VERSION 5.8 ;
BUSBITCHARS "[]" ;
DIVIDERCHAR "/" ;

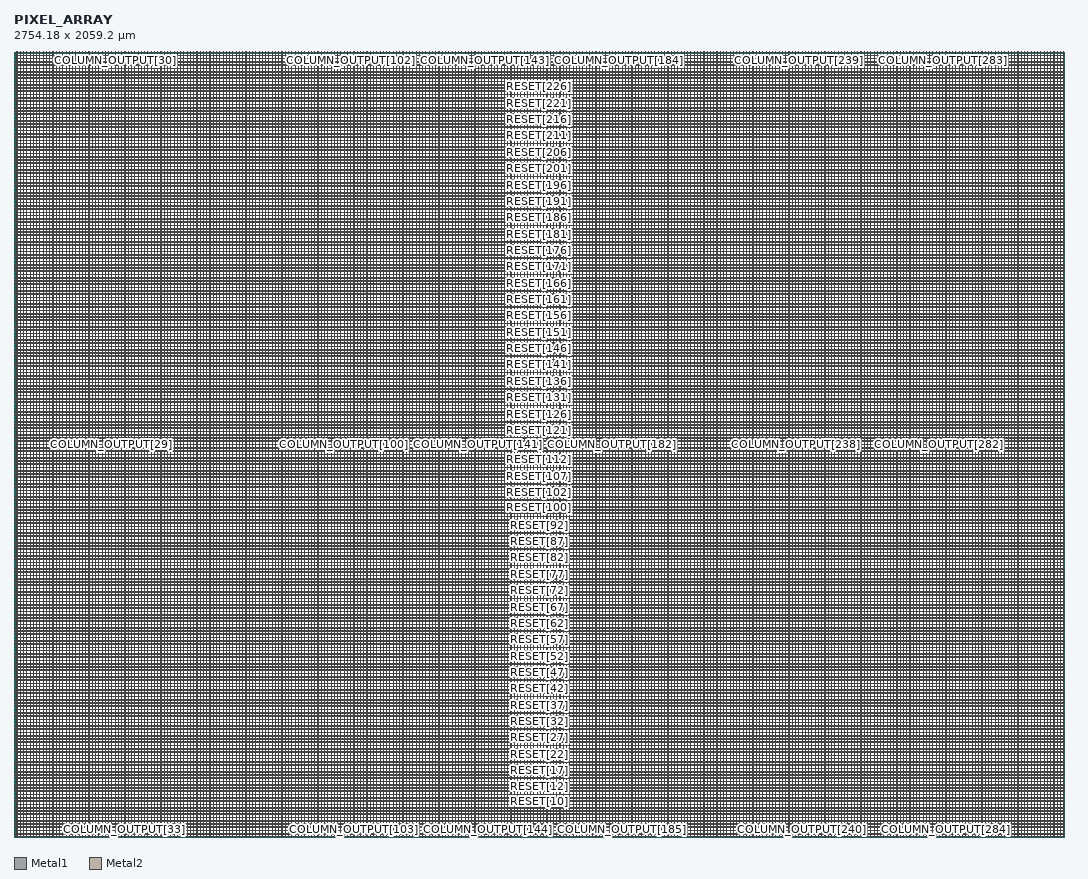
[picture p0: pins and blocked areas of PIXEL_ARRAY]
MACRO PIXEL_ARRAY
  CLASS BLOCK ;
  FOREIGN PIXEL_ARRAY 0 0 ;
  ORIGIN 0 0 ;
  SIZE 2754.18 BY 2059.2 ;

  PIN ROW_SELECT[0]
    DIRECTION INPUT ;
    USE SIGNAL ;
    PORT
      LAYER Metal1 ;
        RECT 0 0.305 2754.180 0.555 ;
    END
  END ROW_SELECT[0]

  PIN ROW_SELECT[1]
    DIRECTION INPUT ;
    USE SIGNAL ;
    PORT
      LAYER Metal1 ;
        RECT 0 8.885 2754.180 9.135 ;
    END
  END ROW_SELECT[1]

  PIN ROW_SELECT[2]
    DIRECTION INPUT ;
    USE SIGNAL ;
    PORT
      LAYER Metal1 ;
        RECT 0 17.465 2754.180 17.715 ;
    END
  END ROW_SELECT[2]

  PIN ROW_SELECT[3]
    DIRECTION INPUT ;
    USE SIGNAL ;
    PORT
      LAYER Metal1 ;
        RECT 0 26.045 2754.180 26.295 ;
    END
  END ROW_SELECT[3]

  PIN ROW_SELECT[4]
    DIRECTION INPUT ;
    USE SIGNAL ;
    PORT
      LAYER Metal1 ;
        RECT 0 34.625 2754.180 34.875 ;
    END
  END ROW_SELECT[4]

  PIN ROW_SELECT[5]
    DIRECTION INPUT ;
    USE SIGNAL ;
    PORT
      LAYER Metal1 ;
        RECT 0 43.205 2754.180 43.455 ;
    END
  END ROW_SELECT[5]

  PIN ROW_SELECT[6]
    DIRECTION INPUT ;
    USE SIGNAL ;
    PORT
      LAYER Metal1 ;
        RECT 0 51.785 2754.180 52.035 ;
    END
  END ROW_SELECT[6]

  PIN ROW_SELECT[7]
    DIRECTION INPUT ;
    USE SIGNAL ;
    PORT
      LAYER Metal1 ;
        RECT 0 60.365 2754.180 60.615 ;
    END
  END ROW_SELECT[7]

  PIN ROW_SELECT[8]
    DIRECTION INPUT ;
    USE SIGNAL ;
    PORT
      LAYER Metal1 ;
        RECT 0 68.945 2754.180 69.195 ;
    END
  END ROW_SELECT[8]

  PIN ROW_SELECT[9]
    DIRECTION INPUT ;
    USE SIGNAL ;
    PORT
      LAYER Metal1 ;
        RECT 0 77.525 2754.180 77.775 ;
    END
  END ROW_SELECT[9]

  PIN ROW_SELECT[10]
    DIRECTION INPUT ;
    USE SIGNAL ;
    PORT
      LAYER Metal1 ;
        RECT 0 86.105 2754.180 86.355 ;
    END
  END ROW_SELECT[10]

  PIN ROW_SELECT[11]
    DIRECTION INPUT ;
    USE SIGNAL ;
    PORT
      LAYER Metal1 ;
        RECT 0 94.685 2754.180 94.935 ;
    END
  END ROW_SELECT[11]

  PIN ROW_SELECT[12]
    DIRECTION INPUT ;
    USE SIGNAL ;
    PORT
      LAYER Metal1 ;
        RECT 0 103.265 2754.180 103.515 ;
    END
  END ROW_SELECT[12]

  PIN ROW_SELECT[13]
    DIRECTION INPUT ;
    USE SIGNAL ;
    PORT
      LAYER Metal1 ;
        RECT 0 111.845 2754.180 112.095 ;
    END
  END ROW_SELECT[13]

  PIN ROW_SELECT[14]
    DIRECTION INPUT ;
    USE SIGNAL ;
    PORT
      LAYER Metal1 ;
        RECT 0 120.425 2754.180 120.675 ;
    END
  END ROW_SELECT[14]

  PIN ROW_SELECT[15]
    DIRECTION INPUT ;
    USE SIGNAL ;
    PORT
      LAYER Metal1 ;
        RECT 0 129.005 2754.180 129.255 ;
    END
  END ROW_SELECT[15]

  PIN ROW_SELECT[16]
    DIRECTION INPUT ;
    USE SIGNAL ;
    PORT
      LAYER Metal1 ;
        RECT 0 137.585 2754.180 137.835 ;
    END
  END ROW_SELECT[16]

  PIN ROW_SELECT[17]
    DIRECTION INPUT ;
    USE SIGNAL ;
    PORT
      LAYER Metal1 ;
        RECT 0 146.165 2754.180 146.415 ;
    END
  END ROW_SELECT[17]

  PIN ROW_SELECT[18]
    DIRECTION INPUT ;
    USE SIGNAL ;
    PORT
      LAYER Metal1 ;
        RECT 0 154.745 2754.180 154.995 ;
    END
  END ROW_SELECT[18]

  PIN ROW_SELECT[19]
    DIRECTION INPUT ;
    USE SIGNAL ;
    PORT
      LAYER Metal1 ;
        RECT 0 163.325 2754.180 163.575 ;
    END
  END ROW_SELECT[19]

  PIN ROW_SELECT[20]
    DIRECTION INPUT ;
    USE SIGNAL ;
    PORT
      LAYER Metal1 ;
        RECT 0 171.905 2754.180 172.155 ;
    END
  END ROW_SELECT[20]

  PIN ROW_SELECT[21]
    DIRECTION INPUT ;
    USE SIGNAL ;
    PORT
      LAYER Metal1 ;
        RECT 0 180.485 2754.180 180.735 ;
    END
  END ROW_SELECT[21]

  PIN ROW_SELECT[22]
    DIRECTION INPUT ;
    USE SIGNAL ;
    PORT
      LAYER Metal1 ;
        RECT 0 189.065 2754.180 189.315 ;
    END
  END ROW_SELECT[22]

  PIN ROW_SELECT[23]
    DIRECTION INPUT ;
    USE SIGNAL ;
    PORT
      LAYER Metal1 ;
        RECT 0 197.645 2754.180 197.895 ;
    END
  END ROW_SELECT[23]

  PIN ROW_SELECT[24]
    DIRECTION INPUT ;
    USE SIGNAL ;
    PORT
      LAYER Metal1 ;
        RECT 0 206.225 2754.180 206.475 ;
    END
  END ROW_SELECT[24]

  PIN ROW_SELECT[25]
    DIRECTION INPUT ;
    USE SIGNAL ;
    PORT
      LAYER Metal1 ;
        RECT 0 214.805 2754.180 215.055 ;
    END
  END ROW_SELECT[25]

  PIN ROW_SELECT[26]
    DIRECTION INPUT ;
    USE SIGNAL ;
    PORT
      LAYER Metal1 ;
        RECT 0 223.385 2754.180 223.635 ;
    END
  END ROW_SELECT[26]

  PIN ROW_SELECT[27]
    DIRECTION INPUT ;
    USE SIGNAL ;
    PORT
      LAYER Metal1 ;
        RECT 0 231.965 2754.180 232.215 ;
    END
  END ROW_SELECT[27]

  PIN ROW_SELECT[28]
    DIRECTION INPUT ;
    USE SIGNAL ;
    PORT
      LAYER Metal1 ;
        RECT 0 240.545 2754.180 240.795 ;
    END
  END ROW_SELECT[28]

  PIN ROW_SELECT[29]
    DIRECTION INPUT ;
    USE SIGNAL ;
    PORT
      LAYER Metal1 ;
        RECT 0 249.125 2754.180 249.375 ;
    END
  END ROW_SELECT[29]

  PIN ROW_SELECT[30]
    DIRECTION INPUT ;
    USE SIGNAL ;
    PORT
      LAYER Metal1 ;
        RECT 0 257.705 2754.180 257.955 ;
    END
  END ROW_SELECT[30]

  PIN ROW_SELECT[31]
    DIRECTION INPUT ;
    USE SIGNAL ;
    PORT
      LAYER Metal1 ;
        RECT 0 266.285 2754.180 266.535 ;
    END
  END ROW_SELECT[31]

  PIN ROW_SELECT[32]
    DIRECTION INPUT ;
    USE SIGNAL ;
    PORT
      LAYER Metal1 ;
        RECT 0 274.865 2754.180 275.115 ;
    END
  END ROW_SELECT[32]

  PIN ROW_SELECT[33]
    DIRECTION INPUT ;
    USE SIGNAL ;
    PORT
      LAYER Metal1 ;
        RECT 0 283.445 2754.180 283.695 ;
    END
  END ROW_SELECT[33]

  PIN ROW_SELECT[34]
    DIRECTION INPUT ;
    USE SIGNAL ;
    PORT
      LAYER Metal1 ;
        RECT 0 292.025 2754.180 292.275 ;
    END
  END ROW_SELECT[34]

  PIN ROW_SELECT[35]
    DIRECTION INPUT ;
    USE SIGNAL ;
    PORT
      LAYER Metal1 ;
        RECT 0 300.605 2754.180 300.855 ;
    END
  END ROW_SELECT[35]

  PIN ROW_SELECT[36]
    DIRECTION INPUT ;
    USE SIGNAL ;
    PORT
      LAYER Metal1 ;
        RECT 0 309.185 2754.180 309.435 ;
    END
  END ROW_SELECT[36]

  PIN ROW_SELECT[37]
    DIRECTION INPUT ;
    USE SIGNAL ;
    PORT
      LAYER Metal1 ;
        RECT 0 317.765 2754.180 318.015 ;
    END
  END ROW_SELECT[37]

  PIN ROW_SELECT[38]
    DIRECTION INPUT ;
    USE SIGNAL ;
    PORT
      LAYER Metal1 ;
        RECT 0 326.345 2754.180 326.595 ;
    END
  END ROW_SELECT[38]

  PIN ROW_SELECT[39]
    DIRECTION INPUT ;
    USE SIGNAL ;
    PORT
      LAYER Metal1 ;
        RECT 0 334.925 2754.180 335.175 ;
    END
  END ROW_SELECT[39]

  PIN ROW_SELECT[40]
    DIRECTION INPUT ;
    USE SIGNAL ;
    PORT
      LAYER Metal1 ;
        RECT 0 343.505 2754.180 343.755 ;
    END
  END ROW_SELECT[40]

  PIN ROW_SELECT[41]
    DIRECTION INPUT ;
    USE SIGNAL ;
    PORT
      LAYER Metal1 ;
        RECT 0 352.085 2754.180 352.335 ;
    END
  END ROW_SELECT[41]

  PIN ROW_SELECT[42]
    DIRECTION INPUT ;
    USE SIGNAL ;
    PORT
      LAYER Metal1 ;
        RECT 0 360.665 2754.180 360.915 ;
    END
  END ROW_SELECT[42]

  PIN ROW_SELECT[43]
    DIRECTION INPUT ;
    USE SIGNAL ;
    PORT
      LAYER Metal1 ;
        RECT 0 369.245 2754.180 369.495 ;
    END
  END ROW_SELECT[43]

  PIN ROW_SELECT[44]
    DIRECTION INPUT ;
    USE SIGNAL ;
    PORT
      LAYER Metal1 ;
        RECT 0 377.825 2754.180 378.075 ;
    END
  END ROW_SELECT[44]

  PIN ROW_SELECT[45]
    DIRECTION INPUT ;
    USE SIGNAL ;
    PORT
      LAYER Metal1 ;
        RECT 0 386.405 2754.180 386.655 ;
    END
  END ROW_SELECT[45]

  PIN ROW_SELECT[46]
    DIRECTION INPUT ;
    USE SIGNAL ;
    PORT
      LAYER Metal1 ;
        RECT 0 394.985 2754.180 395.235 ;
    END
  END ROW_SELECT[46]

  PIN ROW_SELECT[47]
    DIRECTION INPUT ;
    USE SIGNAL ;
    PORT
      LAYER Metal1 ;
        RECT 0 403.565 2754.180 403.815 ;
    END
  END ROW_SELECT[47]

  PIN ROW_SELECT[48]
    DIRECTION INPUT ;
    USE SIGNAL ;
    PORT
      LAYER Metal1 ;
        RECT 0 412.145 2754.180 412.395 ;
    END
  END ROW_SELECT[48]

  PIN ROW_SELECT[49]
    DIRECTION INPUT ;
    USE SIGNAL ;
    PORT
      LAYER Metal1 ;
        RECT 0 420.725 2754.180 420.975 ;
    END
  END ROW_SELECT[49]

  PIN ROW_SELECT[50]
    DIRECTION INPUT ;
    USE SIGNAL ;
    PORT
      LAYER Metal1 ;
        RECT 0 429.305 2754.180 429.555 ;
    END
  END ROW_SELECT[50]

  PIN ROW_SELECT[51]
    DIRECTION INPUT ;
    USE SIGNAL ;
    PORT
      LAYER Metal1 ;
        RECT 0 437.885 2754.180 438.135 ;
    END
  END ROW_SELECT[51]

  PIN ROW_SELECT[52]
    DIRECTION INPUT ;
    USE SIGNAL ;
    PORT
      LAYER Metal1 ;
        RECT 0 446.465 2754.180 446.715 ;
    END
  END ROW_SELECT[52]

  PIN ROW_SELECT[53]
    DIRECTION INPUT ;
    USE SIGNAL ;
    PORT
      LAYER Metal1 ;
        RECT 0 455.045 2754.180 455.295 ;
    END
  END ROW_SELECT[53]

  PIN ROW_SELECT[54]
    DIRECTION INPUT ;
    USE SIGNAL ;
    PORT
      LAYER Metal1 ;
        RECT 0 463.625 2754.180 463.875 ;
    END
  END ROW_SELECT[54]

  PIN ROW_SELECT[55]
    DIRECTION INPUT ;
    USE SIGNAL ;
    PORT
      LAYER Metal1 ;
        RECT 0 472.205 2754.180 472.455 ;
    END
  END ROW_SELECT[55]

  PIN ROW_SELECT[56]
    DIRECTION INPUT ;
    USE SIGNAL ;
    PORT
      LAYER Metal1 ;
        RECT 0 480.785 2754.180 481.035 ;
    END
  END ROW_SELECT[56]

  PIN ROW_SELECT[57]
    DIRECTION INPUT ;
    USE SIGNAL ;
    PORT
      LAYER Metal1 ;
        RECT 0 489.365 2754.180 489.615 ;
    END
  END ROW_SELECT[57]

  PIN ROW_SELECT[58]
    DIRECTION INPUT ;
    USE SIGNAL ;
    PORT
      LAYER Metal1 ;
        RECT 0 497.945 2754.180 498.195 ;
    END
  END ROW_SELECT[58]

  PIN ROW_SELECT[59]
    DIRECTION INPUT ;
    USE SIGNAL ;
    PORT
      LAYER Metal1 ;
        RECT 0 506.525 2754.180 506.775 ;
    END
  END ROW_SELECT[59]

  PIN ROW_SELECT[60]
    DIRECTION INPUT ;
    USE SIGNAL ;
    PORT
      LAYER Metal1 ;
        RECT 0 515.105 2754.180 515.355 ;
    END
  END ROW_SELECT[60]

  PIN ROW_SELECT[61]
    DIRECTION INPUT ;
    USE SIGNAL ;
    PORT
      LAYER Metal1 ;
        RECT 0 523.685 2754.180 523.935 ;
    END
  END ROW_SELECT[61]

  PIN ROW_SELECT[62]
    DIRECTION INPUT ;
    USE SIGNAL ;
    PORT
      LAYER Metal1 ;
        RECT 0 532.265 2754.180 532.515 ;
    END
  END ROW_SELECT[62]

  PIN ROW_SELECT[63]
    DIRECTION INPUT ;
    USE SIGNAL ;
    PORT
      LAYER Metal1 ;
        RECT 0 540.845 2754.180 541.095 ;
    END
  END ROW_SELECT[63]

  PIN ROW_SELECT[64]
    DIRECTION INPUT ;
    USE SIGNAL ;
    PORT
      LAYER Metal1 ;
        RECT 0 549.425 2754.180 549.675 ;
    END
  END ROW_SELECT[64]

  PIN ROW_SELECT[65]
    DIRECTION INPUT ;
    USE SIGNAL ;
    PORT
      LAYER Metal1 ;
        RECT 0 558.005 2754.180 558.255 ;
    END
  END ROW_SELECT[65]

  PIN ROW_SELECT[66]
    DIRECTION INPUT ;
    USE SIGNAL ;
    PORT
      LAYER Metal1 ;
        RECT 0 566.585 2754.180 566.835 ;
    END
  END ROW_SELECT[66]

  PIN ROW_SELECT[67]
    DIRECTION INPUT ;
    USE SIGNAL ;
    PORT
      LAYER Metal1 ;
        RECT 0 575.165 2754.180 575.415 ;
    END
  END ROW_SELECT[67]

  PIN ROW_SELECT[68]
    DIRECTION INPUT ;
    USE SIGNAL ;
    PORT
      LAYER Metal1 ;
        RECT 0 583.745 2754.180 583.995 ;
    END
  END ROW_SELECT[68]

  PIN ROW_SELECT[69]
    DIRECTION INPUT ;
    USE SIGNAL ;
    PORT
      LAYER Metal1 ;
        RECT 0 592.325 2754.180 592.575 ;
    END
  END ROW_SELECT[69]

  PIN ROW_SELECT[70]
    DIRECTION INPUT ;
    USE SIGNAL ;
    PORT
      LAYER Metal1 ;
        RECT 0 600.905 2754.180 601.155 ;
    END
  END ROW_SELECT[70]

  PIN ROW_SELECT[71]
    DIRECTION INPUT ;
    USE SIGNAL ;
    PORT
      LAYER Metal1 ;
        RECT 0 609.485 2754.180 609.735 ;
    END
  END ROW_SELECT[71]

  PIN ROW_SELECT[72]
    DIRECTION INPUT ;
    USE SIGNAL ;
    PORT
      LAYER Metal1 ;
        RECT 0 618.065 2754.180 618.315 ;
    END
  END ROW_SELECT[72]

  PIN ROW_SELECT[73]
    DIRECTION INPUT ;
    USE SIGNAL ;
    PORT
      LAYER Metal1 ;
        RECT 0 626.645 2754.180 626.895 ;
    END
  END ROW_SELECT[73]

  PIN ROW_SELECT[74]
    DIRECTION INPUT ;
    USE SIGNAL ;
    PORT
      LAYER Metal1 ;
        RECT 0 635.225 2754.180 635.475 ;
    END
  END ROW_SELECT[74]

  PIN ROW_SELECT[75]
    DIRECTION INPUT ;
    USE SIGNAL ;
    PORT
      LAYER Metal1 ;
        RECT 0 643.805 2754.180 644.055 ;
    END
  END ROW_SELECT[75]

  PIN ROW_SELECT[76]
    DIRECTION INPUT ;
    USE SIGNAL ;
    PORT
      LAYER Metal1 ;
        RECT 0 652.385 2754.180 652.635 ;
    END
  END ROW_SELECT[76]

  PIN ROW_SELECT[77]
    DIRECTION INPUT ;
    USE SIGNAL ;
    PORT
      LAYER Metal1 ;
        RECT 0 660.965 2754.180 661.215 ;
    END
  END ROW_SELECT[77]

  PIN ROW_SELECT[78]
    DIRECTION INPUT ;
    USE SIGNAL ;
    PORT
      LAYER Metal1 ;
        RECT 0 669.545 2754.180 669.795 ;
    END
  END ROW_SELECT[78]

  PIN ROW_SELECT[79]
    DIRECTION INPUT ;
    USE SIGNAL ;
    PORT
      LAYER Metal1 ;
        RECT 0 678.125 2754.180 678.375 ;
    END
  END ROW_SELECT[79]

  PIN ROW_SELECT[80]
    DIRECTION INPUT ;
    USE SIGNAL ;
    PORT
      LAYER Metal1 ;
        RECT 0 686.705 2754.180 686.955 ;
    END
  END ROW_SELECT[80]

  PIN ROW_SELECT[81]
    DIRECTION INPUT ;
    USE SIGNAL ;
    PORT
      LAYER Metal1 ;
        RECT 0 695.285 2754.180 695.535 ;
    END
  END ROW_SELECT[81]

  PIN ROW_SELECT[82]
    DIRECTION INPUT ;
    USE SIGNAL ;
    PORT
      LAYER Metal1 ;
        RECT 0 703.865 2754.180 704.115 ;
    END
  END ROW_SELECT[82]

  PIN ROW_SELECT[83]
    DIRECTION INPUT ;
    USE SIGNAL ;
    PORT
      LAYER Metal1 ;
        RECT 0 712.445 2754.180 712.695 ;
    END
  END ROW_SELECT[83]

  PIN ROW_SELECT[84]
    DIRECTION INPUT ;
    USE SIGNAL ;
    PORT
      LAYER Metal1 ;
        RECT 0 721.025 2754.180 721.275 ;
    END
  END ROW_SELECT[84]

  PIN ROW_SELECT[85]
    DIRECTION INPUT ;
    USE SIGNAL ;
    PORT
      LAYER Metal1 ;
        RECT 0 729.605 2754.180 729.855 ;
    END
  END ROW_SELECT[85]

  PIN ROW_SELECT[86]
    DIRECTION INPUT ;
    USE SIGNAL ;
    PORT
      LAYER Metal1 ;
        RECT 0 738.185 2754.180 738.435 ;
    END
  END ROW_SELECT[86]

  PIN ROW_SELECT[87]
    DIRECTION INPUT ;
    USE SIGNAL ;
    PORT
      LAYER Metal1 ;
        RECT 0 746.765 2754.180 747.015 ;
    END
  END ROW_SELECT[87]

  PIN ROW_SELECT[88]
    DIRECTION INPUT ;
    USE SIGNAL ;
    PORT
      LAYER Metal1 ;
        RECT 0 755.345 2754.180 755.595 ;
    END
  END ROW_SELECT[88]

  PIN ROW_SELECT[89]
    DIRECTION INPUT ;
    USE SIGNAL ;
    PORT
      LAYER Metal1 ;
        RECT 0 763.925 2754.180 764.175 ;
    END
  END ROW_SELECT[89]

  PIN ROW_SELECT[90]
    DIRECTION INPUT ;
    USE SIGNAL ;
    PORT
      LAYER Metal1 ;
        RECT 0 772.505 2754.180 772.755 ;
    END
  END ROW_SELECT[90]

  PIN ROW_SELECT[91]
    DIRECTION INPUT ;
    USE SIGNAL ;
    PORT
      LAYER Metal1 ;
        RECT 0 781.085 2754.180 781.335 ;
    END
  END ROW_SELECT[91]

  PIN ROW_SELECT[92]
    DIRECTION INPUT ;
    USE SIGNAL ;
    PORT
      LAYER Metal1 ;
        RECT 0 789.665 2754.180 789.915 ;
    END
  END ROW_SELECT[92]

  PIN ROW_SELECT[93]
    DIRECTION INPUT ;
    USE SIGNAL ;
    PORT
      LAYER Metal1 ;
        RECT 0 798.245 2754.180 798.495 ;
    END
  END ROW_SELECT[93]

  PIN ROW_SELECT[94]
    DIRECTION INPUT ;
    USE SIGNAL ;
    PORT
      LAYER Metal1 ;
        RECT 0 806.825 2754.180 807.075 ;
    END
  END ROW_SELECT[94]

  PIN ROW_SELECT[95]
    DIRECTION INPUT ;
    USE SIGNAL ;
    PORT
      LAYER Metal1 ;
        RECT 0 815.405 2754.180 815.655 ;
    END
  END ROW_SELECT[95]

  PIN ROW_SELECT[96]
    DIRECTION INPUT ;
    USE SIGNAL ;
    PORT
      LAYER Metal1 ;
        RECT 0 823.985 2754.180 824.235 ;
    END
  END ROW_SELECT[96]

  PIN ROW_SELECT[97]
    DIRECTION INPUT ;
    USE SIGNAL ;
    PORT
      LAYER Metal1 ;
        RECT 0 832.565 2754.180 832.815 ;
    END
  END ROW_SELECT[97]

  PIN ROW_SELECT[98]
    DIRECTION INPUT ;
    USE SIGNAL ;
    PORT
      LAYER Metal1 ;
        RECT 0 841.145 2754.180 841.395 ;
    END
  END ROW_SELECT[98]

  PIN ROW_SELECT[99]
    DIRECTION INPUT ;
    USE SIGNAL ;
    PORT
      LAYER Metal1 ;
        RECT 0 849.725 2754.180 849.975 ;
    END
  END ROW_SELECT[99]

  PIN ROW_SELECT[100]
    DIRECTION INPUT ;
    USE SIGNAL ;
    PORT
      LAYER Metal1 ;
        RECT 0 858.305 2754.180 858.555 ;
    END
  END ROW_SELECT[100]

  PIN ROW_SELECT[101]
    DIRECTION INPUT ;
    USE SIGNAL ;
    PORT
      LAYER Metal1 ;
        RECT 0 866.885 2754.180 867.135 ;
    END
  END ROW_SELECT[101]

  PIN ROW_SELECT[102]
    DIRECTION INPUT ;
    USE SIGNAL ;
    PORT
      LAYER Metal1 ;
        RECT 0 875.465 2754.180 875.715 ;
    END
  END ROW_SELECT[102]

  PIN ROW_SELECT[103]
    DIRECTION INPUT ;
    USE SIGNAL ;
    PORT
      LAYER Metal1 ;
        RECT 0 884.045 2754.180 884.295 ;
    END
  END ROW_SELECT[103]

  PIN ROW_SELECT[104]
    DIRECTION INPUT ;
    USE SIGNAL ;
    PORT
      LAYER Metal1 ;
        RECT 0 892.625 2754.180 892.875 ;
    END
  END ROW_SELECT[104]

  PIN ROW_SELECT[105]
    DIRECTION INPUT ;
    USE SIGNAL ;
    PORT
      LAYER Metal1 ;
        RECT 0 901.205 2754.180 901.455 ;
    END
  END ROW_SELECT[105]

  PIN ROW_SELECT[106]
    DIRECTION INPUT ;
    USE SIGNAL ;
    PORT
      LAYER Metal1 ;
        RECT 0 909.785 2754.180 910.035 ;
    END
  END ROW_SELECT[106]

  PIN ROW_SELECT[107]
    DIRECTION INPUT ;
    USE SIGNAL ;
    PORT
      LAYER Metal1 ;
        RECT 0 918.365 2754.180 918.615 ;
    END
  END ROW_SELECT[107]

  PIN ROW_SELECT[108]
    DIRECTION INPUT ;
    USE SIGNAL ;
    PORT
      LAYER Metal1 ;
        RECT 0 926.945 2754.180 927.195 ;
    END
  END ROW_SELECT[108]

  PIN ROW_SELECT[109]
    DIRECTION INPUT ;
    USE SIGNAL ;
    PORT
      LAYER Metal1 ;
        RECT 0 935.525 2754.180 935.775 ;
    END
  END ROW_SELECT[109]

  PIN ROW_SELECT[110]
    DIRECTION INPUT ;
    USE SIGNAL ;
    PORT
      LAYER Metal1 ;
        RECT 0 944.105 2754.180 944.355 ;
    END
  END ROW_SELECT[110]

  PIN ROW_SELECT[111]
    DIRECTION INPUT ;
    USE SIGNAL ;
    PORT
      LAYER Metal1 ;
        RECT 0 952.685 2754.180 952.935 ;
    END
  END ROW_SELECT[111]

  PIN ROW_SELECT[112]
    DIRECTION INPUT ;
    USE SIGNAL ;
    PORT
      LAYER Metal1 ;
        RECT 0 961.265 2754.180 961.515 ;
    END
  END ROW_SELECT[112]

  PIN ROW_SELECT[113]
    DIRECTION INPUT ;
    USE SIGNAL ;
    PORT
      LAYER Metal1 ;
        RECT 0 969.845 2754.180 970.095 ;
    END
  END ROW_SELECT[113]

  PIN ROW_SELECT[114]
    DIRECTION INPUT ;
    USE SIGNAL ;
    PORT
      LAYER Metal1 ;
        RECT 0 978.425 2754.180 978.675 ;
    END
  END ROW_SELECT[114]

  PIN ROW_SELECT[115]
    DIRECTION INPUT ;
    USE SIGNAL ;
    PORT
      LAYER Metal1 ;
        RECT 0 987.005 2754.180 987.255 ;
    END
  END ROW_SELECT[115]

  PIN ROW_SELECT[116]
    DIRECTION INPUT ;
    USE SIGNAL ;
    PORT
      LAYER Metal1 ;
        RECT 0 995.585 2754.180 995.835 ;
    END
  END ROW_SELECT[116]

  PIN ROW_SELECT[117]
    DIRECTION INPUT ;
    USE SIGNAL ;
    PORT
      LAYER Metal1 ;
        RECT 0 1004.165 2754.180 1004.415 ;
    END
  END ROW_SELECT[117]

  PIN ROW_SELECT[118]
    DIRECTION INPUT ;
    USE SIGNAL ;
    PORT
      LAYER Metal1 ;
        RECT 0 1012.745 2754.180 1012.995 ;
    END
  END ROW_SELECT[118]

  PIN ROW_SELECT[119]
    DIRECTION INPUT ;
    USE SIGNAL ;
    PORT
      LAYER Metal1 ;
        RECT 0 1021.325 2754.180 1021.575 ;
    END
  END ROW_SELECT[119]

  PIN ROW_SELECT[120]
    DIRECTION INPUT ;
    USE SIGNAL ;
    PORT
      LAYER Metal1 ;
        RECT 0 1029.905 2754.180 1030.155 ;
    END
  END ROW_SELECT[120]

  PIN ROW_SELECT[121]
    DIRECTION INPUT ;
    USE SIGNAL ;
    PORT
      LAYER Metal1 ;
        RECT 0 1038.485 2754.180 1038.735 ;
    END
  END ROW_SELECT[121]

  PIN ROW_SELECT[122]
    DIRECTION INPUT ;
    USE SIGNAL ;
    PORT
      LAYER Metal1 ;
        RECT 0 1047.065 2754.180 1047.315 ;
    END
  END ROW_SELECT[122]

  PIN ROW_SELECT[123]
    DIRECTION INPUT ;
    USE SIGNAL ;
    PORT
      LAYER Metal1 ;
        RECT 0 1055.645 2754.180 1055.895 ;
    END
  END ROW_SELECT[123]

  PIN ROW_SELECT[124]
    DIRECTION INPUT ;
    USE SIGNAL ;
    PORT
      LAYER Metal1 ;
        RECT 0 1064.225 2754.180 1064.475 ;
    END
  END ROW_SELECT[124]

  PIN ROW_SELECT[125]
    DIRECTION INPUT ;
    USE SIGNAL ;
    PORT
      LAYER Metal1 ;
        RECT 0 1072.805 2754.180 1073.055 ;
    END
  END ROW_SELECT[125]

  PIN ROW_SELECT[126]
    DIRECTION INPUT ;
    USE SIGNAL ;
    PORT
      LAYER Metal1 ;
        RECT 0 1081.385 2754.180 1081.635 ;
    END
  END ROW_SELECT[126]

  PIN ROW_SELECT[127]
    DIRECTION INPUT ;
    USE SIGNAL ;
    PORT
      LAYER Metal1 ;
        RECT 0 1089.965 2754.180 1090.215 ;
    END
  END ROW_SELECT[127]

  PIN ROW_SELECT[128]
    DIRECTION INPUT ;
    USE SIGNAL ;
    PORT
      LAYER Metal1 ;
        RECT 0 1098.545 2754.180 1098.795 ;
    END
  END ROW_SELECT[128]

  PIN ROW_SELECT[129]
    DIRECTION INPUT ;
    USE SIGNAL ;
    PORT
      LAYER Metal1 ;
        RECT 0 1107.125 2754.180 1107.375 ;
    END
  END ROW_SELECT[129]

  PIN ROW_SELECT[130]
    DIRECTION INPUT ;
    USE SIGNAL ;
    PORT
      LAYER Metal1 ;
        RECT 0 1115.705 2754.180 1115.955 ;
    END
  END ROW_SELECT[130]

  PIN ROW_SELECT[131]
    DIRECTION INPUT ;
    USE SIGNAL ;
    PORT
      LAYER Metal1 ;
        RECT 0 1124.285 2754.180 1124.535 ;
    END
  END ROW_SELECT[131]

  PIN ROW_SELECT[132]
    DIRECTION INPUT ;
    USE SIGNAL ;
    PORT
      LAYER Metal1 ;
        RECT 0 1132.865 2754.180 1133.115 ;
    END
  END ROW_SELECT[132]

  PIN ROW_SELECT[133]
    DIRECTION INPUT ;
    USE SIGNAL ;
    PORT
      LAYER Metal1 ;
        RECT 0 1141.445 2754.180 1141.695 ;
    END
  END ROW_SELECT[133]

  PIN ROW_SELECT[134]
    DIRECTION INPUT ;
    USE SIGNAL ;
    PORT
      LAYER Metal1 ;
        RECT 0 1150.025 2754.180 1150.275 ;
    END
  END ROW_SELECT[134]

  PIN ROW_SELECT[135]
    DIRECTION INPUT ;
    USE SIGNAL ;
    PORT
      LAYER Metal1 ;
        RECT 0 1158.605 2754.180 1158.855 ;
    END
  END ROW_SELECT[135]

  PIN ROW_SELECT[136]
    DIRECTION INPUT ;
    USE SIGNAL ;
    PORT
      LAYER Metal1 ;
        RECT 0 1167.185 2754.180 1167.435 ;
    END
  END ROW_SELECT[136]

  PIN ROW_SELECT[137]
    DIRECTION INPUT ;
    USE SIGNAL ;
    PORT
      LAYER Metal1 ;
        RECT 0 1175.765 2754.180 1176.015 ;
    END
  END ROW_SELECT[137]

  PIN ROW_SELECT[138]
    DIRECTION INPUT ;
    USE SIGNAL ;
    PORT
      LAYER Metal1 ;
        RECT 0 1184.345 2754.180 1184.595 ;
    END
  END ROW_SELECT[138]

  PIN ROW_SELECT[139]
    DIRECTION INPUT ;
    USE SIGNAL ;
    PORT
      LAYER Metal1 ;
        RECT 0 1192.925 2754.180 1193.175 ;
    END
  END ROW_SELECT[139]

  PIN ROW_SELECT[140]
    DIRECTION INPUT ;
    USE SIGNAL ;
    PORT
      LAYER Metal1 ;
        RECT 0 1201.505 2754.180 1201.755 ;
    END
  END ROW_SELECT[140]

  PIN ROW_SELECT[141]
    DIRECTION INPUT ;
    USE SIGNAL ;
    PORT
      LAYER Metal1 ;
        RECT 0 1210.085 2754.180 1210.335 ;
    END
  END ROW_SELECT[141]

  PIN ROW_SELECT[142]
    DIRECTION INPUT ;
    USE SIGNAL ;
    PORT
      LAYER Metal1 ;
        RECT 0 1218.665 2754.180 1218.915 ;
    END
  END ROW_SELECT[142]

  PIN ROW_SELECT[143]
    DIRECTION INPUT ;
    USE SIGNAL ;
    PORT
      LAYER Metal1 ;
        RECT 0 1227.245 2754.180 1227.495 ;
    END
  END ROW_SELECT[143]

  PIN ROW_SELECT[144]
    DIRECTION INPUT ;
    USE SIGNAL ;
    PORT
      LAYER Metal1 ;
        RECT 0 1235.825 2754.180 1236.075 ;
    END
  END ROW_SELECT[144]

  PIN ROW_SELECT[145]
    DIRECTION INPUT ;
    USE SIGNAL ;
    PORT
      LAYER Metal1 ;
        RECT 0 1244.405 2754.180 1244.655 ;
    END
  END ROW_SELECT[145]

  PIN ROW_SELECT[146]
    DIRECTION INPUT ;
    USE SIGNAL ;
    PORT
      LAYER Metal1 ;
        RECT 0 1252.985 2754.180 1253.235 ;
    END
  END ROW_SELECT[146]

  PIN ROW_SELECT[147]
    DIRECTION INPUT ;
    USE SIGNAL ;
    PORT
      LAYER Metal1 ;
        RECT 0 1261.565 2754.180 1261.815 ;
    END
  END ROW_SELECT[147]

  PIN ROW_SELECT[148]
    DIRECTION INPUT ;
    USE SIGNAL ;
    PORT
      LAYER Metal1 ;
        RECT 0 1270.145 2754.180 1270.395 ;
    END
  END ROW_SELECT[148]

  PIN ROW_SELECT[149]
    DIRECTION INPUT ;
    USE SIGNAL ;
    PORT
      LAYER Metal1 ;
        RECT 0 1278.725 2754.180 1278.975 ;
    END
  END ROW_SELECT[149]

  PIN ROW_SELECT[150]
    DIRECTION INPUT ;
    USE SIGNAL ;
    PORT
      LAYER Metal1 ;
        RECT 0 1287.305 2754.180 1287.555 ;
    END
  END ROW_SELECT[150]

  PIN ROW_SELECT[151]
    DIRECTION INPUT ;
    USE SIGNAL ;
    PORT
      LAYER Metal1 ;
        RECT 0 1295.885 2754.180 1296.135 ;
    END
  END ROW_SELECT[151]

  PIN ROW_SELECT[152]
    DIRECTION INPUT ;
    USE SIGNAL ;
    PORT
      LAYER Metal1 ;
        RECT 0 1304.465 2754.180 1304.715 ;
    END
  END ROW_SELECT[152]

  PIN ROW_SELECT[153]
    DIRECTION INPUT ;
    USE SIGNAL ;
    PORT
      LAYER Metal1 ;
        RECT 0 1313.045 2754.180 1313.295 ;
    END
  END ROW_SELECT[153]

  PIN ROW_SELECT[154]
    DIRECTION INPUT ;
    USE SIGNAL ;
    PORT
      LAYER Metal1 ;
        RECT 0 1321.625 2754.180 1321.875 ;
    END
  END ROW_SELECT[154]

  PIN ROW_SELECT[155]
    DIRECTION INPUT ;
    USE SIGNAL ;
    PORT
      LAYER Metal1 ;
        RECT 0 1330.205 2754.180 1330.455 ;
    END
  END ROW_SELECT[155]

  PIN ROW_SELECT[156]
    DIRECTION INPUT ;
    USE SIGNAL ;
    PORT
      LAYER Metal1 ;
        RECT 0 1338.785 2754.180 1339.035 ;
    END
  END ROW_SELECT[156]

  PIN ROW_SELECT[157]
    DIRECTION INPUT ;
    USE SIGNAL ;
    PORT
      LAYER Metal1 ;
        RECT 0 1347.365 2754.180 1347.615 ;
    END
  END ROW_SELECT[157]

  PIN ROW_SELECT[158]
    DIRECTION INPUT ;
    USE SIGNAL ;
    PORT
      LAYER Metal1 ;
        RECT 0 1355.945 2754.180 1356.195 ;
    END
  END ROW_SELECT[158]

  PIN ROW_SELECT[159]
    DIRECTION INPUT ;
    USE SIGNAL ;
    PORT
      LAYER Metal1 ;
        RECT 0 1364.525 2754.180 1364.775 ;
    END
  END ROW_SELECT[159]

  PIN ROW_SELECT[160]
    DIRECTION INPUT ;
    USE SIGNAL ;
    PORT
      LAYER Metal1 ;
        RECT 0 1373.105 2754.180 1373.355 ;
    END
  END ROW_SELECT[160]

  PIN ROW_SELECT[161]
    DIRECTION INPUT ;
    USE SIGNAL ;
    PORT
      LAYER Metal1 ;
        RECT 0 1381.685 2754.180 1381.935 ;
    END
  END ROW_SELECT[161]

  PIN ROW_SELECT[162]
    DIRECTION INPUT ;
    USE SIGNAL ;
    PORT
      LAYER Metal1 ;
        RECT 0 1390.265 2754.180 1390.515 ;
    END
  END ROW_SELECT[162]

  PIN ROW_SELECT[163]
    DIRECTION INPUT ;
    USE SIGNAL ;
    PORT
      LAYER Metal1 ;
        RECT 0 1398.845 2754.180 1399.095 ;
    END
  END ROW_SELECT[163]

  PIN ROW_SELECT[164]
    DIRECTION INPUT ;
    USE SIGNAL ;
    PORT
      LAYER Metal1 ;
        RECT 0 1407.425 2754.180 1407.675 ;
    END
  END ROW_SELECT[164]

  PIN ROW_SELECT[165]
    DIRECTION INPUT ;
    USE SIGNAL ;
    PORT
      LAYER Metal1 ;
        RECT 0 1416.005 2754.180 1416.255 ;
    END
  END ROW_SELECT[165]

  PIN ROW_SELECT[166]
    DIRECTION INPUT ;
    USE SIGNAL ;
    PORT
      LAYER Metal1 ;
        RECT 0 1424.585 2754.180 1424.835 ;
    END
  END ROW_SELECT[166]

  PIN ROW_SELECT[167]
    DIRECTION INPUT ;
    USE SIGNAL ;
    PORT
      LAYER Metal1 ;
        RECT 0 1433.165 2754.180 1433.415 ;
    END
  END ROW_SELECT[167]

  PIN ROW_SELECT[168]
    DIRECTION INPUT ;
    USE SIGNAL ;
    PORT
      LAYER Metal1 ;
        RECT 0 1441.745 2754.180 1441.995 ;
    END
  END ROW_SELECT[168]

  PIN ROW_SELECT[169]
    DIRECTION INPUT ;
    USE SIGNAL ;
    PORT
      LAYER Metal1 ;
        RECT 0 1450.325 2754.180 1450.575 ;
    END
  END ROW_SELECT[169]

  PIN ROW_SELECT[170]
    DIRECTION INPUT ;
    USE SIGNAL ;
    PORT
      LAYER Metal1 ;
        RECT 0 1458.905 2754.180 1459.155 ;
    END
  END ROW_SELECT[170]

  PIN ROW_SELECT[171]
    DIRECTION INPUT ;
    USE SIGNAL ;
    PORT
      LAYER Metal1 ;
        RECT 0 1467.485 2754.180 1467.735 ;
    END
  END ROW_SELECT[171]

  PIN ROW_SELECT[172]
    DIRECTION INPUT ;
    USE SIGNAL ;
    PORT
      LAYER Metal1 ;
        RECT 0 1476.065 2754.180 1476.315 ;
    END
  END ROW_SELECT[172]

  PIN ROW_SELECT[173]
    DIRECTION INPUT ;
    USE SIGNAL ;
    PORT
      LAYER Metal1 ;
        RECT 0 1484.645 2754.180 1484.895 ;
    END
  END ROW_SELECT[173]

  PIN ROW_SELECT[174]
    DIRECTION INPUT ;
    USE SIGNAL ;
    PORT
      LAYER Metal1 ;
        RECT 0 1493.225 2754.180 1493.475 ;
    END
  END ROW_SELECT[174]

  PIN ROW_SELECT[175]
    DIRECTION INPUT ;
    USE SIGNAL ;
    PORT
      LAYER Metal1 ;
        RECT 0 1501.805 2754.180 1502.055 ;
    END
  END ROW_SELECT[175]

  PIN ROW_SELECT[176]
    DIRECTION INPUT ;
    USE SIGNAL ;
    PORT
      LAYER Metal1 ;
        RECT 0 1510.385 2754.180 1510.635 ;
    END
  END ROW_SELECT[176]

  PIN ROW_SELECT[177]
    DIRECTION INPUT ;
    USE SIGNAL ;
    PORT
      LAYER Metal1 ;
        RECT 0 1518.965 2754.180 1519.215 ;
    END
  END ROW_SELECT[177]

  PIN ROW_SELECT[178]
    DIRECTION INPUT ;
    USE SIGNAL ;
    PORT
      LAYER Metal1 ;
        RECT 0 1527.545 2754.180 1527.795 ;
    END
  END ROW_SELECT[178]

  PIN ROW_SELECT[179]
    DIRECTION INPUT ;
    USE SIGNAL ;
    PORT
      LAYER Metal1 ;
        RECT 0 1536.125 2754.180 1536.375 ;
    END
  END ROW_SELECT[179]

  PIN ROW_SELECT[180]
    DIRECTION INPUT ;
    USE SIGNAL ;
    PORT
      LAYER Metal1 ;
        RECT 0 1544.705 2754.180 1544.955 ;
    END
  END ROW_SELECT[180]

  PIN ROW_SELECT[181]
    DIRECTION INPUT ;
    USE SIGNAL ;
    PORT
      LAYER Metal1 ;
        RECT 0 1553.285 2754.180 1553.535 ;
    END
  END ROW_SELECT[181]

  PIN ROW_SELECT[182]
    DIRECTION INPUT ;
    USE SIGNAL ;
    PORT
      LAYER Metal1 ;
        RECT 0 1561.865 2754.180 1562.115 ;
    END
  END ROW_SELECT[182]

  PIN ROW_SELECT[183]
    DIRECTION INPUT ;
    USE SIGNAL ;
    PORT
      LAYER Metal1 ;
        RECT 0 1570.445 2754.180 1570.695 ;
    END
  END ROW_SELECT[183]

  PIN ROW_SELECT[184]
    DIRECTION INPUT ;
    USE SIGNAL ;
    PORT
      LAYER Metal1 ;
        RECT 0 1579.025 2754.180 1579.275 ;
    END
  END ROW_SELECT[184]

  PIN ROW_SELECT[185]
    DIRECTION INPUT ;
    USE SIGNAL ;
    PORT
      LAYER Metal1 ;
        RECT 0 1587.605 2754.180 1587.855 ;
    END
  END ROW_SELECT[185]

  PIN ROW_SELECT[186]
    DIRECTION INPUT ;
    USE SIGNAL ;
    PORT
      LAYER Metal1 ;
        RECT 0 1596.185 2754.180 1596.435 ;
    END
  END ROW_SELECT[186]

  PIN ROW_SELECT[187]
    DIRECTION INPUT ;
    USE SIGNAL ;
    PORT
      LAYER Metal1 ;
        RECT 0 1604.765 2754.180 1605.015 ;
    END
  END ROW_SELECT[187]

  PIN ROW_SELECT[188]
    DIRECTION INPUT ;
    USE SIGNAL ;
    PORT
      LAYER Metal1 ;
        RECT 0 1613.345 2754.180 1613.595 ;
    END
  END ROW_SELECT[188]

  PIN ROW_SELECT[189]
    DIRECTION INPUT ;
    USE SIGNAL ;
    PORT
      LAYER Metal1 ;
        RECT 0 1621.925 2754.180 1622.175 ;
    END
  END ROW_SELECT[189]

  PIN ROW_SELECT[190]
    DIRECTION INPUT ;
    USE SIGNAL ;
    PORT
      LAYER Metal1 ;
        RECT 0 1630.505 2754.180 1630.755 ;
    END
  END ROW_SELECT[190]

  PIN ROW_SELECT[191]
    DIRECTION INPUT ;
    USE SIGNAL ;
    PORT
      LAYER Metal1 ;
        RECT 0 1639.085 2754.180 1639.335 ;
    END
  END ROW_SELECT[191]

  PIN ROW_SELECT[192]
    DIRECTION INPUT ;
    USE SIGNAL ;
    PORT
      LAYER Metal1 ;
        RECT 0 1647.665 2754.180 1647.915 ;
    END
  END ROW_SELECT[192]

  PIN ROW_SELECT[193]
    DIRECTION INPUT ;
    USE SIGNAL ;
    PORT
      LAYER Metal1 ;
        RECT 0 1656.245 2754.180 1656.495 ;
    END
  END ROW_SELECT[193]

  PIN ROW_SELECT[194]
    DIRECTION INPUT ;
    USE SIGNAL ;
    PORT
      LAYER Metal1 ;
        RECT 0 1664.825 2754.180 1665.075 ;
    END
  END ROW_SELECT[194]

  PIN ROW_SELECT[195]
    DIRECTION INPUT ;
    USE SIGNAL ;
    PORT
      LAYER Metal1 ;
        RECT 0 1673.405 2754.180 1673.655 ;
    END
  END ROW_SELECT[195]

  PIN ROW_SELECT[196]
    DIRECTION INPUT ;
    USE SIGNAL ;
    PORT
      LAYER Metal1 ;
        RECT 0 1681.985 2754.180 1682.235 ;
    END
  END ROW_SELECT[196]

  PIN ROW_SELECT[197]
    DIRECTION INPUT ;
    USE SIGNAL ;
    PORT
      LAYER Metal1 ;
        RECT 0 1690.565 2754.180 1690.815 ;
    END
  END ROW_SELECT[197]

  PIN ROW_SELECT[198]
    DIRECTION INPUT ;
    USE SIGNAL ;
    PORT
      LAYER Metal1 ;
        RECT 0 1699.145 2754.180 1699.395 ;
    END
  END ROW_SELECT[198]

  PIN ROW_SELECT[199]
    DIRECTION INPUT ;
    USE SIGNAL ;
    PORT
      LAYER Metal1 ;
        RECT 0 1707.725 2754.180 1707.975 ;
    END
  END ROW_SELECT[199]

  PIN ROW_SELECT[200]
    DIRECTION INPUT ;
    USE SIGNAL ;
    PORT
      LAYER Metal1 ;
        RECT 0 1716.305 2754.180 1716.555 ;
    END
  END ROW_SELECT[200]

  PIN ROW_SELECT[201]
    DIRECTION INPUT ;
    USE SIGNAL ;
    PORT
      LAYER Metal1 ;
        RECT 0 1724.885 2754.180 1725.135 ;
    END
  END ROW_SELECT[201]

  PIN ROW_SELECT[202]
    DIRECTION INPUT ;
    USE SIGNAL ;
    PORT
      LAYER Metal1 ;
        RECT 0 1733.465 2754.180 1733.715 ;
    END
  END ROW_SELECT[202]

  PIN ROW_SELECT[203]
    DIRECTION INPUT ;
    USE SIGNAL ;
    PORT
      LAYER Metal1 ;
        RECT 0 1742.045 2754.180 1742.295 ;
    END
  END ROW_SELECT[203]

  PIN ROW_SELECT[204]
    DIRECTION INPUT ;
    USE SIGNAL ;
    PORT
      LAYER Metal1 ;
        RECT 0 1750.625 2754.180 1750.875 ;
    END
  END ROW_SELECT[204]

  PIN ROW_SELECT[205]
    DIRECTION INPUT ;
    USE SIGNAL ;
    PORT
      LAYER Metal1 ;
        RECT 0 1759.205 2754.180 1759.455 ;
    END
  END ROW_SELECT[205]

  PIN ROW_SELECT[206]
    DIRECTION INPUT ;
    USE SIGNAL ;
    PORT
      LAYER Metal1 ;
        RECT 0 1767.785 2754.180 1768.035 ;
    END
  END ROW_SELECT[206]

  PIN ROW_SELECT[207]
    DIRECTION INPUT ;
    USE SIGNAL ;
    PORT
      LAYER Metal1 ;
        RECT 0 1776.365 2754.180 1776.615 ;
    END
  END ROW_SELECT[207]

  PIN ROW_SELECT[208]
    DIRECTION INPUT ;
    USE SIGNAL ;
    PORT
      LAYER Metal1 ;
        RECT 0 1784.945 2754.180 1785.195 ;
    END
  END ROW_SELECT[208]

  PIN ROW_SELECT[209]
    DIRECTION INPUT ;
    USE SIGNAL ;
    PORT
      LAYER Metal1 ;
        RECT 0 1793.525 2754.180 1793.775 ;
    END
  END ROW_SELECT[209]

  PIN ROW_SELECT[210]
    DIRECTION INPUT ;
    USE SIGNAL ;
    PORT
      LAYER Metal1 ;
        RECT 0 1802.105 2754.180 1802.355 ;
    END
  END ROW_SELECT[210]

  PIN ROW_SELECT[211]
    DIRECTION INPUT ;
    USE SIGNAL ;
    PORT
      LAYER Metal1 ;
        RECT 0 1810.685 2754.180 1810.935 ;
    END
  END ROW_SELECT[211]

  PIN ROW_SELECT[212]
    DIRECTION INPUT ;
    USE SIGNAL ;
    PORT
      LAYER Metal1 ;
        RECT 0 1819.265 2754.180 1819.515 ;
    END
  END ROW_SELECT[212]

  PIN ROW_SELECT[213]
    DIRECTION INPUT ;
    USE SIGNAL ;
    PORT
      LAYER Metal1 ;
        RECT 0 1827.845 2754.180 1828.095 ;
    END
  END ROW_SELECT[213]

  PIN ROW_SELECT[214]
    DIRECTION INPUT ;
    USE SIGNAL ;
    PORT
      LAYER Metal1 ;
        RECT 0 1836.425 2754.180 1836.675 ;
    END
  END ROW_SELECT[214]

  PIN ROW_SELECT[215]
    DIRECTION INPUT ;
    USE SIGNAL ;
    PORT
      LAYER Metal1 ;
        RECT 0 1845.005 2754.180 1845.255 ;
    END
  END ROW_SELECT[215]

  PIN ROW_SELECT[216]
    DIRECTION INPUT ;
    USE SIGNAL ;
    PORT
      LAYER Metal1 ;
        RECT 0 1853.585 2754.180 1853.835 ;
    END
  END ROW_SELECT[216]

  PIN ROW_SELECT[217]
    DIRECTION INPUT ;
    USE SIGNAL ;
    PORT
      LAYER Metal1 ;
        RECT 0 1862.165 2754.180 1862.415 ;
    END
  END ROW_SELECT[217]

  PIN ROW_SELECT[218]
    DIRECTION INPUT ;
    USE SIGNAL ;
    PORT
      LAYER Metal1 ;
        RECT 0 1870.745 2754.180 1870.995 ;
    END
  END ROW_SELECT[218]

  PIN ROW_SELECT[219]
    DIRECTION INPUT ;
    USE SIGNAL ;
    PORT
      LAYER Metal1 ;
        RECT 0 1879.325 2754.180 1879.575 ;
    END
  END ROW_SELECT[219]

  PIN ROW_SELECT[220]
    DIRECTION INPUT ;
    USE SIGNAL ;
    PORT
      LAYER Metal1 ;
        RECT 0 1887.905 2754.180 1888.155 ;
    END
  END ROW_SELECT[220]

  PIN ROW_SELECT[221]
    DIRECTION INPUT ;
    USE SIGNAL ;
    PORT
      LAYER Metal1 ;
        RECT 0 1896.485 2754.180 1896.735 ;
    END
  END ROW_SELECT[221]

  PIN ROW_SELECT[222]
    DIRECTION INPUT ;
    USE SIGNAL ;
    PORT
      LAYER Metal1 ;
        RECT 0 1905.065 2754.180 1905.315 ;
    END
  END ROW_SELECT[222]

  PIN ROW_SELECT[223]
    DIRECTION INPUT ;
    USE SIGNAL ;
    PORT
      LAYER Metal1 ;
        RECT 0 1913.645 2754.180 1913.895 ;
    END
  END ROW_SELECT[223]

  PIN ROW_SELECT[224]
    DIRECTION INPUT ;
    USE SIGNAL ;
    PORT
      LAYER Metal1 ;
        RECT 0 1922.225 2754.180 1922.475 ;
    END
  END ROW_SELECT[224]

  PIN ROW_SELECT[225]
    DIRECTION INPUT ;
    USE SIGNAL ;
    PORT
      LAYER Metal1 ;
        RECT 0 1930.805 2754.180 1931.055 ;
    END
  END ROW_SELECT[225]

  PIN ROW_SELECT[226]
    DIRECTION INPUT ;
    USE SIGNAL ;
    PORT
      LAYER Metal1 ;
        RECT 0 1939.385 2754.180 1939.635 ;
    END
  END ROW_SELECT[226]

  PIN ROW_SELECT[227]
    DIRECTION INPUT ;
    USE SIGNAL ;
    PORT
      LAYER Metal1 ;
        RECT 0 1947.965 2754.180 1948.215 ;
    END
  END ROW_SELECT[227]

  PIN ROW_SELECT[228]
    DIRECTION INPUT ;
    USE SIGNAL ;
    PORT
      LAYER Metal1 ;
        RECT 0 1956.545 2754.180 1956.795 ;
    END
  END ROW_SELECT[228]

  PIN ROW_SELECT[229]
    DIRECTION INPUT ;
    USE SIGNAL ;
    PORT
      LAYER Metal1 ;
        RECT 0 1965.125 2754.180 1965.375 ;
    END
  END ROW_SELECT[229]

  PIN ROW_SELECT[230]
    DIRECTION INPUT ;
    USE SIGNAL ;
    PORT
      LAYER Metal1 ;
        RECT 0 1973.705 2754.180 1973.955 ;
    END
  END ROW_SELECT[230]

  PIN ROW_SELECT[231]
    DIRECTION INPUT ;
    USE SIGNAL ;
    PORT
      LAYER Metal1 ;
        RECT 0 1982.285 2754.180 1982.535 ;
    END
  END ROW_SELECT[231]

  PIN ROW_SELECT[232]
    DIRECTION INPUT ;
    USE SIGNAL ;
    PORT
      LAYER Metal1 ;
        RECT 0 1990.865 2754.180 1991.115 ;
    END
  END ROW_SELECT[232]

  PIN ROW_SELECT[233]
    DIRECTION INPUT ;
    USE SIGNAL ;
    PORT
      LAYER Metal1 ;
        RECT 0 1999.445 2754.180 1999.695 ;
    END
  END ROW_SELECT[233]

  PIN ROW_SELECT[234]
    DIRECTION INPUT ;
    USE SIGNAL ;
    PORT
      LAYER Metal1 ;
        RECT 0 2008.025 2754.180 2008.275 ;
    END
  END ROW_SELECT[234]

  PIN ROW_SELECT[235]
    DIRECTION INPUT ;
    USE SIGNAL ;
    PORT
      LAYER Metal1 ;
        RECT 0 2016.605 2754.180 2016.855 ;
    END
  END ROW_SELECT[235]

  PIN ROW_SELECT[236]
    DIRECTION INPUT ;
    USE SIGNAL ;
    PORT
      LAYER Metal1 ;
        RECT 0 2025.185 2754.180 2025.435 ;
    END
  END ROW_SELECT[236]

  PIN ROW_SELECT[237]
    DIRECTION INPUT ;
    USE SIGNAL ;
    PORT
      LAYER Metal1 ;
        RECT 0 2033.765 2754.180 2034.015 ;
    END
  END ROW_SELECT[237]

  PIN ROW_SELECT[238]
    DIRECTION INPUT ;
    USE SIGNAL ;
    PORT
      LAYER Metal1 ;
        RECT 0 2042.345 2754.180 2042.595 ;
    END
  END ROW_SELECT[238]

  PIN ROW_SELECT[239]
    DIRECTION INPUT ;
    USE SIGNAL ;
    PORT
      LAYER Metal1 ;
        RECT 0 2050.925 2754.180 2051.175 ;
    END
  END ROW_SELECT[239]

  PIN RESET[0]
    DIRECTION INPUT ;
    USE SIGNAL ;
    PORT
      LAYER Metal1 ;
        RECT 0 7.425 2754.180 7.675 ;
    END
  END RESET[0]

  PIN RESET[1]
    DIRECTION INPUT ;
    USE SIGNAL ;
    PORT
      LAYER Metal1 ;
        RECT 0 16.005 2754.180 16.255 ;
    END
  END RESET[1]

  PIN RESET[2]
    DIRECTION INPUT ;
    USE SIGNAL ;
    PORT
      LAYER Metal1 ;
        RECT 0 24.585 2754.180 24.835 ;
    END
  END RESET[2]

  PIN RESET[3]
    DIRECTION INPUT ;
    USE SIGNAL ;
    PORT
      LAYER Metal1 ;
        RECT 0 33.165 2754.180 33.415 ;
    END
  END RESET[3]

  PIN RESET[4]
    DIRECTION INPUT ;
    USE SIGNAL ;
    PORT
      LAYER Metal1 ;
        RECT 0 41.745 2754.180 41.995 ;
    END
  END RESET[4]

  PIN RESET[5]
    DIRECTION INPUT ;
    USE SIGNAL ;
    PORT
      LAYER Metal1 ;
        RECT 0 50.325 2754.180 50.575 ;
    END
  END RESET[5]

  PIN RESET[6]
    DIRECTION INPUT ;
    USE SIGNAL ;
    PORT
      LAYER Metal1 ;
        RECT 0 58.905 2754.180 59.155 ;
    END
  END RESET[6]

  PIN RESET[7]
    DIRECTION INPUT ;
    USE SIGNAL ;
    PORT
      LAYER Metal1 ;
        RECT 0 67.485 2754.180 67.735 ;
    END
  END RESET[7]

  PIN RESET[8]
    DIRECTION INPUT ;
    USE SIGNAL ;
    PORT
      LAYER Metal1 ;
        RECT 0 76.065 2754.180 76.315 ;
    END
  END RESET[8]

  PIN RESET[9]
    DIRECTION INPUT ;
    USE SIGNAL ;
    PORT
      LAYER Metal1 ;
        RECT 0 84.645 2754.180 84.895 ;
    END
  END RESET[9]

  PIN RESET[10]
    DIRECTION INPUT ;
    USE SIGNAL ;
    PORT
      LAYER Metal1 ;
        RECT 0 93.225 2754.180 93.475 ;
    END
  END RESET[10]

  PIN RESET[11]
    DIRECTION INPUT ;
    USE SIGNAL ;
    PORT
      LAYER Metal1 ;
        RECT 0 101.805 2754.180 102.055 ;
    END
  END RESET[11]

  PIN RESET[12]
    DIRECTION INPUT ;
    USE SIGNAL ;
    PORT
      LAYER Metal1 ;
        RECT 0 110.385 2754.180 110.635 ;
    END
  END RESET[12]

  PIN RESET[13]
    DIRECTION INPUT ;
    USE SIGNAL ;
    PORT
      LAYER Metal1 ;
        RECT 0 118.965 2754.180 119.215 ;
    END
  END RESET[13]

  PIN RESET[14]
    DIRECTION INPUT ;
    USE SIGNAL ;
    PORT
      LAYER Metal1 ;
        RECT 0 127.545 2754.180 127.795 ;
    END
  END RESET[14]

  PIN RESET[15]
    DIRECTION INPUT ;
    USE SIGNAL ;
    PORT
      LAYER Metal1 ;
        RECT 0 136.125 2754.180 136.375 ;
    END
  END RESET[15]

  PIN RESET[16]
    DIRECTION INPUT ;
    USE SIGNAL ;
    PORT
      LAYER Metal1 ;
        RECT 0 144.705 2754.180 144.955 ;
    END
  END RESET[16]

  PIN RESET[17]
    DIRECTION INPUT ;
    USE SIGNAL ;
    PORT
      LAYER Metal1 ;
        RECT 0 153.285 2754.180 153.535 ;
    END
  END RESET[17]

  PIN RESET[18]
    DIRECTION INPUT ;
    USE SIGNAL ;
    PORT
      LAYER Metal1 ;
        RECT 0 161.865 2754.180 162.115 ;
    END
  END RESET[18]

  PIN RESET[19]
    DIRECTION INPUT ;
    USE SIGNAL ;
    PORT
      LAYER Metal1 ;
        RECT 0 170.445 2754.180 170.695 ;
    END
  END RESET[19]

  PIN RESET[20]
    DIRECTION INPUT ;
    USE SIGNAL ;
    PORT
      LAYER Metal1 ;
        RECT 0 179.025 2754.180 179.275 ;
    END
  END RESET[20]

  PIN RESET[21]
    DIRECTION INPUT ;
    USE SIGNAL ;
    PORT
      LAYER Metal1 ;
        RECT 0 187.605 2754.180 187.855 ;
    END
  END RESET[21]

  PIN RESET[22]
    DIRECTION INPUT ;
    USE SIGNAL ;
    PORT
      LAYER Metal1 ;
        RECT 0 196.185 2754.180 196.435 ;
    END
  END RESET[22]

  PIN RESET[23]
    DIRECTION INPUT ;
    USE SIGNAL ;
    PORT
      LAYER Metal1 ;
        RECT 0 204.765 2754.180 205.015 ;
    END
  END RESET[23]

  PIN RESET[24]
    DIRECTION INPUT ;
    USE SIGNAL ;
    PORT
      LAYER Metal1 ;
        RECT 0 213.345 2754.180 213.595 ;
    END
  END RESET[24]

  PIN RESET[25]
    DIRECTION INPUT ;
    USE SIGNAL ;
    PORT
      LAYER Metal1 ;
        RECT 0 221.925 2754.180 222.175 ;
    END
  END RESET[25]

  PIN RESET[26]
    DIRECTION INPUT ;
    USE SIGNAL ;
    PORT
      LAYER Metal1 ;
        RECT 0 230.505 2754.180 230.755 ;
    END
  END RESET[26]

  PIN RESET[27]
    DIRECTION INPUT ;
    USE SIGNAL ;
    PORT
      LAYER Metal1 ;
        RECT 0 239.085 2754.180 239.335 ;
    END
  END RESET[27]

  PIN RESET[28]
    DIRECTION INPUT ;
    USE SIGNAL ;
    PORT
      LAYER Metal1 ;
        RECT 0 247.665 2754.180 247.915 ;
    END
  END RESET[28]

  PIN RESET[29]
    DIRECTION INPUT ;
    USE SIGNAL ;
    PORT
      LAYER Metal1 ;
        RECT 0 256.245 2754.180 256.495 ;
    END
  END RESET[29]

  PIN RESET[30]
    DIRECTION INPUT ;
    USE SIGNAL ;
    PORT
      LAYER Metal1 ;
        RECT 0 264.825 2754.180 265.075 ;
    END
  END RESET[30]

  PIN RESET[31]
    DIRECTION INPUT ;
    USE SIGNAL ;
    PORT
      LAYER Metal1 ;
        RECT 0 273.405 2754.180 273.655 ;
    END
  END RESET[31]

  PIN RESET[32]
    DIRECTION INPUT ;
    USE SIGNAL ;
    PORT
      LAYER Metal1 ;
        RECT 0 281.985 2754.180 282.235 ;
    END
  END RESET[32]

  PIN RESET[33]
    DIRECTION INPUT ;
    USE SIGNAL ;
    PORT
      LAYER Metal1 ;
        RECT 0 290.565 2754.180 290.815 ;
    END
  END RESET[33]

  PIN RESET[34]
    DIRECTION INPUT ;
    USE SIGNAL ;
    PORT
      LAYER Metal1 ;
        RECT 0 299.145 2754.180 299.395 ;
    END
  END RESET[34]

  PIN RESET[35]
    DIRECTION INPUT ;
    USE SIGNAL ;
    PORT
      LAYER Metal1 ;
        RECT 0 307.725 2754.180 307.975 ;
    END
  END RESET[35]

  PIN RESET[36]
    DIRECTION INPUT ;
    USE SIGNAL ;
    PORT
      LAYER Metal1 ;
        RECT 0 316.305 2754.180 316.555 ;
    END
  END RESET[36]

  PIN RESET[37]
    DIRECTION INPUT ;
    USE SIGNAL ;
    PORT
      LAYER Metal1 ;
        RECT 0 324.885 2754.180 325.135 ;
    END
  END RESET[37]

  PIN RESET[38]
    DIRECTION INPUT ;
    USE SIGNAL ;
    PORT
      LAYER Metal1 ;
        RECT 0 333.465 2754.180 333.715 ;
    END
  END RESET[38]

  PIN RESET[39]
    DIRECTION INPUT ;
    USE SIGNAL ;
    PORT
      LAYER Metal1 ;
        RECT 0 342.045 2754.180 342.295 ;
    END
  END RESET[39]

  PIN RESET[40]
    DIRECTION INPUT ;
    USE SIGNAL ;
    PORT
      LAYER Metal1 ;
        RECT 0 350.625 2754.180 350.875 ;
    END
  END RESET[40]

  PIN RESET[41]
    DIRECTION INPUT ;
    USE SIGNAL ;
    PORT
      LAYER Metal1 ;
        RECT 0 359.205 2754.180 359.455 ;
    END
  END RESET[41]

  PIN RESET[42]
    DIRECTION INPUT ;
    USE SIGNAL ;
    PORT
      LAYER Metal1 ;
        RECT 0 367.785 2754.180 368.035 ;
    END
  END RESET[42]

  PIN RESET[43]
    DIRECTION INPUT ;
    USE SIGNAL ;
    PORT
      LAYER Metal1 ;
        RECT 0 376.365 2754.180 376.615 ;
    END
  END RESET[43]

  PIN RESET[44]
    DIRECTION INPUT ;
    USE SIGNAL ;
    PORT
      LAYER Metal1 ;
        RECT 0 384.945 2754.180 385.195 ;
    END
  END RESET[44]

  PIN RESET[45]
    DIRECTION INPUT ;
    USE SIGNAL ;
    PORT
      LAYER Metal1 ;
        RECT 0 393.525 2754.180 393.775 ;
    END
  END RESET[45]

  PIN RESET[46]
    DIRECTION INPUT ;
    USE SIGNAL ;
    PORT
      LAYER Metal1 ;
        RECT 0 402.105 2754.180 402.355 ;
    END
  END RESET[46]

  PIN RESET[47]
    DIRECTION INPUT ;
    USE SIGNAL ;
    PORT
      LAYER Metal1 ;
        RECT 0 410.685 2754.180 410.935 ;
    END
  END RESET[47]

  PIN RESET[48]
    DIRECTION INPUT ;
    USE SIGNAL ;
    PORT
      LAYER Metal1 ;
        RECT 0 419.265 2754.180 419.515 ;
    END
  END RESET[48]

  PIN RESET[49]
    DIRECTION INPUT ;
    USE SIGNAL ;
    PORT
      LAYER Metal1 ;
        RECT 0 427.845 2754.180 428.095 ;
    END
  END RESET[49]

  PIN RESET[50]
    DIRECTION INPUT ;
    USE SIGNAL ;
    PORT
      LAYER Metal1 ;
        RECT 0 436.425 2754.180 436.675 ;
    END
  END RESET[50]

  PIN RESET[51]
    DIRECTION INPUT ;
    USE SIGNAL ;
    PORT
      LAYER Metal1 ;
        RECT 0 445.005 2754.180 445.255 ;
    END
  END RESET[51]

  PIN RESET[52]
    DIRECTION INPUT ;
    USE SIGNAL ;
    PORT
      LAYER Metal1 ;
        RECT 0 453.585 2754.180 453.835 ;
    END
  END RESET[52]

  PIN RESET[53]
    DIRECTION INPUT ;
    USE SIGNAL ;
    PORT
      LAYER Metal1 ;
        RECT 0 462.165 2754.180 462.415 ;
    END
  END RESET[53]

  PIN RESET[54]
    DIRECTION INPUT ;
    USE SIGNAL ;
    PORT
      LAYER Metal1 ;
        RECT 0 470.745 2754.180 470.995 ;
    END
  END RESET[54]

  PIN RESET[55]
    DIRECTION INPUT ;
    USE SIGNAL ;
    PORT
      LAYER Metal1 ;
        RECT 0 479.325 2754.180 479.575 ;
    END
  END RESET[55]

  PIN RESET[56]
    DIRECTION INPUT ;
    USE SIGNAL ;
    PORT
      LAYER Metal1 ;
        RECT 0 487.905 2754.180 488.155 ;
    END
  END RESET[56]

  PIN RESET[57]
    DIRECTION INPUT ;
    USE SIGNAL ;
    PORT
      LAYER Metal1 ;
        RECT 0 496.485 2754.180 496.735 ;
    END
  END RESET[57]

  PIN RESET[58]
    DIRECTION INPUT ;
    USE SIGNAL ;
    PORT
      LAYER Metal1 ;
        RECT 0 505.065 2754.180 505.315 ;
    END
  END RESET[58]

  PIN RESET[59]
    DIRECTION INPUT ;
    USE SIGNAL ;
    PORT
      LAYER Metal1 ;
        RECT 0 513.645 2754.180 513.895 ;
    END
  END RESET[59]

  PIN RESET[60]
    DIRECTION INPUT ;
    USE SIGNAL ;
    PORT
      LAYER Metal1 ;
        RECT 0 522.225 2754.180 522.475 ;
    END
  END RESET[60]

  PIN RESET[61]
    DIRECTION INPUT ;
    USE SIGNAL ;
    PORT
      LAYER Metal1 ;
        RECT 0 530.805 2754.180 531.055 ;
    END
  END RESET[61]

  PIN RESET[62]
    DIRECTION INPUT ;
    USE SIGNAL ;
    PORT
      LAYER Metal1 ;
        RECT 0 539.385 2754.180 539.635 ;
    END
  END RESET[62]

  PIN RESET[63]
    DIRECTION INPUT ;
    USE SIGNAL ;
    PORT
      LAYER Metal1 ;
        RECT 0 547.965 2754.180 548.215 ;
    END
  END RESET[63]

  PIN RESET[64]
    DIRECTION INPUT ;
    USE SIGNAL ;
    PORT
      LAYER Metal1 ;
        RECT 0 556.545 2754.180 556.795 ;
    END
  END RESET[64]

  PIN RESET[65]
    DIRECTION INPUT ;
    USE SIGNAL ;
    PORT
      LAYER Metal1 ;
        RECT 0 565.125 2754.180 565.375 ;
    END
  END RESET[65]

  PIN RESET[66]
    DIRECTION INPUT ;
    USE SIGNAL ;
    PORT
      LAYER Metal1 ;
        RECT 0 573.705 2754.180 573.955 ;
    END
  END RESET[66]

  PIN RESET[67]
    DIRECTION INPUT ;
    USE SIGNAL ;
    PORT
      LAYER Metal1 ;
        RECT 0 582.285 2754.180 582.535 ;
    END
  END RESET[67]

  PIN RESET[68]
    DIRECTION INPUT ;
    USE SIGNAL ;
    PORT
      LAYER Metal1 ;
        RECT 0 590.865 2754.180 591.115 ;
    END
  END RESET[68]

  PIN RESET[69]
    DIRECTION INPUT ;
    USE SIGNAL ;
    PORT
      LAYER Metal1 ;
        RECT 0 599.445 2754.180 599.695 ;
    END
  END RESET[69]

  PIN RESET[70]
    DIRECTION INPUT ;
    USE SIGNAL ;
    PORT
      LAYER Metal1 ;
        RECT 0 608.025 2754.180 608.275 ;
    END
  END RESET[70]

  PIN RESET[71]
    DIRECTION INPUT ;
    USE SIGNAL ;
    PORT
      LAYER Metal1 ;
        RECT 0 616.605 2754.180 616.855 ;
    END
  END RESET[71]

  PIN RESET[72]
    DIRECTION INPUT ;
    USE SIGNAL ;
    PORT
      LAYER Metal1 ;
        RECT 0 625.185 2754.180 625.435 ;
    END
  END RESET[72]

  PIN RESET[73]
    DIRECTION INPUT ;
    USE SIGNAL ;
    PORT
      LAYER Metal1 ;
        RECT 0 633.765 2754.180 634.015 ;
    END
  END RESET[73]

  PIN RESET[74]
    DIRECTION INPUT ;
    USE SIGNAL ;
    PORT
      LAYER Metal1 ;
        RECT 0 642.345 2754.180 642.595 ;
    END
  END RESET[74]

  PIN RESET[75]
    DIRECTION INPUT ;
    USE SIGNAL ;
    PORT
      LAYER Metal1 ;
        RECT 0 650.925 2754.180 651.175 ;
    END
  END RESET[75]

  PIN RESET[76]
    DIRECTION INPUT ;
    USE SIGNAL ;
    PORT
      LAYER Metal1 ;
        RECT 0 659.505 2754.180 659.755 ;
    END
  END RESET[76]

  PIN RESET[77]
    DIRECTION INPUT ;
    USE SIGNAL ;
    PORT
      LAYER Metal1 ;
        RECT 0 668.085 2754.180 668.335 ;
    END
  END RESET[77]

  PIN RESET[78]
    DIRECTION INPUT ;
    USE SIGNAL ;
    PORT
      LAYER Metal1 ;
        RECT 0 676.665 2754.180 676.915 ;
    END
  END RESET[78]

  PIN RESET[79]
    DIRECTION INPUT ;
    USE SIGNAL ;
    PORT
      LAYER Metal1 ;
        RECT 0 685.245 2754.180 685.495 ;
    END
  END RESET[79]

  PIN RESET[80]
    DIRECTION INPUT ;
    USE SIGNAL ;
    PORT
      LAYER Metal1 ;
        RECT 0 693.825 2754.180 694.075 ;
    END
  END RESET[80]

  PIN RESET[81]
    DIRECTION INPUT ;
    USE SIGNAL ;
    PORT
      LAYER Metal1 ;
        RECT 0 702.405 2754.180 702.655 ;
    END
  END RESET[81]

  PIN RESET[82]
    DIRECTION INPUT ;
    USE SIGNAL ;
    PORT
      LAYER Metal1 ;
        RECT 0 710.985 2754.180 711.235 ;
    END
  END RESET[82]

  PIN RESET[83]
    DIRECTION INPUT ;
    USE SIGNAL ;
    PORT
      LAYER Metal1 ;
        RECT 0 719.565 2754.180 719.815 ;
    END
  END RESET[83]

  PIN RESET[84]
    DIRECTION INPUT ;
    USE SIGNAL ;
    PORT
      LAYER Metal1 ;
        RECT 0 728.145 2754.180 728.395 ;
    END
  END RESET[84]

  PIN RESET[85]
    DIRECTION INPUT ;
    USE SIGNAL ;
    PORT
      LAYER Metal1 ;
        RECT 0 736.725 2754.180 736.975 ;
    END
  END RESET[85]

  PIN RESET[86]
    DIRECTION INPUT ;
    USE SIGNAL ;
    PORT
      LAYER Metal1 ;
        RECT 0 745.305 2754.180 745.555 ;
    END
  END RESET[86]

  PIN RESET[87]
    DIRECTION INPUT ;
    USE SIGNAL ;
    PORT
      LAYER Metal1 ;
        RECT 0 753.885 2754.180 754.135 ;
    END
  END RESET[87]

  PIN RESET[88]
    DIRECTION INPUT ;
    USE SIGNAL ;
    PORT
      LAYER Metal1 ;
        RECT 0 762.465 2754.180 762.715 ;
    END
  END RESET[88]

  PIN RESET[89]
    DIRECTION INPUT ;
    USE SIGNAL ;
    PORT
      LAYER Metal1 ;
        RECT 0 771.045 2754.180 771.295 ;
    END
  END RESET[89]

  PIN RESET[90]
    DIRECTION INPUT ;
    USE SIGNAL ;
    PORT
      LAYER Metal1 ;
        RECT 0 779.625 2754.180 779.875 ;
    END
  END RESET[90]

  PIN RESET[91]
    DIRECTION INPUT ;
    USE SIGNAL ;
    PORT
      LAYER Metal1 ;
        RECT 0 788.205 2754.180 788.455 ;
    END
  END RESET[91]

  PIN RESET[92]
    DIRECTION INPUT ;
    USE SIGNAL ;
    PORT
      LAYER Metal1 ;
        RECT 0 796.785 2754.180 797.035 ;
    END
  END RESET[92]

  PIN RESET[93]
    DIRECTION INPUT ;
    USE SIGNAL ;
    PORT
      LAYER Metal1 ;
        RECT 0 805.365 2754.180 805.615 ;
    END
  END RESET[93]

  PIN RESET[94]
    DIRECTION INPUT ;
    USE SIGNAL ;
    PORT
      LAYER Metal1 ;
        RECT 0 813.945 2754.180 814.195 ;
    END
  END RESET[94]

  PIN RESET[95]
    DIRECTION INPUT ;
    USE SIGNAL ;
    PORT
      LAYER Metal1 ;
        RECT 0 822.525 2754.180 822.775 ;
    END
  END RESET[95]

  PIN RESET[96]
    DIRECTION INPUT ;
    USE SIGNAL ;
    PORT
      LAYER Metal1 ;
        RECT 0 831.105 2754.180 831.355 ;
    END
  END RESET[96]

  PIN RESET[97]
    DIRECTION INPUT ;
    USE SIGNAL ;
    PORT
      LAYER Metal1 ;
        RECT 0 839.685 2754.180 839.935 ;
    END
  END RESET[97]

  PIN RESET[98]
    DIRECTION INPUT ;
    USE SIGNAL ;
    PORT
      LAYER Metal1 ;
        RECT 0 848.265 2754.180 848.515 ;
    END
  END RESET[98]

  PIN RESET[99]
    DIRECTION INPUT ;
    USE SIGNAL ;
    PORT
      LAYER Metal1 ;
        RECT 0 856.845 2754.180 857.095 ;
    END
  END RESET[99]

  PIN RESET[100]
    DIRECTION INPUT ;
    USE SIGNAL ;
    PORT
      LAYER Metal1 ;
        RECT 0 865.425 2754.180 865.675 ;
    END
  END RESET[100]

  PIN RESET[101]
    DIRECTION INPUT ;
    USE SIGNAL ;
    PORT
      LAYER Metal1 ;
        RECT 0 874.005 2754.180 874.255 ;
    END
  END RESET[101]

  PIN RESET[102]
    DIRECTION INPUT ;
    USE SIGNAL ;
    PORT
      LAYER Metal1 ;
        RECT 0 882.585 2754.180 882.835 ;
    END
  END RESET[102]

  PIN RESET[103]
    DIRECTION INPUT ;
    USE SIGNAL ;
    PORT
      LAYER Metal1 ;
        RECT 0 891.165 2754.180 891.415 ;
    END
  END RESET[103]

  PIN RESET[104]
    DIRECTION INPUT ;
    USE SIGNAL ;
    PORT
      LAYER Metal1 ;
        RECT 0 899.745 2754.180 899.995 ;
    END
  END RESET[104]

  PIN RESET[105]
    DIRECTION INPUT ;
    USE SIGNAL ;
    PORT
      LAYER Metal1 ;
        RECT 0 908.325 2754.180 908.575 ;
    END
  END RESET[105]

  PIN RESET[106]
    DIRECTION INPUT ;
    USE SIGNAL ;
    PORT
      LAYER Metal1 ;
        RECT 0 916.905 2754.180 917.155 ;
    END
  END RESET[106]

  PIN RESET[107]
    DIRECTION INPUT ;
    USE SIGNAL ;
    PORT
      LAYER Metal1 ;
        RECT 0 925.485 2754.180 925.735 ;
    END
  END RESET[107]

  PIN RESET[108]
    DIRECTION INPUT ;
    USE SIGNAL ;
    PORT
      LAYER Metal1 ;
        RECT 0 934.065 2754.180 934.315 ;
    END
  END RESET[108]

  PIN RESET[109]
    DIRECTION INPUT ;
    USE SIGNAL ;
    PORT
      LAYER Metal1 ;
        RECT 0 942.645 2754.180 942.895 ;
    END
  END RESET[109]

  PIN RESET[110]
    DIRECTION INPUT ;
    USE SIGNAL ;
    PORT
      LAYER Metal1 ;
        RECT 0 951.225 2754.180 951.475 ;
    END
  END RESET[110]

  PIN RESET[111]
    DIRECTION INPUT ;
    USE SIGNAL ;
    PORT
      LAYER Metal1 ;
        RECT 0 959.805 2754.180 960.055 ;
    END
  END RESET[111]

  PIN RESET[112]
    DIRECTION INPUT ;
    USE SIGNAL ;
    PORT
      LAYER Metal1 ;
        RECT 0 968.385 2754.180 968.635 ;
    END
  END RESET[112]

  PIN RESET[113]
    DIRECTION INPUT ;
    USE SIGNAL ;
    PORT
      LAYER Metal1 ;
        RECT 0 976.965 2754.180 977.215 ;
    END
  END RESET[113]

  PIN RESET[114]
    DIRECTION INPUT ;
    USE SIGNAL ;
    PORT
      LAYER Metal1 ;
        RECT 0 985.545 2754.180 985.795 ;
    END
  END RESET[114]

  PIN RESET[115]
    DIRECTION INPUT ;
    USE SIGNAL ;
    PORT
      LAYER Metal1 ;
        RECT 0 994.125 2754.180 994.375 ;
    END
  END RESET[115]

  PIN RESET[116]
    DIRECTION INPUT ;
    USE SIGNAL ;
    PORT
      LAYER Metal1 ;
        RECT 0 1002.705 2754.180 1002.955 ;
    END
  END RESET[116]

  PIN RESET[117]
    DIRECTION INPUT ;
    USE SIGNAL ;
    PORT
      LAYER Metal1 ;
        RECT 0 1011.285 2754.180 1011.535 ;
    END
  END RESET[117]

  PIN RESET[118]
    DIRECTION INPUT ;
    USE SIGNAL ;
    PORT
      LAYER Metal1 ;
        RECT 0 1019.865 2754.180 1020.115 ;
    END
  END RESET[118]

  PIN RESET[119]
    DIRECTION INPUT ;
    USE SIGNAL ;
    PORT
      LAYER Metal1 ;
        RECT 0 1028.445 2754.180 1028.695 ;
    END
  END RESET[119]

  PIN RESET[120]
    DIRECTION INPUT ;
    USE SIGNAL ;
    PORT
      LAYER Metal1 ;
        RECT 0 1037.025 2754.180 1037.275 ;
    END
  END RESET[120]

  PIN RESET[121]
    DIRECTION INPUT ;
    USE SIGNAL ;
    PORT
      LAYER Metal1 ;
        RECT 0 1045.605 2754.180 1045.855 ;
    END
  END RESET[121]

  PIN RESET[122]
    DIRECTION INPUT ;
    USE SIGNAL ;
    PORT
      LAYER Metal1 ;
        RECT 0 1054.185 2754.180 1054.435 ;
    END
  END RESET[122]

  PIN RESET[123]
    DIRECTION INPUT ;
    USE SIGNAL ;
    PORT
      LAYER Metal1 ;
        RECT 0 1062.765 2754.180 1063.015 ;
    END
  END RESET[123]

  PIN RESET[124]
    DIRECTION INPUT ;
    USE SIGNAL ;
    PORT
      LAYER Metal1 ;
        RECT 0 1071.345 2754.180 1071.595 ;
    END
  END RESET[124]

  PIN RESET[125]
    DIRECTION INPUT ;
    USE SIGNAL ;
    PORT
      LAYER Metal1 ;
        RECT 0 1079.925 2754.180 1080.175 ;
    END
  END RESET[125]

  PIN RESET[126]
    DIRECTION INPUT ;
    USE SIGNAL ;
    PORT
      LAYER Metal1 ;
        RECT 0 1088.505 2754.180 1088.755 ;
    END
  END RESET[126]

  PIN RESET[127]
    DIRECTION INPUT ;
    USE SIGNAL ;
    PORT
      LAYER Metal1 ;
        RECT 0 1097.085 2754.180 1097.335 ;
    END
  END RESET[127]

  PIN RESET[128]
    DIRECTION INPUT ;
    USE SIGNAL ;
    PORT
      LAYER Metal1 ;
        RECT 0 1105.665 2754.180 1105.915 ;
    END
  END RESET[128]

  PIN RESET[129]
    DIRECTION INPUT ;
    USE SIGNAL ;
    PORT
      LAYER Metal1 ;
        RECT 0 1114.245 2754.180 1114.495 ;
    END
  END RESET[129]

  PIN RESET[130]
    DIRECTION INPUT ;
    USE SIGNAL ;
    PORT
      LAYER Metal1 ;
        RECT 0 1122.825 2754.180 1123.075 ;
    END
  END RESET[130]

  PIN RESET[131]
    DIRECTION INPUT ;
    USE SIGNAL ;
    PORT
      LAYER Metal1 ;
        RECT 0 1131.405 2754.180 1131.655 ;
    END
  END RESET[131]

  PIN RESET[132]
    DIRECTION INPUT ;
    USE SIGNAL ;
    PORT
      LAYER Metal1 ;
        RECT 0 1139.985 2754.180 1140.235 ;
    END
  END RESET[132]

  PIN RESET[133]
    DIRECTION INPUT ;
    USE SIGNAL ;
    PORT
      LAYER Metal1 ;
        RECT 0 1148.565 2754.180 1148.815 ;
    END
  END RESET[133]

  PIN RESET[134]
    DIRECTION INPUT ;
    USE SIGNAL ;
    PORT
      LAYER Metal1 ;
        RECT 0 1157.145 2754.180 1157.395 ;
    END
  END RESET[134]

  PIN RESET[135]
    DIRECTION INPUT ;
    USE SIGNAL ;
    PORT
      LAYER Metal1 ;
        RECT 0 1165.725 2754.180 1165.975 ;
    END
  END RESET[135]

  PIN RESET[136]
    DIRECTION INPUT ;
    USE SIGNAL ;
    PORT
      LAYER Metal1 ;
        RECT 0 1174.305 2754.180 1174.555 ;
    END
  END RESET[136]

  PIN RESET[137]
    DIRECTION INPUT ;
    USE SIGNAL ;
    PORT
      LAYER Metal1 ;
        RECT 0 1182.885 2754.180 1183.135 ;
    END
  END RESET[137]

  PIN RESET[138]
    DIRECTION INPUT ;
    USE SIGNAL ;
    PORT
      LAYER Metal1 ;
        RECT 0 1191.465 2754.180 1191.715 ;
    END
  END RESET[138]

  PIN RESET[139]
    DIRECTION INPUT ;
    USE SIGNAL ;
    PORT
      LAYER Metal1 ;
        RECT 0 1200.045 2754.180 1200.295 ;
    END
  END RESET[139]

  PIN RESET[140]
    DIRECTION INPUT ;
    USE SIGNAL ;
    PORT
      LAYER Metal1 ;
        RECT 0 1208.625 2754.180 1208.875 ;
    END
  END RESET[140]

  PIN RESET[141]
    DIRECTION INPUT ;
    USE SIGNAL ;
    PORT
      LAYER Metal1 ;
        RECT 0 1217.205 2754.180 1217.455 ;
    END
  END RESET[141]

  PIN RESET[142]
    DIRECTION INPUT ;
    USE SIGNAL ;
    PORT
      LAYER Metal1 ;
        RECT 0 1225.785 2754.180 1226.035 ;
    END
  END RESET[142]

  PIN RESET[143]
    DIRECTION INPUT ;
    USE SIGNAL ;
    PORT
      LAYER Metal1 ;
        RECT 0 1234.365 2754.180 1234.615 ;
    END
  END RESET[143]

  PIN RESET[144]
    DIRECTION INPUT ;
    USE SIGNAL ;
    PORT
      LAYER Metal1 ;
        RECT 0 1242.945 2754.180 1243.195 ;
    END
  END RESET[144]

  PIN RESET[145]
    DIRECTION INPUT ;
    USE SIGNAL ;
    PORT
      LAYER Metal1 ;
        RECT 0 1251.525 2754.180 1251.775 ;
    END
  END RESET[145]

  PIN RESET[146]
    DIRECTION INPUT ;
    USE SIGNAL ;
    PORT
      LAYER Metal1 ;
        RECT 0 1260.105 2754.180 1260.355 ;
    END
  END RESET[146]

  PIN RESET[147]
    DIRECTION INPUT ;
    USE SIGNAL ;
    PORT
      LAYER Metal1 ;
        RECT 0 1268.685 2754.180 1268.935 ;
    END
  END RESET[147]

  PIN RESET[148]
    DIRECTION INPUT ;
    USE SIGNAL ;
    PORT
      LAYER Metal1 ;
        RECT 0 1277.265 2754.180 1277.515 ;
    END
  END RESET[148]

  PIN RESET[149]
    DIRECTION INPUT ;
    USE SIGNAL ;
    PORT
      LAYER Metal1 ;
        RECT 0 1285.845 2754.180 1286.095 ;
    END
  END RESET[149]

  PIN RESET[150]
    DIRECTION INPUT ;
    USE SIGNAL ;
    PORT
      LAYER Metal1 ;
        RECT 0 1294.425 2754.180 1294.675 ;
    END
  END RESET[150]

  PIN RESET[151]
    DIRECTION INPUT ;
    USE SIGNAL ;
    PORT
      LAYER Metal1 ;
        RECT 0 1303.005 2754.180 1303.255 ;
    END
  END RESET[151]

  PIN RESET[152]
    DIRECTION INPUT ;
    USE SIGNAL ;
    PORT
      LAYER Metal1 ;
        RECT 0 1311.585 2754.180 1311.835 ;
    END
  END RESET[152]

  PIN RESET[153]
    DIRECTION INPUT ;
    USE SIGNAL ;
    PORT
      LAYER Metal1 ;
        RECT 0 1320.165 2754.180 1320.415 ;
    END
  END RESET[153]

  PIN RESET[154]
    DIRECTION INPUT ;
    USE SIGNAL ;
    PORT
      LAYER Metal1 ;
        RECT 0 1328.745 2754.180 1328.995 ;
    END
  END RESET[154]

  PIN RESET[155]
    DIRECTION INPUT ;
    USE SIGNAL ;
    PORT
      LAYER Metal1 ;
        RECT 0 1337.325 2754.180 1337.575 ;
    END
  END RESET[155]

  PIN RESET[156]
    DIRECTION INPUT ;
    USE SIGNAL ;
    PORT
      LAYER Metal1 ;
        RECT 0 1345.905 2754.180 1346.155 ;
    END
  END RESET[156]

  PIN RESET[157]
    DIRECTION INPUT ;
    USE SIGNAL ;
    PORT
      LAYER Metal1 ;
        RECT 0 1354.485 2754.180 1354.735 ;
    END
  END RESET[157]

  PIN RESET[158]
    DIRECTION INPUT ;
    USE SIGNAL ;
    PORT
      LAYER Metal1 ;
        RECT 0 1363.065 2754.180 1363.315 ;
    END
  END RESET[158]

  PIN RESET[159]
    DIRECTION INPUT ;
    USE SIGNAL ;
    PORT
      LAYER Metal1 ;
        RECT 0 1371.645 2754.180 1371.895 ;
    END
  END RESET[159]

  PIN RESET[160]
    DIRECTION INPUT ;
    USE SIGNAL ;
    PORT
      LAYER Metal1 ;
        RECT 0 1380.225 2754.180 1380.475 ;
    END
  END RESET[160]

  PIN RESET[161]
    DIRECTION INPUT ;
    USE SIGNAL ;
    PORT
      LAYER Metal1 ;
        RECT 0 1388.805 2754.180 1389.055 ;
    END
  END RESET[161]

  PIN RESET[162]
    DIRECTION INPUT ;
    USE SIGNAL ;
    PORT
      LAYER Metal1 ;
        RECT 0 1397.385 2754.180 1397.635 ;
    END
  END RESET[162]

  PIN RESET[163]
    DIRECTION INPUT ;
    USE SIGNAL ;
    PORT
      LAYER Metal1 ;
        RECT 0 1405.965 2754.180 1406.215 ;
    END
  END RESET[163]

  PIN RESET[164]
    DIRECTION INPUT ;
    USE SIGNAL ;
    PORT
      LAYER Metal1 ;
        RECT 0 1414.545 2754.180 1414.795 ;
    END
  END RESET[164]

  PIN RESET[165]
    DIRECTION INPUT ;
    USE SIGNAL ;
    PORT
      LAYER Metal1 ;
        RECT 0 1423.125 2754.180 1423.375 ;
    END
  END RESET[165]

  PIN RESET[166]
    DIRECTION INPUT ;
    USE SIGNAL ;
    PORT
      LAYER Metal1 ;
        RECT 0 1431.705 2754.180 1431.955 ;
    END
  END RESET[166]

  PIN RESET[167]
    DIRECTION INPUT ;
    USE SIGNAL ;
    PORT
      LAYER Metal1 ;
        RECT 0 1440.285 2754.180 1440.535 ;
    END
  END RESET[167]

  PIN RESET[168]
    DIRECTION INPUT ;
    USE SIGNAL ;
    PORT
      LAYER Metal1 ;
        RECT 0 1448.865 2754.180 1449.115 ;
    END
  END RESET[168]

  PIN RESET[169]
    DIRECTION INPUT ;
    USE SIGNAL ;
    PORT
      LAYER Metal1 ;
        RECT 0 1457.445 2754.180 1457.695 ;
    END
  END RESET[169]

  PIN RESET[170]
    DIRECTION INPUT ;
    USE SIGNAL ;
    PORT
      LAYER Metal1 ;
        RECT 0 1466.025 2754.180 1466.275 ;
    END
  END RESET[170]

  PIN RESET[171]
    DIRECTION INPUT ;
    USE SIGNAL ;
    PORT
      LAYER Metal1 ;
        RECT 0 1474.605 2754.180 1474.855 ;
    END
  END RESET[171]

  PIN RESET[172]
    DIRECTION INPUT ;
    USE SIGNAL ;
    PORT
      LAYER Metal1 ;
        RECT 0 1483.185 2754.180 1483.435 ;
    END
  END RESET[172]

  PIN RESET[173]
    DIRECTION INPUT ;
    USE SIGNAL ;
    PORT
      LAYER Metal1 ;
        RECT 0 1491.765 2754.180 1492.015 ;
    END
  END RESET[173]

  PIN RESET[174]
    DIRECTION INPUT ;
    USE SIGNAL ;
    PORT
      LAYER Metal1 ;
        RECT 0 1500.345 2754.180 1500.595 ;
    END
  END RESET[174]

  PIN RESET[175]
    DIRECTION INPUT ;
    USE SIGNAL ;
    PORT
      LAYER Metal1 ;
        RECT 0 1508.925 2754.180 1509.175 ;
    END
  END RESET[175]

  PIN RESET[176]
    DIRECTION INPUT ;
    USE SIGNAL ;
    PORT
      LAYER Metal1 ;
        RECT 0 1517.505 2754.180 1517.755 ;
    END
  END RESET[176]

  PIN RESET[177]
    DIRECTION INPUT ;
    USE SIGNAL ;
    PORT
      LAYER Metal1 ;
        RECT 0 1526.085 2754.180 1526.335 ;
    END
  END RESET[177]

  PIN RESET[178]
    DIRECTION INPUT ;
    USE SIGNAL ;
    PORT
      LAYER Metal1 ;
        RECT 0 1534.665 2754.180 1534.915 ;
    END
  END RESET[178]

  PIN RESET[179]
    DIRECTION INPUT ;
    USE SIGNAL ;
    PORT
      LAYER Metal1 ;
        RECT 0 1543.245 2754.180 1543.495 ;
    END
  END RESET[179]

  PIN RESET[180]
    DIRECTION INPUT ;
    USE SIGNAL ;
    PORT
      LAYER Metal1 ;
        RECT 0 1551.825 2754.180 1552.075 ;
    END
  END RESET[180]

  PIN RESET[181]
    DIRECTION INPUT ;
    USE SIGNAL ;
    PORT
      LAYER Metal1 ;
        RECT 0 1560.405 2754.180 1560.655 ;
    END
  END RESET[181]

  PIN RESET[182]
    DIRECTION INPUT ;
    USE SIGNAL ;
    PORT
      LAYER Metal1 ;
        RECT 0 1568.985 2754.180 1569.235 ;
    END
  END RESET[182]

  PIN RESET[183]
    DIRECTION INPUT ;
    USE SIGNAL ;
    PORT
      LAYER Metal1 ;
        RECT 0 1577.565 2754.180 1577.815 ;
    END
  END RESET[183]

  PIN RESET[184]
    DIRECTION INPUT ;
    USE SIGNAL ;
    PORT
      LAYER Metal1 ;
        RECT 0 1586.145 2754.180 1586.395 ;
    END
  END RESET[184]

  PIN RESET[185]
    DIRECTION INPUT ;
    USE SIGNAL ;
    PORT
      LAYER Metal1 ;
        RECT 0 1594.725 2754.180 1594.975 ;
    END
  END RESET[185]

  PIN RESET[186]
    DIRECTION INPUT ;
    USE SIGNAL ;
    PORT
      LAYER Metal1 ;
        RECT 0 1603.305 2754.180 1603.555 ;
    END
  END RESET[186]

  PIN RESET[187]
    DIRECTION INPUT ;
    USE SIGNAL ;
    PORT
      LAYER Metal1 ;
        RECT 0 1611.885 2754.180 1612.135 ;
    END
  END RESET[187]

  PIN RESET[188]
    DIRECTION INPUT ;
    USE SIGNAL ;
    PORT
      LAYER Metal1 ;
        RECT 0 1620.465 2754.180 1620.715 ;
    END
  END RESET[188]

  PIN RESET[189]
    DIRECTION INPUT ;
    USE SIGNAL ;
    PORT
      LAYER Metal1 ;
        RECT 0 1629.045 2754.180 1629.295 ;
    END
  END RESET[189]

  PIN RESET[190]
    DIRECTION INPUT ;
    USE SIGNAL ;
    PORT
      LAYER Metal1 ;
        RECT 0 1637.625 2754.180 1637.875 ;
    END
  END RESET[190]

  PIN RESET[191]
    DIRECTION INPUT ;
    USE SIGNAL ;
    PORT
      LAYER Metal1 ;
        RECT 0 1646.205 2754.180 1646.455 ;
    END
  END RESET[191]

  PIN RESET[192]
    DIRECTION INPUT ;
    USE SIGNAL ;
    PORT
      LAYER Metal1 ;
        RECT 0 1654.785 2754.180 1655.035 ;
    END
  END RESET[192]

  PIN RESET[193]
    DIRECTION INPUT ;
    USE SIGNAL ;
    PORT
      LAYER Metal1 ;
        RECT 0 1663.365 2754.180 1663.615 ;
    END
  END RESET[193]

  PIN RESET[194]
    DIRECTION INPUT ;
    USE SIGNAL ;
    PORT
      LAYER Metal1 ;
        RECT 0 1671.945 2754.180 1672.195 ;
    END
  END RESET[194]

  PIN RESET[195]
    DIRECTION INPUT ;
    USE SIGNAL ;
    PORT
      LAYER Metal1 ;
        RECT 0 1680.525 2754.180 1680.775 ;
    END
  END RESET[195]

  PIN RESET[196]
    DIRECTION INPUT ;
    USE SIGNAL ;
    PORT
      LAYER Metal1 ;
        RECT 0 1689.105 2754.180 1689.355 ;
    END
  END RESET[196]

  PIN RESET[197]
    DIRECTION INPUT ;
    USE SIGNAL ;
    PORT
      LAYER Metal1 ;
        RECT 0 1697.685 2754.180 1697.935 ;
    END
  END RESET[197]

  PIN RESET[198]
    DIRECTION INPUT ;
    USE SIGNAL ;
    PORT
      LAYER Metal1 ;
        RECT 0 1706.265 2754.180 1706.515 ;
    END
  END RESET[198]

  PIN RESET[199]
    DIRECTION INPUT ;
    USE SIGNAL ;
    PORT
      LAYER Metal1 ;
        RECT 0 1714.845 2754.180 1715.095 ;
    END
  END RESET[199]

  PIN RESET[200]
    DIRECTION INPUT ;
    USE SIGNAL ;
    PORT
      LAYER Metal1 ;
        RECT 0 1723.425 2754.180 1723.675 ;
    END
  END RESET[200]

  PIN RESET[201]
    DIRECTION INPUT ;
    USE SIGNAL ;
    PORT
      LAYER Metal1 ;
        RECT 0 1732.005 2754.180 1732.255 ;
    END
  END RESET[201]

  PIN RESET[202]
    DIRECTION INPUT ;
    USE SIGNAL ;
    PORT
      LAYER Metal1 ;
        RECT 0 1740.585 2754.180 1740.835 ;
    END
  END RESET[202]

  PIN RESET[203]
    DIRECTION INPUT ;
    USE SIGNAL ;
    PORT
      LAYER Metal1 ;
        RECT 0 1749.165 2754.180 1749.415 ;
    END
  END RESET[203]

  PIN RESET[204]
    DIRECTION INPUT ;
    USE SIGNAL ;
    PORT
      LAYER Metal1 ;
        RECT 0 1757.745 2754.180 1757.995 ;
    END
  END RESET[204]

  PIN RESET[205]
    DIRECTION INPUT ;
    USE SIGNAL ;
    PORT
      LAYER Metal1 ;
        RECT 0 1766.325 2754.180 1766.575 ;
    END
  END RESET[205]

  PIN RESET[206]
    DIRECTION INPUT ;
    USE SIGNAL ;
    PORT
      LAYER Metal1 ;
        RECT 0 1774.905 2754.180 1775.155 ;
    END
  END RESET[206]

  PIN RESET[207]
    DIRECTION INPUT ;
    USE SIGNAL ;
    PORT
      LAYER Metal1 ;
        RECT 0 1783.485 2754.180 1783.735 ;
    END
  END RESET[207]

  PIN RESET[208]
    DIRECTION INPUT ;
    USE SIGNAL ;
    PORT
      LAYER Metal1 ;
        RECT 0 1792.065 2754.180 1792.315 ;
    END
  END RESET[208]

  PIN RESET[209]
    DIRECTION INPUT ;
    USE SIGNAL ;
    PORT
      LAYER Metal1 ;
        RECT 0 1800.645 2754.180 1800.895 ;
    END
  END RESET[209]

  PIN RESET[210]
    DIRECTION INPUT ;
    USE SIGNAL ;
    PORT
      LAYER Metal1 ;
        RECT 0 1809.225 2754.180 1809.475 ;
    END
  END RESET[210]

  PIN RESET[211]
    DIRECTION INPUT ;
    USE SIGNAL ;
    PORT
      LAYER Metal1 ;
        RECT 0 1817.805 2754.180 1818.055 ;
    END
  END RESET[211]

  PIN RESET[212]
    DIRECTION INPUT ;
    USE SIGNAL ;
    PORT
      LAYER Metal1 ;
        RECT 0 1826.385 2754.180 1826.635 ;
    END
  END RESET[212]

  PIN RESET[213]
    DIRECTION INPUT ;
    USE SIGNAL ;
    PORT
      LAYER Metal1 ;
        RECT 0 1834.965 2754.180 1835.215 ;
    END
  END RESET[213]

  PIN RESET[214]
    DIRECTION INPUT ;
    USE SIGNAL ;
    PORT
      LAYER Metal1 ;
        RECT 0 1843.545 2754.180 1843.795 ;
    END
  END RESET[214]

  PIN RESET[215]
    DIRECTION INPUT ;
    USE SIGNAL ;
    PORT
      LAYER Metal1 ;
        RECT 0 1852.125 2754.180 1852.375 ;
    END
  END RESET[215]

  PIN RESET[216]
    DIRECTION INPUT ;
    USE SIGNAL ;
    PORT
      LAYER Metal1 ;
        RECT 0 1860.705 2754.180 1860.955 ;
    END
  END RESET[216]

  PIN RESET[217]
    DIRECTION INPUT ;
    USE SIGNAL ;
    PORT
      LAYER Metal1 ;
        RECT 0 1869.285 2754.180 1869.535 ;
    END
  END RESET[217]

  PIN RESET[218]
    DIRECTION INPUT ;
    USE SIGNAL ;
    PORT
      LAYER Metal1 ;
        RECT 0 1877.865 2754.180 1878.115 ;
    END
  END RESET[218]

  PIN RESET[219]
    DIRECTION INPUT ;
    USE SIGNAL ;
    PORT
      LAYER Metal1 ;
        RECT 0 1886.445 2754.180 1886.695 ;
    END
  END RESET[219]

  PIN RESET[220]
    DIRECTION INPUT ;
    USE SIGNAL ;
    PORT
      LAYER Metal1 ;
        RECT 0 1895.025 2754.180 1895.275 ;
    END
  END RESET[220]

  PIN RESET[221]
    DIRECTION INPUT ;
    USE SIGNAL ;
    PORT
      LAYER Metal1 ;
        RECT 0 1903.605 2754.180 1903.855 ;
    END
  END RESET[221]

  PIN RESET[222]
    DIRECTION INPUT ;
    USE SIGNAL ;
    PORT
      LAYER Metal1 ;
        RECT 0 1912.185 2754.180 1912.435 ;
    END
  END RESET[222]

  PIN RESET[223]
    DIRECTION INPUT ;
    USE SIGNAL ;
    PORT
      LAYER Metal1 ;
        RECT 0 1920.765 2754.180 1921.015 ;
    END
  END RESET[223]

  PIN RESET[224]
    DIRECTION INPUT ;
    USE SIGNAL ;
    PORT
      LAYER Metal1 ;
        RECT 0 1929.345 2754.180 1929.595 ;
    END
  END RESET[224]

  PIN RESET[225]
    DIRECTION INPUT ;
    USE SIGNAL ;
    PORT
      LAYER Metal1 ;
        RECT 0 1937.925 2754.180 1938.175 ;
    END
  END RESET[225]

  PIN RESET[226]
    DIRECTION INPUT ;
    USE SIGNAL ;
    PORT
      LAYER Metal1 ;
        RECT 0 1946.505 2754.180 1946.755 ;
    END
  END RESET[226]

  PIN RESET[227]
    DIRECTION INPUT ;
    USE SIGNAL ;
    PORT
      LAYER Metal1 ;
        RECT 0 1955.085 2754.180 1955.335 ;
    END
  END RESET[227]

  PIN RESET[228]
    DIRECTION INPUT ;
    USE SIGNAL ;
    PORT
      LAYER Metal1 ;
        RECT 0 1963.665 2754.180 1963.915 ;
    END
  END RESET[228]

  PIN RESET[229]
    DIRECTION INPUT ;
    USE SIGNAL ;
    PORT
      LAYER Metal1 ;
        RECT 0 1972.245 2754.180 1972.495 ;
    END
  END RESET[229]

  PIN RESET[230]
    DIRECTION INPUT ;
    USE SIGNAL ;
    PORT
      LAYER Metal1 ;
        RECT 0 1980.825 2754.180 1981.075 ;
    END
  END RESET[230]

  PIN RESET[231]
    DIRECTION INPUT ;
    USE SIGNAL ;
    PORT
      LAYER Metal1 ;
        RECT 0 1989.405 2754.180 1989.655 ;
    END
  END RESET[231]

  PIN RESET[232]
    DIRECTION INPUT ;
    USE SIGNAL ;
    PORT
      LAYER Metal1 ;
        RECT 0 1997.985 2754.180 1998.235 ;
    END
  END RESET[232]

  PIN RESET[233]
    DIRECTION INPUT ;
    USE SIGNAL ;
    PORT
      LAYER Metal1 ;
        RECT 0 2006.565 2754.180 2006.815 ;
    END
  END RESET[233]

  PIN RESET[234]
    DIRECTION INPUT ;
    USE SIGNAL ;
    PORT
      LAYER Metal1 ;
        RECT 0 2015.145 2754.180 2015.395 ;
    END
  END RESET[234]

  PIN RESET[235]
    DIRECTION INPUT ;
    USE SIGNAL ;
    PORT
      LAYER Metal1 ;
        RECT 0 2023.725 2754.180 2023.975 ;
    END
  END RESET[235]

  PIN RESET[236]
    DIRECTION INPUT ;
    USE SIGNAL ;
    PORT
      LAYER Metal1 ;
        RECT 0 2032.305 2754.180 2032.555 ;
    END
  END RESET[236]

  PIN RESET[237]
    DIRECTION INPUT ;
    USE SIGNAL ;
    PORT
      LAYER Metal1 ;
        RECT 0 2040.885 2754.180 2041.135 ;
    END
  END RESET[237]

  PIN RESET[238]
    DIRECTION INPUT ;
    USE SIGNAL ;
    PORT
      LAYER Metal1 ;
        RECT 0 2049.465 2754.180 2049.715 ;
    END
  END RESET[238]

  PIN RESET[239]
    DIRECTION INPUT ;
    USE SIGNAL ;
    PORT
      LAYER Metal1 ;
        RECT 0 2058.045 2754.180 2058.295 ;
    END
  END RESET[239]

  PIN VDD[0]
    DIRECTION INOUT ;
    USE POWER ;
    PORT
      LAYER Metal1 ;
        RECT 0 8.025 2754.180 8.275 ;
    END
  END VDD[0]

  PIN VDD[1]
    DIRECTION INOUT ;
    USE POWER ;
    PORT
      LAYER Metal1 ;
        RECT 0 16.605 2754.180 16.855 ;
    END
  END VDD[1]

  PIN VDD[2]
    DIRECTION INOUT ;
    USE POWER ;
    PORT
      LAYER Metal1 ;
        RECT 0 25.185 2754.180 25.435 ;
    END
  END VDD[2]

  PIN VDD[3]
    DIRECTION INOUT ;
    USE POWER ;
    PORT
      LAYER Metal1 ;
        RECT 0 33.765 2754.180 34.015 ;
    END
  END VDD[3]

  PIN VDD[4]
    DIRECTION INOUT ;
    USE POWER ;
    PORT
      LAYER Metal1 ;
        RECT 0 42.345 2754.180 42.595 ;
    END
  END VDD[4]

  PIN VDD[5]
    DIRECTION INOUT ;
    USE POWER ;
    PORT
      LAYER Metal1 ;
        RECT 0 50.925 2754.180 51.175 ;
    END
  END VDD[5]

  PIN VDD[6]
    DIRECTION INOUT ;
    USE POWER ;
    PORT
      LAYER Metal1 ;
        RECT 0 59.505 2754.180 59.755 ;
    END
  END VDD[6]

  PIN VDD[7]
    DIRECTION INOUT ;
    USE POWER ;
    PORT
      LAYER Metal1 ;
        RECT 0 68.085 2754.180 68.335 ;
    END
  END VDD[7]

  PIN VDD[8]
    DIRECTION INOUT ;
    USE POWER ;
    PORT
      LAYER Metal1 ;
        RECT 0 76.665 2754.180 76.915 ;
    END
  END VDD[8]

  PIN VDD[9]
    DIRECTION INOUT ;
    USE POWER ;
    PORT
      LAYER Metal1 ;
        RECT 0 85.245 2754.180 85.495 ;
    END
  END VDD[9]

  PIN VDD[10]
    DIRECTION INOUT ;
    USE POWER ;
    PORT
      LAYER Metal1 ;
        RECT 0 93.825 2754.180 94.075 ;
    END
  END VDD[10]

  PIN VDD[11]
    DIRECTION INOUT ;
    USE POWER ;
    PORT
      LAYER Metal1 ;
        RECT 0 102.405 2754.180 102.655 ;
    END
  END VDD[11]

  PIN VDD[12]
    DIRECTION INOUT ;
    USE POWER ;
    PORT
      LAYER Metal1 ;
        RECT 0 110.985 2754.180 111.235 ;
    END
  END VDD[12]

  PIN VDD[13]
    DIRECTION INOUT ;
    USE POWER ;
    PORT
      LAYER Metal1 ;
        RECT 0 119.565 2754.180 119.815 ;
    END
  END VDD[13]

  PIN VDD[14]
    DIRECTION INOUT ;
    USE POWER ;
    PORT
      LAYER Metal1 ;
        RECT 0 128.145 2754.180 128.395 ;
    END
  END VDD[14]

  PIN VDD[15]
    DIRECTION INOUT ;
    USE POWER ;
    PORT
      LAYER Metal1 ;
        RECT 0 136.725 2754.180 136.975 ;
    END
  END VDD[15]

  PIN VDD[16]
    DIRECTION INOUT ;
    USE POWER ;
    PORT
      LAYER Metal1 ;
        RECT 0 145.305 2754.180 145.555 ;
    END
  END VDD[16]

  PIN VDD[17]
    DIRECTION INOUT ;
    USE POWER ;
    PORT
      LAYER Metal1 ;
        RECT 0 153.885 2754.180 154.135 ;
    END
  END VDD[17]

  PIN VDD[18]
    DIRECTION INOUT ;
    USE POWER ;
    PORT
      LAYER Metal1 ;
        RECT 0 162.465 2754.180 162.715 ;
    END
  END VDD[18]

  PIN VDD[19]
    DIRECTION INOUT ;
    USE POWER ;
    PORT
      LAYER Metal1 ;
        RECT 0 171.045 2754.180 171.295 ;
    END
  END VDD[19]

  PIN VDD[20]
    DIRECTION INOUT ;
    USE POWER ;
    PORT
      LAYER Metal1 ;
        RECT 0 179.625 2754.180 179.875 ;
    END
  END VDD[20]

  PIN VDD[21]
    DIRECTION INOUT ;
    USE POWER ;
    PORT
      LAYER Metal1 ;
        RECT 0 188.205 2754.180 188.455 ;
    END
  END VDD[21]

  PIN VDD[22]
    DIRECTION INOUT ;
    USE POWER ;
    PORT
      LAYER Metal1 ;
        RECT 0 196.785 2754.180 197.035 ;
    END
  END VDD[22]

  PIN VDD[23]
    DIRECTION INOUT ;
    USE POWER ;
    PORT
      LAYER Metal1 ;
        RECT 0 205.365 2754.180 205.615 ;
    END
  END VDD[23]

  PIN VDD[24]
    DIRECTION INOUT ;
    USE POWER ;
    PORT
      LAYER Metal1 ;
        RECT 0 213.945 2754.180 214.195 ;
    END
  END VDD[24]

  PIN VDD[25]
    DIRECTION INOUT ;
    USE POWER ;
    PORT
      LAYER Metal1 ;
        RECT 0 222.525 2754.180 222.775 ;
    END
  END VDD[25]

  PIN VDD[26]
    DIRECTION INOUT ;
    USE POWER ;
    PORT
      LAYER Metal1 ;
        RECT 0 231.105 2754.180 231.355 ;
    END
  END VDD[26]

  PIN VDD[27]
    DIRECTION INOUT ;
    USE POWER ;
    PORT
      LAYER Metal1 ;
        RECT 0 239.685 2754.180 239.935 ;
    END
  END VDD[27]

  PIN VDD[28]
    DIRECTION INOUT ;
    USE POWER ;
    PORT
      LAYER Metal1 ;
        RECT 0 248.265 2754.180 248.515 ;
    END
  END VDD[28]

  PIN VDD[29]
    DIRECTION INOUT ;
    USE POWER ;
    PORT
      LAYER Metal1 ;
        RECT 0 256.845 2754.180 257.095 ;
    END
  END VDD[29]

  PIN VDD[30]
    DIRECTION INOUT ;
    USE POWER ;
    PORT
      LAYER Metal1 ;
        RECT 0 265.425 2754.180 265.675 ;
    END
  END VDD[30]

  PIN VDD[31]
    DIRECTION INOUT ;
    USE POWER ;
    PORT
      LAYER Metal1 ;
        RECT 0 274.005 2754.180 274.255 ;
    END
  END VDD[31]

  PIN VDD[32]
    DIRECTION INOUT ;
    USE POWER ;
    PORT
      LAYER Metal1 ;
        RECT 0 282.585 2754.180 282.835 ;
    END
  END VDD[32]

  PIN VDD[33]
    DIRECTION INOUT ;
    USE POWER ;
    PORT
      LAYER Metal1 ;
        RECT 0 291.165 2754.180 291.415 ;
    END
  END VDD[33]

  PIN VDD[34]
    DIRECTION INOUT ;
    USE POWER ;
    PORT
      LAYER Metal1 ;
        RECT 0 299.745 2754.180 299.995 ;
    END
  END VDD[34]

  PIN VDD[35]
    DIRECTION INOUT ;
    USE POWER ;
    PORT
      LAYER Metal1 ;
        RECT 0 308.325 2754.180 308.575 ;
    END
  END VDD[35]

  PIN VDD[36]
    DIRECTION INOUT ;
    USE POWER ;
    PORT
      LAYER Metal1 ;
        RECT 0 316.905 2754.180 317.155 ;
    END
  END VDD[36]

  PIN VDD[37]
    DIRECTION INOUT ;
    USE POWER ;
    PORT
      LAYER Metal1 ;
        RECT 0 325.485 2754.180 325.735 ;
    END
  END VDD[37]

  PIN VDD[38]
    DIRECTION INOUT ;
    USE POWER ;
    PORT
      LAYER Metal1 ;
        RECT 0 334.065 2754.180 334.315 ;
    END
  END VDD[38]

  PIN VDD[39]
    DIRECTION INOUT ;
    USE POWER ;
    PORT
      LAYER Metal1 ;
        RECT 0 342.645 2754.180 342.895 ;
    END
  END VDD[39]

  PIN VDD[40]
    DIRECTION INOUT ;
    USE POWER ;
    PORT
      LAYER Metal1 ;
        RECT 0 351.225 2754.180 351.475 ;
    END
  END VDD[40]

  PIN VDD[41]
    DIRECTION INOUT ;
    USE POWER ;
    PORT
      LAYER Metal1 ;
        RECT 0 359.805 2754.180 360.055 ;
    END
  END VDD[41]

  PIN VDD[42]
    DIRECTION INOUT ;
    USE POWER ;
    PORT
      LAYER Metal1 ;
        RECT 0 368.385 2754.180 368.635 ;
    END
  END VDD[42]

  PIN VDD[43]
    DIRECTION INOUT ;
    USE POWER ;
    PORT
      LAYER Metal1 ;
        RECT 0 376.965 2754.180 377.215 ;
    END
  END VDD[43]

  PIN VDD[44]
    DIRECTION INOUT ;
    USE POWER ;
    PORT
      LAYER Metal1 ;
        RECT 0 385.545 2754.180 385.795 ;
    END
  END VDD[44]

  PIN VDD[45]
    DIRECTION INOUT ;
    USE POWER ;
    PORT
      LAYER Metal1 ;
        RECT 0 394.125 2754.180 394.375 ;
    END
  END VDD[45]

  PIN VDD[46]
    DIRECTION INOUT ;
    USE POWER ;
    PORT
      LAYER Metal1 ;
        RECT 0 402.705 2754.180 402.955 ;
    END
  END VDD[46]

  PIN VDD[47]
    DIRECTION INOUT ;
    USE POWER ;
    PORT
      LAYER Metal1 ;
        RECT 0 411.285 2754.180 411.535 ;
    END
  END VDD[47]

  PIN VDD[48]
    DIRECTION INOUT ;
    USE POWER ;
    PORT
      LAYER Metal1 ;
        RECT 0 419.865 2754.180 420.115 ;
    END
  END VDD[48]

  PIN VDD[49]
    DIRECTION INOUT ;
    USE POWER ;
    PORT
      LAYER Metal1 ;
        RECT 0 428.445 2754.180 428.695 ;
    END
  END VDD[49]

  PIN VDD[50]
    DIRECTION INOUT ;
    USE POWER ;
    PORT
      LAYER Metal1 ;
        RECT 0 437.025 2754.180 437.275 ;
    END
  END VDD[50]

  PIN VDD[51]
    DIRECTION INOUT ;
    USE POWER ;
    PORT
      LAYER Metal1 ;
        RECT 0 445.605 2754.180 445.855 ;
    END
  END VDD[51]

  PIN VDD[52]
    DIRECTION INOUT ;
    USE POWER ;
    PORT
      LAYER Metal1 ;
        RECT 0 454.185 2754.180 454.435 ;
    END
  END VDD[52]

  PIN VDD[53]
    DIRECTION INOUT ;
    USE POWER ;
    PORT
      LAYER Metal1 ;
        RECT 0 462.765 2754.180 463.015 ;
    END
  END VDD[53]

  PIN VDD[54]
    DIRECTION INOUT ;
    USE POWER ;
    PORT
      LAYER Metal1 ;
        RECT 0 471.345 2754.180 471.595 ;
    END
  END VDD[54]

  PIN VDD[55]
    DIRECTION INOUT ;
    USE POWER ;
    PORT
      LAYER Metal1 ;
        RECT 0 479.925 2754.180 480.175 ;
    END
  END VDD[55]

  PIN VDD[56]
    DIRECTION INOUT ;
    USE POWER ;
    PORT
      LAYER Metal1 ;
        RECT 0 488.505 2754.180 488.755 ;
    END
  END VDD[56]

  PIN VDD[57]
    DIRECTION INOUT ;
    USE POWER ;
    PORT
      LAYER Metal1 ;
        RECT 0 497.085 2754.180 497.335 ;
    END
  END VDD[57]

  PIN VDD[58]
    DIRECTION INOUT ;
    USE POWER ;
    PORT
      LAYER Metal1 ;
        RECT 0 505.665 2754.180 505.915 ;
    END
  END VDD[58]

  PIN VDD[59]
    DIRECTION INOUT ;
    USE POWER ;
    PORT
      LAYER Metal1 ;
        RECT 0 514.245 2754.180 514.495 ;
    END
  END VDD[59]

  PIN VDD[60]
    DIRECTION INOUT ;
    USE POWER ;
    PORT
      LAYER Metal1 ;
        RECT 0 522.825 2754.180 523.075 ;
    END
  END VDD[60]

  PIN VDD[61]
    DIRECTION INOUT ;
    USE POWER ;
    PORT
      LAYER Metal1 ;
        RECT 0 531.405 2754.180 531.655 ;
    END
  END VDD[61]

  PIN VDD[62]
    DIRECTION INOUT ;
    USE POWER ;
    PORT
      LAYER Metal1 ;
        RECT 0 539.985 2754.180 540.235 ;
    END
  END VDD[62]

  PIN VDD[63]
    DIRECTION INOUT ;
    USE POWER ;
    PORT
      LAYER Metal1 ;
        RECT 0 548.565 2754.180 548.815 ;
    END
  END VDD[63]

  PIN VDD[64]
    DIRECTION INOUT ;
    USE POWER ;
    PORT
      LAYER Metal1 ;
        RECT 0 557.145 2754.180 557.395 ;
    END
  END VDD[64]

  PIN VDD[65]
    DIRECTION INOUT ;
    USE POWER ;
    PORT
      LAYER Metal1 ;
        RECT 0 565.725 2754.180 565.975 ;
    END
  END VDD[65]

  PIN VDD[66]
    DIRECTION INOUT ;
    USE POWER ;
    PORT
      LAYER Metal1 ;
        RECT 0 574.305 2754.180 574.555 ;
    END
  END VDD[66]

  PIN VDD[67]
    DIRECTION INOUT ;
    USE POWER ;
    PORT
      LAYER Metal1 ;
        RECT 0 582.885 2754.180 583.135 ;
    END
  END VDD[67]

  PIN VDD[68]
    DIRECTION INOUT ;
    USE POWER ;
    PORT
      LAYER Metal1 ;
        RECT 0 591.465 2754.180 591.715 ;
    END
  END VDD[68]

  PIN VDD[69]
    DIRECTION INOUT ;
    USE POWER ;
    PORT
      LAYER Metal1 ;
        RECT 0 600.045 2754.180 600.295 ;
    END
  END VDD[69]

  PIN VDD[70]
    DIRECTION INOUT ;
    USE POWER ;
    PORT
      LAYER Metal1 ;
        RECT 0 608.625 2754.180 608.875 ;
    END
  END VDD[70]

  PIN VDD[71]
    DIRECTION INOUT ;
    USE POWER ;
    PORT
      LAYER Metal1 ;
        RECT 0 617.205 2754.180 617.455 ;
    END
  END VDD[71]

  PIN VDD[72]
    DIRECTION INOUT ;
    USE POWER ;
    PORT
      LAYER Metal1 ;
        RECT 0 625.785 2754.180 626.035 ;
    END
  END VDD[72]

  PIN VDD[73]
    DIRECTION INOUT ;
    USE POWER ;
    PORT
      LAYER Metal1 ;
        RECT 0 634.365 2754.180 634.615 ;
    END
  END VDD[73]

  PIN VDD[74]
    DIRECTION INOUT ;
    USE POWER ;
    PORT
      LAYER Metal1 ;
        RECT 0 642.945 2754.180 643.195 ;
    END
  END VDD[74]

  PIN VDD[75]
    DIRECTION INOUT ;
    USE POWER ;
    PORT
      LAYER Metal1 ;
        RECT 0 651.525 2754.180 651.775 ;
    END
  END VDD[75]

  PIN VDD[76]
    DIRECTION INOUT ;
    USE POWER ;
    PORT
      LAYER Metal1 ;
        RECT 0 660.105 2754.180 660.355 ;
    END
  END VDD[76]

  PIN VDD[77]
    DIRECTION INOUT ;
    USE POWER ;
    PORT
      LAYER Metal1 ;
        RECT 0 668.685 2754.180 668.935 ;
    END
  END VDD[77]

  PIN VDD[78]
    DIRECTION INOUT ;
    USE POWER ;
    PORT
      LAYER Metal1 ;
        RECT 0 677.265 2754.180 677.515 ;
    END
  END VDD[78]

  PIN VDD[79]
    DIRECTION INOUT ;
    USE POWER ;
    PORT
      LAYER Metal1 ;
        RECT 0 685.845 2754.180 686.095 ;
    END
  END VDD[79]

  PIN VDD[80]
    DIRECTION INOUT ;
    USE POWER ;
    PORT
      LAYER Metal1 ;
        RECT 0 694.425 2754.180 694.675 ;
    END
  END VDD[80]

  PIN VDD[81]
    DIRECTION INOUT ;
    USE POWER ;
    PORT
      LAYER Metal1 ;
        RECT 0 703.005 2754.180 703.255 ;
    END
  END VDD[81]

  PIN VDD[82]
    DIRECTION INOUT ;
    USE POWER ;
    PORT
      LAYER Metal1 ;
        RECT 0 711.585 2754.180 711.835 ;
    END
  END VDD[82]

  PIN VDD[83]
    DIRECTION INOUT ;
    USE POWER ;
    PORT
      LAYER Metal1 ;
        RECT 0 720.165 2754.180 720.415 ;
    END
  END VDD[83]

  PIN VDD[84]
    DIRECTION INOUT ;
    USE POWER ;
    PORT
      LAYER Metal1 ;
        RECT 0 728.745 2754.180 728.995 ;
    END
  END VDD[84]

  PIN VDD[85]
    DIRECTION INOUT ;
    USE POWER ;
    PORT
      LAYER Metal1 ;
        RECT 0 737.325 2754.180 737.575 ;
    END
  END VDD[85]

  PIN VDD[86]
    DIRECTION INOUT ;
    USE POWER ;
    PORT
      LAYER Metal1 ;
        RECT 0 745.905 2754.180 746.155 ;
    END
  END VDD[86]

  PIN VDD[87]
    DIRECTION INOUT ;
    USE POWER ;
    PORT
      LAYER Metal1 ;
        RECT 0 754.485 2754.180 754.735 ;
    END
  END VDD[87]

  PIN VDD[88]
    DIRECTION INOUT ;
    USE POWER ;
    PORT
      LAYER Metal1 ;
        RECT 0 763.065 2754.180 763.315 ;
    END
  END VDD[88]

  PIN VDD[89]
    DIRECTION INOUT ;
    USE POWER ;
    PORT
      LAYER Metal1 ;
        RECT 0 771.645 2754.180 771.895 ;
    END
  END VDD[89]

  PIN VDD[90]
    DIRECTION INOUT ;
    USE POWER ;
    PORT
      LAYER Metal1 ;
        RECT 0 780.225 2754.180 780.475 ;
    END
  END VDD[90]

  PIN VDD[91]
    DIRECTION INOUT ;
    USE POWER ;
    PORT
      LAYER Metal1 ;
        RECT 0 788.805 2754.180 789.055 ;
    END
  END VDD[91]

  PIN VDD[92]
    DIRECTION INOUT ;
    USE POWER ;
    PORT
      LAYER Metal1 ;
        RECT 0 797.385 2754.180 797.635 ;
    END
  END VDD[92]

  PIN VDD[93]
    DIRECTION INOUT ;
    USE POWER ;
    PORT
      LAYER Metal1 ;
        RECT 0 805.965 2754.180 806.215 ;
    END
  END VDD[93]

  PIN VDD[94]
    DIRECTION INOUT ;
    USE POWER ;
    PORT
      LAYER Metal1 ;
        RECT 0 814.545 2754.180 814.795 ;
    END
  END VDD[94]

  PIN VDD[95]
    DIRECTION INOUT ;
    USE POWER ;
    PORT
      LAYER Metal1 ;
        RECT 0 823.125 2754.180 823.375 ;
    END
  END VDD[95]

  PIN VDD[96]
    DIRECTION INOUT ;
    USE POWER ;
    PORT
      LAYER Metal1 ;
        RECT 0 831.705 2754.180 831.955 ;
    END
  END VDD[96]

  PIN VDD[97]
    DIRECTION INOUT ;
    USE POWER ;
    PORT
      LAYER Metal1 ;
        RECT 0 840.285 2754.180 840.535 ;
    END
  END VDD[97]

  PIN VDD[98]
    DIRECTION INOUT ;
    USE POWER ;
    PORT
      LAYER Metal1 ;
        RECT 0 848.865 2754.180 849.115 ;
    END
  END VDD[98]

  PIN VDD[99]
    DIRECTION INOUT ;
    USE POWER ;
    PORT
      LAYER Metal1 ;
        RECT 0 857.445 2754.180 857.695 ;
    END
  END VDD[99]

  PIN VDD[100]
    DIRECTION INOUT ;
    USE POWER ;
    PORT
      LAYER Metal1 ;
        RECT 0 866.025 2754.180 866.275 ;
    END
  END VDD[100]

  PIN VDD[101]
    DIRECTION INOUT ;
    USE POWER ;
    PORT
      LAYER Metal1 ;
        RECT 0 874.605 2754.180 874.855 ;
    END
  END VDD[101]

  PIN VDD[102]
    DIRECTION INOUT ;
    USE POWER ;
    PORT
      LAYER Metal1 ;
        RECT 0 883.185 2754.180 883.435 ;
    END
  END VDD[102]

  PIN VDD[103]
    DIRECTION INOUT ;
    USE POWER ;
    PORT
      LAYER Metal1 ;
        RECT 0 891.765 2754.180 892.015 ;
    END
  END VDD[103]

  PIN VDD[104]
    DIRECTION INOUT ;
    USE POWER ;
    PORT
      LAYER Metal1 ;
        RECT 0 900.345 2754.180 900.595 ;
    END
  END VDD[104]

  PIN VDD[105]
    DIRECTION INOUT ;
    USE POWER ;
    PORT
      LAYER Metal1 ;
        RECT 0 908.925 2754.180 909.175 ;
    END
  END VDD[105]

  PIN VDD[106]
    DIRECTION INOUT ;
    USE POWER ;
    PORT
      LAYER Metal1 ;
        RECT 0 917.505 2754.180 917.755 ;
    END
  END VDD[106]

  PIN VDD[107]
    DIRECTION INOUT ;
    USE POWER ;
    PORT
      LAYER Metal1 ;
        RECT 0 926.085 2754.180 926.335 ;
    END
  END VDD[107]

  PIN VDD[108]
    DIRECTION INOUT ;
    USE POWER ;
    PORT
      LAYER Metal1 ;
        RECT 0 934.665 2754.180 934.915 ;
    END
  END VDD[108]

  PIN VDD[109]
    DIRECTION INOUT ;
    USE POWER ;
    PORT
      LAYER Metal1 ;
        RECT 0 943.245 2754.180 943.495 ;
    END
  END VDD[109]

  PIN VDD[110]
    DIRECTION INOUT ;
    USE POWER ;
    PORT
      LAYER Metal1 ;
        RECT 0 951.825 2754.180 952.075 ;
    END
  END VDD[110]

  PIN VDD[111]
    DIRECTION INOUT ;
    USE POWER ;
    PORT
      LAYER Metal1 ;
        RECT 0 960.405 2754.180 960.655 ;
    END
  END VDD[111]

  PIN VDD[112]
    DIRECTION INOUT ;
    USE POWER ;
    PORT
      LAYER Metal1 ;
        RECT 0 968.985 2754.180 969.235 ;
    END
  END VDD[112]

  PIN VDD[113]
    DIRECTION INOUT ;
    USE POWER ;
    PORT
      LAYER Metal1 ;
        RECT 0 977.565 2754.180 977.815 ;
    END
  END VDD[113]

  PIN VDD[114]
    DIRECTION INOUT ;
    USE POWER ;
    PORT
      LAYER Metal1 ;
        RECT 0 986.145 2754.180 986.395 ;
    END
  END VDD[114]

  PIN VDD[115]
    DIRECTION INOUT ;
    USE POWER ;
    PORT
      LAYER Metal1 ;
        RECT 0 994.725 2754.180 994.975 ;
    END
  END VDD[115]

  PIN VDD[116]
    DIRECTION INOUT ;
    USE POWER ;
    PORT
      LAYER Metal1 ;
        RECT 0 1003.305 2754.180 1003.555 ;
    END
  END VDD[116]

  PIN VDD[117]
    DIRECTION INOUT ;
    USE POWER ;
    PORT
      LAYER Metal1 ;
        RECT 0 1011.885 2754.180 1012.135 ;
    END
  END VDD[117]

  PIN VDD[118]
    DIRECTION INOUT ;
    USE POWER ;
    PORT
      LAYER Metal1 ;
        RECT 0 1020.465 2754.180 1020.715 ;
    END
  END VDD[118]

  PIN VDD[119]
    DIRECTION INOUT ;
    USE POWER ;
    PORT
      LAYER Metal1 ;
        RECT 0 1029.045 2754.180 1029.295 ;
    END
  END VDD[119]

  PIN VDD[120]
    DIRECTION INOUT ;
    USE POWER ;
    PORT
      LAYER Metal1 ;
        RECT 0 1037.625 2754.180 1037.875 ;
    END
  END VDD[120]

  PIN VDD[121]
    DIRECTION INOUT ;
    USE POWER ;
    PORT
      LAYER Metal1 ;
        RECT 0 1046.205 2754.180 1046.455 ;
    END
  END VDD[121]

  PIN VDD[122]
    DIRECTION INOUT ;
    USE POWER ;
    PORT
      LAYER Metal1 ;
        RECT 0 1054.785 2754.180 1055.035 ;
    END
  END VDD[122]

  PIN VDD[123]
    DIRECTION INOUT ;
    USE POWER ;
    PORT
      LAYER Metal1 ;
        RECT 0 1063.365 2754.180 1063.615 ;
    END
  END VDD[123]

  PIN VDD[124]
    DIRECTION INOUT ;
    USE POWER ;
    PORT
      LAYER Metal1 ;
        RECT 0 1071.945 2754.180 1072.195 ;
    END
  END VDD[124]

  PIN VDD[125]
    DIRECTION INOUT ;
    USE POWER ;
    PORT
      LAYER Metal1 ;
        RECT 0 1080.525 2754.180 1080.775 ;
    END
  END VDD[125]

  PIN VDD[126]
    DIRECTION INOUT ;
    USE POWER ;
    PORT
      LAYER Metal1 ;
        RECT 0 1089.105 2754.180 1089.355 ;
    END
  END VDD[126]

  PIN VDD[127]
    DIRECTION INOUT ;
    USE POWER ;
    PORT
      LAYER Metal1 ;
        RECT 0 1097.685 2754.180 1097.935 ;
    END
  END VDD[127]

  PIN VDD[128]
    DIRECTION INOUT ;
    USE POWER ;
    PORT
      LAYER Metal1 ;
        RECT 0 1106.265 2754.180 1106.515 ;
    END
  END VDD[128]

  PIN VDD[129]
    DIRECTION INOUT ;
    USE POWER ;
    PORT
      LAYER Metal1 ;
        RECT 0 1114.845 2754.180 1115.095 ;
    END
  END VDD[129]

  PIN VDD[130]
    DIRECTION INOUT ;
    USE POWER ;
    PORT
      LAYER Metal1 ;
        RECT 0 1123.425 2754.180 1123.675 ;
    END
  END VDD[130]

  PIN VDD[131]
    DIRECTION INOUT ;
    USE POWER ;
    PORT
      LAYER Metal1 ;
        RECT 0 1132.005 2754.180 1132.255 ;
    END
  END VDD[131]

  PIN VDD[132]
    DIRECTION INOUT ;
    USE POWER ;
    PORT
      LAYER Metal1 ;
        RECT 0 1140.585 2754.180 1140.835 ;
    END
  END VDD[132]

  PIN VDD[133]
    DIRECTION INOUT ;
    USE POWER ;
    PORT
      LAYER Metal1 ;
        RECT 0 1149.165 2754.180 1149.415 ;
    END
  END VDD[133]

  PIN VDD[134]
    DIRECTION INOUT ;
    USE POWER ;
    PORT
      LAYER Metal1 ;
        RECT 0 1157.745 2754.180 1157.995 ;
    END
  END VDD[134]

  PIN VDD[135]
    DIRECTION INOUT ;
    USE POWER ;
    PORT
      LAYER Metal1 ;
        RECT 0 1166.325 2754.180 1166.575 ;
    END
  END VDD[135]

  PIN VDD[136]
    DIRECTION INOUT ;
    USE POWER ;
    PORT
      LAYER Metal1 ;
        RECT 0 1174.905 2754.180 1175.155 ;
    END
  END VDD[136]

  PIN VDD[137]
    DIRECTION INOUT ;
    USE POWER ;
    PORT
      LAYER Metal1 ;
        RECT 0 1183.485 2754.180 1183.735 ;
    END
  END VDD[137]

  PIN VDD[138]
    DIRECTION INOUT ;
    USE POWER ;
    PORT
      LAYER Metal1 ;
        RECT 0 1192.065 2754.180 1192.315 ;
    END
  END VDD[138]

  PIN VDD[139]
    DIRECTION INOUT ;
    USE POWER ;
    PORT
      LAYER Metal1 ;
        RECT 0 1200.645 2754.180 1200.895 ;
    END
  END VDD[139]

  PIN VDD[140]
    DIRECTION INOUT ;
    USE POWER ;
    PORT
      LAYER Metal1 ;
        RECT 0 1209.225 2754.180 1209.475 ;
    END
  END VDD[140]

  PIN VDD[141]
    DIRECTION INOUT ;
    USE POWER ;
    PORT
      LAYER Metal1 ;
        RECT 0 1217.805 2754.180 1218.055 ;
    END
  END VDD[141]

  PIN VDD[142]
    DIRECTION INOUT ;
    USE POWER ;
    PORT
      LAYER Metal1 ;
        RECT 0 1226.385 2754.180 1226.635 ;
    END
  END VDD[142]

  PIN VDD[143]
    DIRECTION INOUT ;
    USE POWER ;
    PORT
      LAYER Metal1 ;
        RECT 0 1234.965 2754.180 1235.215 ;
    END
  END VDD[143]

  PIN VDD[144]
    DIRECTION INOUT ;
    USE POWER ;
    PORT
      LAYER Metal1 ;
        RECT 0 1243.545 2754.180 1243.795 ;
    END
  END VDD[144]

  PIN VDD[145]
    DIRECTION INOUT ;
    USE POWER ;
    PORT
      LAYER Metal1 ;
        RECT 0 1252.125 2754.180 1252.375 ;
    END
  END VDD[145]

  PIN VDD[146]
    DIRECTION INOUT ;
    USE POWER ;
    PORT
      LAYER Metal1 ;
        RECT 0 1260.705 2754.180 1260.955 ;
    END
  END VDD[146]

  PIN VDD[147]
    DIRECTION INOUT ;
    USE POWER ;
    PORT
      LAYER Metal1 ;
        RECT 0 1269.285 2754.180 1269.535 ;
    END
  END VDD[147]

  PIN VDD[148]
    DIRECTION INOUT ;
    USE POWER ;
    PORT
      LAYER Metal1 ;
        RECT 0 1277.865 2754.180 1278.115 ;
    END
  END VDD[148]

  PIN VDD[149]
    DIRECTION INOUT ;
    USE POWER ;
    PORT
      LAYER Metal1 ;
        RECT 0 1286.445 2754.180 1286.695 ;
    END
  END VDD[149]

  PIN VDD[150]
    DIRECTION INOUT ;
    USE POWER ;
    PORT
      LAYER Metal1 ;
        RECT 0 1295.025 2754.180 1295.275 ;
    END
  END VDD[150]

  PIN VDD[151]
    DIRECTION INOUT ;
    USE POWER ;
    PORT
      LAYER Metal1 ;
        RECT 0 1303.605 2754.180 1303.855 ;
    END
  END VDD[151]

  PIN VDD[152]
    DIRECTION INOUT ;
    USE POWER ;
    PORT
      LAYER Metal1 ;
        RECT 0 1312.185 2754.180 1312.435 ;
    END
  END VDD[152]

  PIN VDD[153]
    DIRECTION INOUT ;
    USE POWER ;
    PORT
      LAYER Metal1 ;
        RECT 0 1320.765 2754.180 1321.015 ;
    END
  END VDD[153]

  PIN VDD[154]
    DIRECTION INOUT ;
    USE POWER ;
    PORT
      LAYER Metal1 ;
        RECT 0 1329.345 2754.180 1329.595 ;
    END
  END VDD[154]

  PIN VDD[155]
    DIRECTION INOUT ;
    USE POWER ;
    PORT
      LAYER Metal1 ;
        RECT 0 1337.925 2754.180 1338.175 ;
    END
  END VDD[155]

  PIN VDD[156]
    DIRECTION INOUT ;
    USE POWER ;
    PORT
      LAYER Metal1 ;
        RECT 0 1346.505 2754.180 1346.755 ;
    END
  END VDD[156]

  PIN VDD[157]
    DIRECTION INOUT ;
    USE POWER ;
    PORT
      LAYER Metal1 ;
        RECT 0 1355.085 2754.180 1355.335 ;
    END
  END VDD[157]

  PIN VDD[158]
    DIRECTION INOUT ;
    USE POWER ;
    PORT
      LAYER Metal1 ;
        RECT 0 1363.665 2754.180 1363.915 ;
    END
  END VDD[158]

  PIN VDD[159]
    DIRECTION INOUT ;
    USE POWER ;
    PORT
      LAYER Metal1 ;
        RECT 0 1372.245 2754.180 1372.495 ;
    END
  END VDD[159]

  PIN VDD[160]
    DIRECTION INOUT ;
    USE POWER ;
    PORT
      LAYER Metal1 ;
        RECT 0 1380.825 2754.180 1381.075 ;
    END
  END VDD[160]

  PIN VDD[161]
    DIRECTION INOUT ;
    USE POWER ;
    PORT
      LAYER Metal1 ;
        RECT 0 1389.405 2754.180 1389.655 ;
    END
  END VDD[161]

  PIN VDD[162]
    DIRECTION INOUT ;
    USE POWER ;
    PORT
      LAYER Metal1 ;
        RECT 0 1397.985 2754.180 1398.235 ;
    END
  END VDD[162]

  PIN VDD[163]
    DIRECTION INOUT ;
    USE POWER ;
    PORT
      LAYER Metal1 ;
        RECT 0 1406.565 2754.180 1406.815 ;
    END
  END VDD[163]

  PIN VDD[164]
    DIRECTION INOUT ;
    USE POWER ;
    PORT
      LAYER Metal1 ;
        RECT 0 1415.145 2754.180 1415.395 ;
    END
  END VDD[164]

  PIN VDD[165]
    DIRECTION INOUT ;
    USE POWER ;
    PORT
      LAYER Metal1 ;
        RECT 0 1423.725 2754.180 1423.975 ;
    END
  END VDD[165]

  PIN VDD[166]
    DIRECTION INOUT ;
    USE POWER ;
    PORT
      LAYER Metal1 ;
        RECT 0 1432.305 2754.180 1432.555 ;
    END
  END VDD[166]

  PIN VDD[167]
    DIRECTION INOUT ;
    USE POWER ;
    PORT
      LAYER Metal1 ;
        RECT 0 1440.885 2754.180 1441.135 ;
    END
  END VDD[167]

  PIN VDD[168]
    DIRECTION INOUT ;
    USE POWER ;
    PORT
      LAYER Metal1 ;
        RECT 0 1449.465 2754.180 1449.715 ;
    END
  END VDD[168]

  PIN VDD[169]
    DIRECTION INOUT ;
    USE POWER ;
    PORT
      LAYER Metal1 ;
        RECT 0 1458.045 2754.180 1458.295 ;
    END
  END VDD[169]

  PIN VDD[170]
    DIRECTION INOUT ;
    USE POWER ;
    PORT
      LAYER Metal1 ;
        RECT 0 1466.625 2754.180 1466.875 ;
    END
  END VDD[170]

  PIN VDD[171]
    DIRECTION INOUT ;
    USE POWER ;
    PORT
      LAYER Metal1 ;
        RECT 0 1475.205 2754.180 1475.455 ;
    END
  END VDD[171]

  PIN VDD[172]
    DIRECTION INOUT ;
    USE POWER ;
    PORT
      LAYER Metal1 ;
        RECT 0 1483.785 2754.180 1484.035 ;
    END
  END VDD[172]

  PIN VDD[173]
    DIRECTION INOUT ;
    USE POWER ;
    PORT
      LAYER Metal1 ;
        RECT 0 1492.365 2754.180 1492.615 ;
    END
  END VDD[173]

  PIN VDD[174]
    DIRECTION INOUT ;
    USE POWER ;
    PORT
      LAYER Metal1 ;
        RECT 0 1500.945 2754.180 1501.195 ;
    END
  END VDD[174]

  PIN VDD[175]
    DIRECTION INOUT ;
    USE POWER ;
    PORT
      LAYER Metal1 ;
        RECT 0 1509.525 2754.180 1509.775 ;
    END
  END VDD[175]

  PIN VDD[176]
    DIRECTION INOUT ;
    USE POWER ;
    PORT
      LAYER Metal1 ;
        RECT 0 1518.105 2754.180 1518.355 ;
    END
  END VDD[176]

  PIN VDD[177]
    DIRECTION INOUT ;
    USE POWER ;
    PORT
      LAYER Metal1 ;
        RECT 0 1526.685 2754.180 1526.935 ;
    END
  END VDD[177]

  PIN VDD[178]
    DIRECTION INOUT ;
    USE POWER ;
    PORT
      LAYER Metal1 ;
        RECT 0 1535.265 2754.180 1535.515 ;
    END
  END VDD[178]

  PIN VDD[179]
    DIRECTION INOUT ;
    USE POWER ;
    PORT
      LAYER Metal1 ;
        RECT 0 1543.845 2754.180 1544.095 ;
    END
  END VDD[179]

  PIN VDD[180]
    DIRECTION INOUT ;
    USE POWER ;
    PORT
      LAYER Metal1 ;
        RECT 0 1552.425 2754.180 1552.675 ;
    END
  END VDD[180]

  PIN VDD[181]
    DIRECTION INOUT ;
    USE POWER ;
    PORT
      LAYER Metal1 ;
        RECT 0 1561.005 2754.180 1561.255 ;
    END
  END VDD[181]

  PIN VDD[182]
    DIRECTION INOUT ;
    USE POWER ;
    PORT
      LAYER Metal1 ;
        RECT 0 1569.585 2754.180 1569.835 ;
    END
  END VDD[182]

  PIN VDD[183]
    DIRECTION INOUT ;
    USE POWER ;
    PORT
      LAYER Metal1 ;
        RECT 0 1578.165 2754.180 1578.415 ;
    END
  END VDD[183]

  PIN VDD[184]
    DIRECTION INOUT ;
    USE POWER ;
    PORT
      LAYER Metal1 ;
        RECT 0 1586.745 2754.180 1586.995 ;
    END
  END VDD[184]

  PIN VDD[185]
    DIRECTION INOUT ;
    USE POWER ;
    PORT
      LAYER Metal1 ;
        RECT 0 1595.325 2754.180 1595.575 ;
    END
  END VDD[185]

  PIN VDD[186]
    DIRECTION INOUT ;
    USE POWER ;
    PORT
      LAYER Metal1 ;
        RECT 0 1603.905 2754.180 1604.155 ;
    END
  END VDD[186]

  PIN VDD[187]
    DIRECTION INOUT ;
    USE POWER ;
    PORT
      LAYER Metal1 ;
        RECT 0 1612.485 2754.180 1612.735 ;
    END
  END VDD[187]

  PIN VDD[188]
    DIRECTION INOUT ;
    USE POWER ;
    PORT
      LAYER Metal1 ;
        RECT 0 1621.065 2754.180 1621.315 ;
    END
  END VDD[188]

  PIN VDD[189]
    DIRECTION INOUT ;
    USE POWER ;
    PORT
      LAYER Metal1 ;
        RECT 0 1629.645 2754.180 1629.895 ;
    END
  END VDD[189]

  PIN VDD[190]
    DIRECTION INOUT ;
    USE POWER ;
    PORT
      LAYER Metal1 ;
        RECT 0 1638.225 2754.180 1638.475 ;
    END
  END VDD[190]

  PIN VDD[191]
    DIRECTION INOUT ;
    USE POWER ;
    PORT
      LAYER Metal1 ;
        RECT 0 1646.805 2754.180 1647.055 ;
    END
  END VDD[191]

  PIN VDD[192]
    DIRECTION INOUT ;
    USE POWER ;
    PORT
      LAYER Metal1 ;
        RECT 0 1655.385 2754.180 1655.635 ;
    END
  END VDD[192]

  PIN VDD[193]
    DIRECTION INOUT ;
    USE POWER ;
    PORT
      LAYER Metal1 ;
        RECT 0 1663.965 2754.180 1664.215 ;
    END
  END VDD[193]

  PIN VDD[194]
    DIRECTION INOUT ;
    USE POWER ;
    PORT
      LAYER Metal1 ;
        RECT 0 1672.545 2754.180 1672.795 ;
    END
  END VDD[194]

  PIN VDD[195]
    DIRECTION INOUT ;
    USE POWER ;
    PORT
      LAYER Metal1 ;
        RECT 0 1681.125 2754.180 1681.375 ;
    END
  END VDD[195]

  PIN VDD[196]
    DIRECTION INOUT ;
    USE POWER ;
    PORT
      LAYER Metal1 ;
        RECT 0 1689.705 2754.180 1689.955 ;
    END
  END VDD[196]

  PIN VDD[197]
    DIRECTION INOUT ;
    USE POWER ;
    PORT
      LAYER Metal1 ;
        RECT 0 1698.285 2754.180 1698.535 ;
    END
  END VDD[197]

  PIN VDD[198]
    DIRECTION INOUT ;
    USE POWER ;
    PORT
      LAYER Metal1 ;
        RECT 0 1706.865 2754.180 1707.115 ;
    END
  END VDD[198]

  PIN VDD[199]
    DIRECTION INOUT ;
    USE POWER ;
    PORT
      LAYER Metal1 ;
        RECT 0 1715.445 2754.180 1715.695 ;
    END
  END VDD[199]

  PIN VDD[200]
    DIRECTION INOUT ;
    USE POWER ;
    PORT
      LAYER Metal1 ;
        RECT 0 1724.025 2754.180 1724.275 ;
    END
  END VDD[200]

  PIN VDD[201]
    DIRECTION INOUT ;
    USE POWER ;
    PORT
      LAYER Metal1 ;
        RECT 0 1732.605 2754.180 1732.855 ;
    END
  END VDD[201]

  PIN VDD[202]
    DIRECTION INOUT ;
    USE POWER ;
    PORT
      LAYER Metal1 ;
        RECT 0 1741.185 2754.180 1741.435 ;
    END
  END VDD[202]

  PIN VDD[203]
    DIRECTION INOUT ;
    USE POWER ;
    PORT
      LAYER Metal1 ;
        RECT 0 1749.765 2754.180 1750.015 ;
    END
  END VDD[203]

  PIN VDD[204]
    DIRECTION INOUT ;
    USE POWER ;
    PORT
      LAYER Metal1 ;
        RECT 0 1758.345 2754.180 1758.595 ;
    END
  END VDD[204]

  PIN VDD[205]
    DIRECTION INOUT ;
    USE POWER ;
    PORT
      LAYER Metal1 ;
        RECT 0 1766.925 2754.180 1767.175 ;
    END
  END VDD[205]

  PIN VDD[206]
    DIRECTION INOUT ;
    USE POWER ;
    PORT
      LAYER Metal1 ;
        RECT 0 1775.505 2754.180 1775.755 ;
    END
  END VDD[206]

  PIN VDD[207]
    DIRECTION INOUT ;
    USE POWER ;
    PORT
      LAYER Metal1 ;
        RECT 0 1784.085 2754.180 1784.335 ;
    END
  END VDD[207]

  PIN VDD[208]
    DIRECTION INOUT ;
    USE POWER ;
    PORT
      LAYER Metal1 ;
        RECT 0 1792.665 2754.180 1792.915 ;
    END
  END VDD[208]

  PIN VDD[209]
    DIRECTION INOUT ;
    USE POWER ;
    PORT
      LAYER Metal1 ;
        RECT 0 1801.245 2754.180 1801.495 ;
    END
  END VDD[209]

  PIN VDD[210]
    DIRECTION INOUT ;
    USE POWER ;
    PORT
      LAYER Metal1 ;
        RECT 0 1809.825 2754.180 1810.075 ;
    END
  END VDD[210]

  PIN VDD[211]
    DIRECTION INOUT ;
    USE POWER ;
    PORT
      LAYER Metal1 ;
        RECT 0 1818.405 2754.180 1818.655 ;
    END
  END VDD[211]

  PIN VDD[212]
    DIRECTION INOUT ;
    USE POWER ;
    PORT
      LAYER Metal1 ;
        RECT 0 1826.985 2754.180 1827.235 ;
    END
  END VDD[212]

  PIN VDD[213]
    DIRECTION INOUT ;
    USE POWER ;
    PORT
      LAYER Metal1 ;
        RECT 0 1835.565 2754.180 1835.815 ;
    END
  END VDD[213]

  PIN VDD[214]
    DIRECTION INOUT ;
    USE POWER ;
    PORT
      LAYER Metal1 ;
        RECT 0 1844.145 2754.180 1844.395 ;
    END
  END VDD[214]

  PIN VDD[215]
    DIRECTION INOUT ;
    USE POWER ;
    PORT
      LAYER Metal1 ;
        RECT 0 1852.725 2754.180 1852.975 ;
    END
  END VDD[215]

  PIN VDD[216]
    DIRECTION INOUT ;
    USE POWER ;
    PORT
      LAYER Metal1 ;
        RECT 0 1861.305 2754.180 1861.555 ;
    END
  END VDD[216]

  PIN VDD[217]
    DIRECTION INOUT ;
    USE POWER ;
    PORT
      LAYER Metal1 ;
        RECT 0 1869.885 2754.180 1870.135 ;
    END
  END VDD[217]

  PIN VDD[218]
    DIRECTION INOUT ;
    USE POWER ;
    PORT
      LAYER Metal1 ;
        RECT 0 1878.465 2754.180 1878.715 ;
    END
  END VDD[218]

  PIN VDD[219]
    DIRECTION INOUT ;
    USE POWER ;
    PORT
      LAYER Metal1 ;
        RECT 0 1887.045 2754.180 1887.295 ;
    END
  END VDD[219]

  PIN VDD[220]
    DIRECTION INOUT ;
    USE POWER ;
    PORT
      LAYER Metal1 ;
        RECT 0 1895.625 2754.180 1895.875 ;
    END
  END VDD[220]

  PIN VDD[221]
    DIRECTION INOUT ;
    USE POWER ;
    PORT
      LAYER Metal1 ;
        RECT 0 1904.205 2754.180 1904.455 ;
    END
  END VDD[221]

  PIN VDD[222]
    DIRECTION INOUT ;
    USE POWER ;
    PORT
      LAYER Metal1 ;
        RECT 0 1912.785 2754.180 1913.035 ;
    END
  END VDD[222]

  PIN VDD[223]
    DIRECTION INOUT ;
    USE POWER ;
    PORT
      LAYER Metal1 ;
        RECT 0 1921.365 2754.180 1921.615 ;
    END
  END VDD[223]

  PIN VDD[224]
    DIRECTION INOUT ;
    USE POWER ;
    PORT
      LAYER Metal1 ;
        RECT 0 1929.945 2754.180 1930.195 ;
    END
  END VDD[224]

  PIN VDD[225]
    DIRECTION INOUT ;
    USE POWER ;
    PORT
      LAYER Metal1 ;
        RECT 0 1938.525 2754.180 1938.775 ;
    END
  END VDD[225]

  PIN VDD[226]
    DIRECTION INOUT ;
    USE POWER ;
    PORT
      LAYER Metal1 ;
        RECT 0 1947.105 2754.180 1947.355 ;
    END
  END VDD[226]

  PIN VDD[227]
    DIRECTION INOUT ;
    USE POWER ;
    PORT
      LAYER Metal1 ;
        RECT 0 1955.685 2754.180 1955.935 ;
    END
  END VDD[227]

  PIN VDD[228]
    DIRECTION INOUT ;
    USE POWER ;
    PORT
      LAYER Metal1 ;
        RECT 0 1964.265 2754.180 1964.515 ;
    END
  END VDD[228]

  PIN VDD[229]
    DIRECTION INOUT ;
    USE POWER ;
    PORT
      LAYER Metal1 ;
        RECT 0 1972.845 2754.180 1973.095 ;
    END
  END VDD[229]

  PIN VDD[230]
    DIRECTION INOUT ;
    USE POWER ;
    PORT
      LAYER Metal1 ;
        RECT 0 1981.425 2754.180 1981.675 ;
    END
  END VDD[230]

  PIN VDD[231]
    DIRECTION INOUT ;
    USE POWER ;
    PORT
      LAYER Metal1 ;
        RECT 0 1990.005 2754.180 1990.255 ;
    END
  END VDD[231]

  PIN VDD[232]
    DIRECTION INOUT ;
    USE POWER ;
    PORT
      LAYER Metal1 ;
        RECT 0 1998.585 2754.180 1998.835 ;
    END
  END VDD[232]

  PIN VDD[233]
    DIRECTION INOUT ;
    USE POWER ;
    PORT
      LAYER Metal1 ;
        RECT 0 2007.165 2754.180 2007.415 ;
    END
  END VDD[233]

  PIN VDD[234]
    DIRECTION INOUT ;
    USE POWER ;
    PORT
      LAYER Metal1 ;
        RECT 0 2015.745 2754.180 2015.995 ;
    END
  END VDD[234]

  PIN VDD[235]
    DIRECTION INOUT ;
    USE POWER ;
    PORT
      LAYER Metal1 ;
        RECT 0 2024.325 2754.180 2024.575 ;
    END
  END VDD[235]

  PIN VDD[236]
    DIRECTION INOUT ;
    USE POWER ;
    PORT
      LAYER Metal1 ;
        RECT 0 2032.905 2754.180 2033.155 ;
    END
  END VDD[236]

  PIN VDD[237]
    DIRECTION INOUT ;
    USE POWER ;
    PORT
      LAYER Metal1 ;
        RECT 0 2041.485 2754.180 2041.735 ;
    END
  END VDD[237]

  PIN VDD[238]
    DIRECTION INOUT ;
    USE POWER ;
    PORT
      LAYER Metal1 ;
        RECT 0 2050.065 2754.180 2050.315 ;
    END
  END VDD[238]

  PIN VDD[239]
    DIRECTION INOUT ;
    USE POWER ;
    PORT
      LAYER Metal1 ;
        RECT 0 2058.645 2754.180 2058.895 ;
    END
  END VDD[239]

  PIN COLUMN_OUTPUT[0]
    DIRECTION OUTPUT ;
    USE SIGNAL ;
    PORT
      LAYER Metal2 ;
        RECT 7.845 0 8.125 2059.200 ;
    END
  END COLUMN_OUTPUT[0]

  PIN COLUMN_OUTPUT[1]
    DIRECTION OUTPUT ;
    USE SIGNAL ;
    PORT
      LAYER Metal2 ;
        RECT 16.425 0 16.705 2059.200 ;
    END
  END COLUMN_OUTPUT[1]

  PIN COLUMN_OUTPUT[2]
    DIRECTION OUTPUT ;
    USE SIGNAL ;
    PORT
      LAYER Metal2 ;
        RECT 25.005 0 25.285 2059.200 ;
    END
  END COLUMN_OUTPUT[2]

  PIN COLUMN_OUTPUT[3]
    DIRECTION OUTPUT ;
    USE SIGNAL ;
    PORT
      LAYER Metal2 ;
        RECT 33.585 0 33.865 2059.200 ;
    END
  END COLUMN_OUTPUT[3]

  PIN COLUMN_OUTPUT[4]
    DIRECTION OUTPUT ;
    USE SIGNAL ;
    PORT
      LAYER Metal2 ;
        RECT 42.165 0 42.445 2059.200 ;
    END
  END COLUMN_OUTPUT[4]

  PIN COLUMN_OUTPUT[5]
    DIRECTION OUTPUT ;
    USE SIGNAL ;
    PORT
      LAYER Metal2 ;
        RECT 50.745 0 51.025 2059.200 ;
    END
  END COLUMN_OUTPUT[5]

  PIN COLUMN_OUTPUT[6]
    DIRECTION OUTPUT ;
    USE SIGNAL ;
    PORT
      LAYER Metal2 ;
        RECT 59.325 0 59.605 2059.200 ;
    END
  END COLUMN_OUTPUT[6]

  PIN COLUMN_OUTPUT[7]
    DIRECTION OUTPUT ;
    USE SIGNAL ;
    PORT
      LAYER Metal2 ;
        RECT 67.905 0 68.185 2059.200 ;
    END
  END COLUMN_OUTPUT[7]

  PIN COLUMN_OUTPUT[8]
    DIRECTION OUTPUT ;
    USE SIGNAL ;
    PORT
      LAYER Metal2 ;
        RECT 76.485 0 76.765 2059.200 ;
    END
  END COLUMN_OUTPUT[8]

  PIN COLUMN_OUTPUT[9]
    DIRECTION OUTPUT ;
    USE SIGNAL ;
    PORT
      LAYER Metal2 ;
        RECT 85.065 0 85.345 2059.200 ;
    END
  END COLUMN_OUTPUT[9]

  PIN COLUMN_OUTPUT[10]
    DIRECTION OUTPUT ;
    USE SIGNAL ;
    PORT
      LAYER Metal2 ;
        RECT 93.645 0 93.925 2059.200 ;
    END
  END COLUMN_OUTPUT[10]

  PIN COLUMN_OUTPUT[11]
    DIRECTION OUTPUT ;
    USE SIGNAL ;
    PORT
      LAYER Metal2 ;
        RECT 102.225 0 102.505 2059.200 ;
    END
  END COLUMN_OUTPUT[11]

  PIN COLUMN_OUTPUT[12]
    DIRECTION OUTPUT ;
    USE SIGNAL ;
    PORT
      LAYER Metal2 ;
        RECT 110.805 0 111.085 2059.200 ;
    END
  END COLUMN_OUTPUT[12]

  PIN COLUMN_OUTPUT[13]
    DIRECTION OUTPUT ;
    USE SIGNAL ;
    PORT
      LAYER Metal2 ;
        RECT 119.385 0 119.665 2059.200 ;
    END
  END COLUMN_OUTPUT[13]

  PIN COLUMN_OUTPUT[14]
    DIRECTION OUTPUT ;
    USE SIGNAL ;
    PORT
      LAYER Metal2 ;
        RECT 127.965 0 128.245 2059.200 ;
    END
  END COLUMN_OUTPUT[14]

  PIN COLUMN_OUTPUT[15]
    DIRECTION OUTPUT ;
    USE SIGNAL ;
    PORT
      LAYER Metal2 ;
        RECT 136.545 0 136.825 2059.200 ;
    END
  END COLUMN_OUTPUT[15]

  PIN COLUMN_OUTPUT[16]
    DIRECTION OUTPUT ;
    USE SIGNAL ;
    PORT
      LAYER Metal2 ;
        RECT 145.125 0 145.405 2059.200 ;
    END
  END COLUMN_OUTPUT[16]

  PIN COLUMN_OUTPUT[17]
    DIRECTION OUTPUT ;
    USE SIGNAL ;
    PORT
      LAYER Metal2 ;
        RECT 153.705 0 153.985 2059.200 ;
    END
  END COLUMN_OUTPUT[17]

  PIN COLUMN_OUTPUT[18]
    DIRECTION OUTPUT ;
    USE SIGNAL ;
    PORT
      LAYER Metal2 ;
        RECT 162.285 0 162.565 2059.200 ;
    END
  END COLUMN_OUTPUT[18]

  PIN COLUMN_OUTPUT[19]
    DIRECTION OUTPUT ;
    USE SIGNAL ;
    PORT
      LAYER Metal2 ;
        RECT 170.865 0 171.145 2059.200 ;
    END
  END COLUMN_OUTPUT[19]

  PIN COLUMN_OUTPUT[20]
    DIRECTION OUTPUT ;
    USE SIGNAL ;
    PORT
      LAYER Metal2 ;
        RECT 179.445 0 179.725 2059.200 ;
    END
  END COLUMN_OUTPUT[20]

  PIN COLUMN_OUTPUT[21]
    DIRECTION OUTPUT ;
    USE SIGNAL ;
    PORT
      LAYER Metal2 ;
        RECT 188.025 0 188.305 2059.200 ;
    END
  END COLUMN_OUTPUT[21]

  PIN COLUMN_OUTPUT[22]
    DIRECTION OUTPUT ;
    USE SIGNAL ;
    PORT
      LAYER Metal2 ;
        RECT 196.605 0 196.885 2059.200 ;
    END
  END COLUMN_OUTPUT[22]

  PIN COLUMN_OUTPUT[23]
    DIRECTION OUTPUT ;
    USE SIGNAL ;
    PORT
      LAYER Metal2 ;
        RECT 205.185 0 205.465 2059.200 ;
    END
  END COLUMN_OUTPUT[23]

  PIN COLUMN_OUTPUT[24]
    DIRECTION OUTPUT ;
    USE SIGNAL ;
    PORT
      LAYER Metal2 ;
        RECT 213.765 0 214.045 2059.200 ;
    END
  END COLUMN_OUTPUT[24]

  PIN COLUMN_OUTPUT[25]
    DIRECTION OUTPUT ;
    USE SIGNAL ;
    PORT
      LAYER Metal2 ;
        RECT 222.345 0 222.625 2059.200 ;
    END
  END COLUMN_OUTPUT[25]

  PIN COLUMN_OUTPUT[26]
    DIRECTION OUTPUT ;
    USE SIGNAL ;
    PORT
      LAYER Metal2 ;
        RECT 230.925 0 231.205 2059.200 ;
    END
  END COLUMN_OUTPUT[26]

  PIN COLUMN_OUTPUT[27]
    DIRECTION OUTPUT ;
    USE SIGNAL ;
    PORT
      LAYER Metal2 ;
        RECT 239.505 0 239.785 2059.200 ;
    END
  END COLUMN_OUTPUT[27]

  PIN COLUMN_OUTPUT[28]
    DIRECTION OUTPUT ;
    USE SIGNAL ;
    PORT
      LAYER Metal2 ;
        RECT 248.085 0 248.365 2059.200 ;
    END
  END COLUMN_OUTPUT[28]

  PIN COLUMN_OUTPUT[29]
    DIRECTION OUTPUT ;
    USE SIGNAL ;
    PORT
      LAYER Metal2 ;
        RECT 256.665 0 256.945 2059.200 ;
    END
  END COLUMN_OUTPUT[29]

  PIN COLUMN_OUTPUT[30]
    DIRECTION OUTPUT ;
    USE SIGNAL ;
    PORT
      LAYER Metal2 ;
        RECT 265.245 0 265.525 2059.200 ;
    END
  END COLUMN_OUTPUT[30]

  PIN COLUMN_OUTPUT[31]
    DIRECTION OUTPUT ;
    USE SIGNAL ;
    PORT
      LAYER Metal2 ;
        RECT 273.825 0 274.105 2059.200 ;
    END
  END COLUMN_OUTPUT[31]

  PIN COLUMN_OUTPUT[32]
    DIRECTION OUTPUT ;
    USE SIGNAL ;
    PORT
      LAYER Metal2 ;
        RECT 282.405 0 282.685 2059.200 ;
    END
  END COLUMN_OUTPUT[32]

  PIN COLUMN_OUTPUT[33]
    DIRECTION OUTPUT ;
    USE SIGNAL ;
    PORT
      LAYER Metal2 ;
        RECT 290.985 0 291.265 2059.200 ;
    END
  END COLUMN_OUTPUT[33]

  PIN COLUMN_OUTPUT[34]
    DIRECTION OUTPUT ;
    USE SIGNAL ;
    PORT
      LAYER Metal2 ;
        RECT 299.565 0 299.845 2059.200 ;
    END
  END COLUMN_OUTPUT[34]

  PIN COLUMN_OUTPUT[35]
    DIRECTION OUTPUT ;
    USE SIGNAL ;
    PORT
      LAYER Metal2 ;
        RECT 308.145 0 308.425 2059.200 ;
    END
  END COLUMN_OUTPUT[35]

  PIN COLUMN_OUTPUT[36]
    DIRECTION OUTPUT ;
    USE SIGNAL ;
    PORT
      LAYER Metal2 ;
        RECT 316.725 0 317.005 2059.200 ;
    END
  END COLUMN_OUTPUT[36]

  PIN COLUMN_OUTPUT[37]
    DIRECTION OUTPUT ;
    USE SIGNAL ;
    PORT
      LAYER Metal2 ;
        RECT 325.305 0 325.585 2059.200 ;
    END
  END COLUMN_OUTPUT[37]

  PIN COLUMN_OUTPUT[38]
    DIRECTION OUTPUT ;
    USE SIGNAL ;
    PORT
      LAYER Metal2 ;
        RECT 333.885 0 334.165 2059.200 ;
    END
  END COLUMN_OUTPUT[38]

  PIN COLUMN_OUTPUT[39]
    DIRECTION OUTPUT ;
    USE SIGNAL ;
    PORT
      LAYER Metal2 ;
        RECT 342.465 0 342.745 2059.200 ;
    END
  END COLUMN_OUTPUT[39]

  PIN COLUMN_OUTPUT[40]
    DIRECTION OUTPUT ;
    USE SIGNAL ;
    PORT
      LAYER Metal2 ;
        RECT 351.045 0 351.325 2059.200 ;
    END
  END COLUMN_OUTPUT[40]

  PIN COLUMN_OUTPUT[41]
    DIRECTION OUTPUT ;
    USE SIGNAL ;
    PORT
      LAYER Metal2 ;
        RECT 359.625 0 359.905 2059.200 ;
    END
  END COLUMN_OUTPUT[41]

  PIN COLUMN_OUTPUT[42]
    DIRECTION OUTPUT ;
    USE SIGNAL ;
    PORT
      LAYER Metal2 ;
        RECT 368.205 0 368.485 2059.200 ;
    END
  END COLUMN_OUTPUT[42]

  PIN COLUMN_OUTPUT[43]
    DIRECTION OUTPUT ;
    USE SIGNAL ;
    PORT
      LAYER Metal2 ;
        RECT 376.785 0 377.065 2059.200 ;
    END
  END COLUMN_OUTPUT[43]

  PIN COLUMN_OUTPUT[44]
    DIRECTION OUTPUT ;
    USE SIGNAL ;
    PORT
      LAYER Metal2 ;
        RECT 385.365 0 385.645 2059.200 ;
    END
  END COLUMN_OUTPUT[44]

  PIN COLUMN_OUTPUT[45]
    DIRECTION OUTPUT ;
    USE SIGNAL ;
    PORT
      LAYER Metal2 ;
        RECT 393.945 0 394.225 2059.200 ;
    END
  END COLUMN_OUTPUT[45]

  PIN COLUMN_OUTPUT[46]
    DIRECTION OUTPUT ;
    USE SIGNAL ;
    PORT
      LAYER Metal2 ;
        RECT 402.525 0 402.805 2059.200 ;
    END
  END COLUMN_OUTPUT[46]

  PIN COLUMN_OUTPUT[47]
    DIRECTION OUTPUT ;
    USE SIGNAL ;
    PORT
      LAYER Metal2 ;
        RECT 411.105 0 411.385 2059.200 ;
    END
  END COLUMN_OUTPUT[47]

  PIN COLUMN_OUTPUT[48]
    DIRECTION OUTPUT ;
    USE SIGNAL ;
    PORT
      LAYER Metal2 ;
        RECT 419.685 0 419.965 2059.200 ;
    END
  END COLUMN_OUTPUT[48]

  PIN COLUMN_OUTPUT[49]
    DIRECTION OUTPUT ;
    USE SIGNAL ;
    PORT
      LAYER Metal2 ;
        RECT 428.265 0 428.545 2059.200 ;
    END
  END COLUMN_OUTPUT[49]

  PIN COLUMN_OUTPUT[50]
    DIRECTION OUTPUT ;
    USE SIGNAL ;
    PORT
      LAYER Metal2 ;
        RECT 436.845 0 437.125 2059.200 ;
    END
  END COLUMN_OUTPUT[50]

  PIN COLUMN_OUTPUT[51]
    DIRECTION OUTPUT ;
    USE SIGNAL ;
    PORT
      LAYER Metal2 ;
        RECT 445.425 0 445.705 2059.200 ;
    END
  END COLUMN_OUTPUT[51]

  PIN COLUMN_OUTPUT[52]
    DIRECTION OUTPUT ;
    USE SIGNAL ;
    PORT
      LAYER Metal2 ;
        RECT 454.005 0 454.285 2059.200 ;
    END
  END COLUMN_OUTPUT[52]

  PIN COLUMN_OUTPUT[53]
    DIRECTION OUTPUT ;
    USE SIGNAL ;
    PORT
      LAYER Metal2 ;
        RECT 462.585 0 462.865 2059.200 ;
    END
  END COLUMN_OUTPUT[53]

  PIN COLUMN_OUTPUT[54]
    DIRECTION OUTPUT ;
    USE SIGNAL ;
    PORT
      LAYER Metal2 ;
        RECT 471.165 0 471.445 2059.200 ;
    END
  END COLUMN_OUTPUT[54]

  PIN COLUMN_OUTPUT[55]
    DIRECTION OUTPUT ;
    USE SIGNAL ;
    PORT
      LAYER Metal2 ;
        RECT 479.745 0 480.025 2059.200 ;
    END
  END COLUMN_OUTPUT[55]

  PIN COLUMN_OUTPUT[56]
    DIRECTION OUTPUT ;
    USE SIGNAL ;
    PORT
      LAYER Metal2 ;
        RECT 488.325 0 488.605 2059.200 ;
    END
  END COLUMN_OUTPUT[56]

  PIN COLUMN_OUTPUT[57]
    DIRECTION OUTPUT ;
    USE SIGNAL ;
    PORT
      LAYER Metal2 ;
        RECT 496.905 0 497.185 2059.200 ;
    END
  END COLUMN_OUTPUT[57]

  PIN COLUMN_OUTPUT[58]
    DIRECTION OUTPUT ;
    USE SIGNAL ;
    PORT
      LAYER Metal2 ;
        RECT 505.485 0 505.765 2059.200 ;
    END
  END COLUMN_OUTPUT[58]

  PIN COLUMN_OUTPUT[59]
    DIRECTION OUTPUT ;
    USE SIGNAL ;
    PORT
      LAYER Metal2 ;
        RECT 514.065 0 514.345 2059.200 ;
    END
  END COLUMN_OUTPUT[59]

  PIN COLUMN_OUTPUT[60]
    DIRECTION OUTPUT ;
    USE SIGNAL ;
    PORT
      LAYER Metal2 ;
        RECT 522.645 0 522.925 2059.200 ;
    END
  END COLUMN_OUTPUT[60]

  PIN COLUMN_OUTPUT[61]
    DIRECTION OUTPUT ;
    USE SIGNAL ;
    PORT
      LAYER Metal2 ;
        RECT 531.225 0 531.505 2059.200 ;
    END
  END COLUMN_OUTPUT[61]

  PIN COLUMN_OUTPUT[62]
    DIRECTION OUTPUT ;
    USE SIGNAL ;
    PORT
      LAYER Metal2 ;
        RECT 539.805 0 540.085 2059.200 ;
    END
  END COLUMN_OUTPUT[62]

  PIN COLUMN_OUTPUT[63]
    DIRECTION OUTPUT ;
    USE SIGNAL ;
    PORT
      LAYER Metal2 ;
        RECT 548.385 0 548.665 2059.200 ;
    END
  END COLUMN_OUTPUT[63]

  PIN COLUMN_OUTPUT[64]
    DIRECTION OUTPUT ;
    USE SIGNAL ;
    PORT
      LAYER Metal2 ;
        RECT 556.965 0 557.245 2059.200 ;
    END
  END COLUMN_OUTPUT[64]

  PIN COLUMN_OUTPUT[65]
    DIRECTION OUTPUT ;
    USE SIGNAL ;
    PORT
      LAYER Metal2 ;
        RECT 565.545 0 565.825 2059.200 ;
    END
  END COLUMN_OUTPUT[65]

  PIN COLUMN_OUTPUT[66]
    DIRECTION OUTPUT ;
    USE SIGNAL ;
    PORT
      LAYER Metal2 ;
        RECT 574.125 0 574.405 2059.200 ;
    END
  END COLUMN_OUTPUT[66]

  PIN COLUMN_OUTPUT[67]
    DIRECTION OUTPUT ;
    USE SIGNAL ;
    PORT
      LAYER Metal2 ;
        RECT 582.705 0 582.985 2059.200 ;
    END
  END COLUMN_OUTPUT[67]

  PIN COLUMN_OUTPUT[68]
    DIRECTION OUTPUT ;
    USE SIGNAL ;
    PORT
      LAYER Metal2 ;
        RECT 591.285 0 591.565 2059.200 ;
    END
  END COLUMN_OUTPUT[68]

  PIN COLUMN_OUTPUT[69]
    DIRECTION OUTPUT ;
    USE SIGNAL ;
    PORT
      LAYER Metal2 ;
        RECT 599.865 0 600.145 2059.200 ;
    END
  END COLUMN_OUTPUT[69]

  PIN COLUMN_OUTPUT[70]
    DIRECTION OUTPUT ;
    USE SIGNAL ;
    PORT
      LAYER Metal2 ;
        RECT 608.445 0 608.725 2059.200 ;
    END
  END COLUMN_OUTPUT[70]

  PIN COLUMN_OUTPUT[71]
    DIRECTION OUTPUT ;
    USE SIGNAL ;
    PORT
      LAYER Metal2 ;
        RECT 617.025 0 617.305 2059.200 ;
    END
  END COLUMN_OUTPUT[71]

  PIN COLUMN_OUTPUT[72]
    DIRECTION OUTPUT ;
    USE SIGNAL ;
    PORT
      LAYER Metal2 ;
        RECT 625.605 0 625.885 2059.200 ;
    END
  END COLUMN_OUTPUT[72]

  PIN COLUMN_OUTPUT[73]
    DIRECTION OUTPUT ;
    USE SIGNAL ;
    PORT
      LAYER Metal2 ;
        RECT 634.185 0 634.465 2059.200 ;
    END
  END COLUMN_OUTPUT[73]

  PIN COLUMN_OUTPUT[74]
    DIRECTION OUTPUT ;
    USE SIGNAL ;
    PORT
      LAYER Metal2 ;
        RECT 642.765 0 643.045 2059.200 ;
    END
  END COLUMN_OUTPUT[74]

  PIN COLUMN_OUTPUT[75]
    DIRECTION OUTPUT ;
    USE SIGNAL ;
    PORT
      LAYER Metal2 ;
        RECT 651.345 0 651.625 2059.200 ;
    END
  END COLUMN_OUTPUT[75]

  PIN COLUMN_OUTPUT[76]
    DIRECTION OUTPUT ;
    USE SIGNAL ;
    PORT
      LAYER Metal2 ;
        RECT 659.925 0 660.205 2059.200 ;
    END
  END COLUMN_OUTPUT[76]

  PIN COLUMN_OUTPUT[77]
    DIRECTION OUTPUT ;
    USE SIGNAL ;
    PORT
      LAYER Metal2 ;
        RECT 668.505 0 668.785 2059.200 ;
    END
  END COLUMN_OUTPUT[77]

  PIN COLUMN_OUTPUT[78]
    DIRECTION OUTPUT ;
    USE SIGNAL ;
    PORT
      LAYER Metal2 ;
        RECT 677.085 0 677.365 2059.200 ;
    END
  END COLUMN_OUTPUT[78]

  PIN COLUMN_OUTPUT[79]
    DIRECTION OUTPUT ;
    USE SIGNAL ;
    PORT
      LAYER Metal2 ;
        RECT 685.665 0 685.945 2059.200 ;
    END
  END COLUMN_OUTPUT[79]

  PIN COLUMN_OUTPUT[80]
    DIRECTION OUTPUT ;
    USE SIGNAL ;
    PORT
      LAYER Metal2 ;
        RECT 694.245 0 694.525 2059.200 ;
    END
  END COLUMN_OUTPUT[80]

  PIN COLUMN_OUTPUT[81]
    DIRECTION OUTPUT ;
    USE SIGNAL ;
    PORT
      LAYER Metal2 ;
        RECT 702.825 0 703.105 2059.200 ;
    END
  END COLUMN_OUTPUT[81]

  PIN COLUMN_OUTPUT[82]
    DIRECTION OUTPUT ;
    USE SIGNAL ;
    PORT
      LAYER Metal2 ;
        RECT 711.405 0 711.685 2059.200 ;
    END
  END COLUMN_OUTPUT[82]

  PIN COLUMN_OUTPUT[83]
    DIRECTION OUTPUT ;
    USE SIGNAL ;
    PORT
      LAYER Metal2 ;
        RECT 719.985 0 720.265 2059.200 ;
    END
  END COLUMN_OUTPUT[83]

  PIN COLUMN_OUTPUT[84]
    DIRECTION OUTPUT ;
    USE SIGNAL ;
    PORT
      LAYER Metal2 ;
        RECT 728.565 0 728.845 2059.200 ;
    END
  END COLUMN_OUTPUT[84]

  PIN COLUMN_OUTPUT[85]
    DIRECTION OUTPUT ;
    USE SIGNAL ;
    PORT
      LAYER Metal2 ;
        RECT 737.145 0 737.425 2059.200 ;
    END
  END COLUMN_OUTPUT[85]

  PIN COLUMN_OUTPUT[86]
    DIRECTION OUTPUT ;
    USE SIGNAL ;
    PORT
      LAYER Metal2 ;
        RECT 745.725 0 746.005 2059.200 ;
    END
  END COLUMN_OUTPUT[86]

  PIN COLUMN_OUTPUT[87]
    DIRECTION OUTPUT ;
    USE SIGNAL ;
    PORT
      LAYER Metal2 ;
        RECT 754.305 0 754.585 2059.200 ;
    END
  END COLUMN_OUTPUT[87]

  PIN COLUMN_OUTPUT[88]
    DIRECTION OUTPUT ;
    USE SIGNAL ;
    PORT
      LAYER Metal2 ;
        RECT 762.885 0 763.165 2059.200 ;
    END
  END COLUMN_OUTPUT[88]

  PIN COLUMN_OUTPUT[89]
    DIRECTION OUTPUT ;
    USE SIGNAL ;
    PORT
      LAYER Metal2 ;
        RECT 771.465 0 771.745 2059.200 ;
    END
  END COLUMN_OUTPUT[89]

  PIN COLUMN_OUTPUT[90]
    DIRECTION OUTPUT ;
    USE SIGNAL ;
    PORT
      LAYER Metal2 ;
        RECT 780.045 0 780.325 2059.200 ;
    END
  END COLUMN_OUTPUT[90]

  PIN COLUMN_OUTPUT[91]
    DIRECTION OUTPUT ;
    USE SIGNAL ;
    PORT
      LAYER Metal2 ;
        RECT 788.625 0 788.905 2059.200 ;
    END
  END COLUMN_OUTPUT[91]

  PIN COLUMN_OUTPUT[92]
    DIRECTION OUTPUT ;
    USE SIGNAL ;
    PORT
      LAYER Metal2 ;
        RECT 797.205 0 797.485 2059.200 ;
    END
  END COLUMN_OUTPUT[92]

  PIN COLUMN_OUTPUT[93]
    DIRECTION OUTPUT ;
    USE SIGNAL ;
    PORT
      LAYER Metal2 ;
        RECT 805.785 0 806.065 2059.200 ;
    END
  END COLUMN_OUTPUT[93]

  PIN COLUMN_OUTPUT[94]
    DIRECTION OUTPUT ;
    USE SIGNAL ;
    PORT
      LAYER Metal2 ;
        RECT 814.365 0 814.645 2059.200 ;
    END
  END COLUMN_OUTPUT[94]

  PIN COLUMN_OUTPUT[95]
    DIRECTION OUTPUT ;
    USE SIGNAL ;
    PORT
      LAYER Metal2 ;
        RECT 822.945 0 823.225 2059.200 ;
    END
  END COLUMN_OUTPUT[95]

  PIN COLUMN_OUTPUT[96]
    DIRECTION OUTPUT ;
    USE SIGNAL ;
    PORT
      LAYER Metal2 ;
        RECT 831.525 0 831.805 2059.200 ;
    END
  END COLUMN_OUTPUT[96]

  PIN COLUMN_OUTPUT[97]
    DIRECTION OUTPUT ;
    USE SIGNAL ;
    PORT
      LAYER Metal2 ;
        RECT 840.105 0 840.385 2059.200 ;
    END
  END COLUMN_OUTPUT[97]

  PIN COLUMN_OUTPUT[98]
    DIRECTION OUTPUT ;
    USE SIGNAL ;
    PORT
      LAYER Metal2 ;
        RECT 848.685 0 848.965 2059.200 ;
    END
  END COLUMN_OUTPUT[98]

  PIN COLUMN_OUTPUT[99]
    DIRECTION OUTPUT ;
    USE SIGNAL ;
    PORT
      LAYER Metal2 ;
        RECT 857.265 0 857.545 2059.200 ;
    END
  END COLUMN_OUTPUT[99]

  PIN COLUMN_OUTPUT[100]
    DIRECTION OUTPUT ;
    USE SIGNAL ;
    PORT
      LAYER Metal2 ;
        RECT 865.845 0 866.125 2059.200 ;
    END
  END COLUMN_OUTPUT[100]

  PIN COLUMN_OUTPUT[101]
    DIRECTION OUTPUT ;
    USE SIGNAL ;
    PORT
      LAYER Metal2 ;
        RECT 874.425 0 874.705 2059.200 ;
    END
  END COLUMN_OUTPUT[101]

  PIN COLUMN_OUTPUT[102]
    DIRECTION OUTPUT ;
    USE SIGNAL ;
    PORT
      LAYER Metal2 ;
        RECT 883.005 0 883.285 2059.200 ;
    END
  END COLUMN_OUTPUT[102]

  PIN COLUMN_OUTPUT[103]
    DIRECTION OUTPUT ;
    USE SIGNAL ;
    PORT
      LAYER Metal2 ;
        RECT 891.585 0 891.865 2059.200 ;
    END
  END COLUMN_OUTPUT[103]

  PIN COLUMN_OUTPUT[104]
    DIRECTION OUTPUT ;
    USE SIGNAL ;
    PORT
      LAYER Metal2 ;
        RECT 900.165 0 900.445 2059.200 ;
    END
  END COLUMN_OUTPUT[104]

  PIN COLUMN_OUTPUT[105]
    DIRECTION OUTPUT ;
    USE SIGNAL ;
    PORT
      LAYER Metal2 ;
        RECT 908.745 0 909.025 2059.200 ;
    END
  END COLUMN_OUTPUT[105]

  PIN COLUMN_OUTPUT[106]
    DIRECTION OUTPUT ;
    USE SIGNAL ;
    PORT
      LAYER Metal2 ;
        RECT 917.325 0 917.605 2059.200 ;
    END
  END COLUMN_OUTPUT[106]

  PIN COLUMN_OUTPUT[107]
    DIRECTION OUTPUT ;
    USE SIGNAL ;
    PORT
      LAYER Metal2 ;
        RECT 925.905 0 926.185 2059.200 ;
    END
  END COLUMN_OUTPUT[107]

  PIN COLUMN_OUTPUT[108]
    DIRECTION OUTPUT ;
    USE SIGNAL ;
    PORT
      LAYER Metal2 ;
        RECT 934.485 0 934.765 2059.200 ;
    END
  END COLUMN_OUTPUT[108]

  PIN COLUMN_OUTPUT[109]
    DIRECTION OUTPUT ;
    USE SIGNAL ;
    PORT
      LAYER Metal2 ;
        RECT 943.065 0 943.345 2059.200 ;
    END
  END COLUMN_OUTPUT[109]

  PIN COLUMN_OUTPUT[110]
    DIRECTION OUTPUT ;
    USE SIGNAL ;
    PORT
      LAYER Metal2 ;
        RECT 951.645 0 951.925 2059.200 ;
    END
  END COLUMN_OUTPUT[110]

  PIN COLUMN_OUTPUT[111]
    DIRECTION OUTPUT ;
    USE SIGNAL ;
    PORT
      LAYER Metal2 ;
        RECT 960.225 0 960.505 2059.200 ;
    END
  END COLUMN_OUTPUT[111]

  PIN COLUMN_OUTPUT[112]
    DIRECTION OUTPUT ;
    USE SIGNAL ;
    PORT
      LAYER Metal2 ;
        RECT 968.805 0 969.085 2059.200 ;
    END
  END COLUMN_OUTPUT[112]

  PIN COLUMN_OUTPUT[113]
    DIRECTION OUTPUT ;
    USE SIGNAL ;
    PORT
      LAYER Metal2 ;
        RECT 977.385 0 977.665 2059.200 ;
    END
  END COLUMN_OUTPUT[113]

  PIN COLUMN_OUTPUT[114]
    DIRECTION OUTPUT ;
    USE SIGNAL ;
    PORT
      LAYER Metal2 ;
        RECT 985.965 0 986.245 2059.200 ;
    END
  END COLUMN_OUTPUT[114]

  PIN COLUMN_OUTPUT[115]
    DIRECTION OUTPUT ;
    USE SIGNAL ;
    PORT
      LAYER Metal2 ;
        RECT 994.545 0 994.825 2059.200 ;
    END
  END COLUMN_OUTPUT[115]

  PIN COLUMN_OUTPUT[116]
    DIRECTION OUTPUT ;
    USE SIGNAL ;
    PORT
      LAYER Metal2 ;
        RECT 1003.125 0 1003.405 2059.200 ;
    END
  END COLUMN_OUTPUT[116]

  PIN COLUMN_OUTPUT[117]
    DIRECTION OUTPUT ;
    USE SIGNAL ;
    PORT
      LAYER Metal2 ;
        RECT 1011.705 0 1011.985 2059.200 ;
    END
  END COLUMN_OUTPUT[117]

  PIN COLUMN_OUTPUT[118]
    DIRECTION OUTPUT ;
    USE SIGNAL ;
    PORT
      LAYER Metal2 ;
        RECT 1020.285 0 1020.565 2059.200 ;
    END
  END COLUMN_OUTPUT[118]

  PIN COLUMN_OUTPUT[119]
    DIRECTION OUTPUT ;
    USE SIGNAL ;
    PORT
      LAYER Metal2 ;
        RECT 1028.865 0 1029.145 2059.200 ;
    END
  END COLUMN_OUTPUT[119]

  PIN COLUMN_OUTPUT[120]
    DIRECTION OUTPUT ;
    USE SIGNAL ;
    PORT
      LAYER Metal2 ;
        RECT 1037.445 0 1037.725 2059.200 ;
    END
  END COLUMN_OUTPUT[120]

  PIN COLUMN_OUTPUT[121]
    DIRECTION OUTPUT ;
    USE SIGNAL ;
    PORT
      LAYER Metal2 ;
        RECT 1046.025 0 1046.305 2059.200 ;
    END
  END COLUMN_OUTPUT[121]

  PIN COLUMN_OUTPUT[122]
    DIRECTION OUTPUT ;
    USE SIGNAL ;
    PORT
      LAYER Metal2 ;
        RECT 1054.605 0 1054.885 2059.200 ;
    END
  END COLUMN_OUTPUT[122]

  PIN COLUMN_OUTPUT[123]
    DIRECTION OUTPUT ;
    USE SIGNAL ;
    PORT
      LAYER Metal2 ;
        RECT 1063.185 0 1063.465 2059.200 ;
    END
  END COLUMN_OUTPUT[123]

  PIN COLUMN_OUTPUT[124]
    DIRECTION OUTPUT ;
    USE SIGNAL ;
    PORT
      LAYER Metal2 ;
        RECT 1071.765 0 1072.045 2059.200 ;
    END
  END COLUMN_OUTPUT[124]

  PIN COLUMN_OUTPUT[125]
    DIRECTION OUTPUT ;
    USE SIGNAL ;
    PORT
      LAYER Metal2 ;
        RECT 1080.345 0 1080.625 2059.200 ;
    END
  END COLUMN_OUTPUT[125]

  PIN COLUMN_OUTPUT[126]
    DIRECTION OUTPUT ;
    USE SIGNAL ;
    PORT
      LAYER Metal2 ;
        RECT 1088.925 0 1089.205 2059.200 ;
    END
  END COLUMN_OUTPUT[126]

  PIN COLUMN_OUTPUT[127]
    DIRECTION OUTPUT ;
    USE SIGNAL ;
    PORT
      LAYER Metal2 ;
        RECT 1097.505 0 1097.785 2059.200 ;
    END
  END COLUMN_OUTPUT[127]

  PIN COLUMN_OUTPUT[128]
    DIRECTION OUTPUT ;
    USE SIGNAL ;
    PORT
      LAYER Metal2 ;
        RECT 1106.085 0 1106.365 2059.200 ;
    END
  END COLUMN_OUTPUT[128]

  PIN COLUMN_OUTPUT[129]
    DIRECTION OUTPUT ;
    USE SIGNAL ;
    PORT
      LAYER Metal2 ;
        RECT 1114.665 0 1114.945 2059.200 ;
    END
  END COLUMN_OUTPUT[129]

  PIN COLUMN_OUTPUT[130]
    DIRECTION OUTPUT ;
    USE SIGNAL ;
    PORT
      LAYER Metal2 ;
        RECT 1123.245 0 1123.525 2059.200 ;
    END
  END COLUMN_OUTPUT[130]

  PIN COLUMN_OUTPUT[131]
    DIRECTION OUTPUT ;
    USE SIGNAL ;
    PORT
      LAYER Metal2 ;
        RECT 1131.825 0 1132.105 2059.200 ;
    END
  END COLUMN_OUTPUT[131]

  PIN COLUMN_OUTPUT[132]
    DIRECTION OUTPUT ;
    USE SIGNAL ;
    PORT
      LAYER Metal2 ;
        RECT 1140.405 0 1140.685 2059.200 ;
    END
  END COLUMN_OUTPUT[132]

  PIN COLUMN_OUTPUT[133]
    DIRECTION OUTPUT ;
    USE SIGNAL ;
    PORT
      LAYER Metal2 ;
        RECT 1148.985 0 1149.265 2059.200 ;
    END
  END COLUMN_OUTPUT[133]

  PIN COLUMN_OUTPUT[134]
    DIRECTION OUTPUT ;
    USE SIGNAL ;
    PORT
      LAYER Metal2 ;
        RECT 1157.565 0 1157.845 2059.200 ;
    END
  END COLUMN_OUTPUT[134]

  PIN COLUMN_OUTPUT[135]
    DIRECTION OUTPUT ;
    USE SIGNAL ;
    PORT
      LAYER Metal2 ;
        RECT 1166.145 0 1166.425 2059.200 ;
    END
  END COLUMN_OUTPUT[135]

  PIN COLUMN_OUTPUT[136]
    DIRECTION OUTPUT ;
    USE SIGNAL ;
    PORT
      LAYER Metal2 ;
        RECT 1174.725 0 1175.005 2059.200 ;
    END
  END COLUMN_OUTPUT[136]

  PIN COLUMN_OUTPUT[137]
    DIRECTION OUTPUT ;
    USE SIGNAL ;
    PORT
      LAYER Metal2 ;
        RECT 1183.305 0 1183.585 2059.200 ;
    END
  END COLUMN_OUTPUT[137]

  PIN COLUMN_OUTPUT[138]
    DIRECTION OUTPUT ;
    USE SIGNAL ;
    PORT
      LAYER Metal2 ;
        RECT 1191.885 0 1192.165 2059.200 ;
    END
  END COLUMN_OUTPUT[138]

  PIN COLUMN_OUTPUT[139]
    DIRECTION OUTPUT ;
    USE SIGNAL ;
    PORT
      LAYER Metal2 ;
        RECT 1200.465 0 1200.745 2059.200 ;
    END
  END COLUMN_OUTPUT[139]

  PIN COLUMN_OUTPUT[140]
    DIRECTION OUTPUT ;
    USE SIGNAL ;
    PORT
      LAYER Metal2 ;
        RECT 1209.045 0 1209.325 2059.200 ;
    END
  END COLUMN_OUTPUT[140]

  PIN COLUMN_OUTPUT[141]
    DIRECTION OUTPUT ;
    USE SIGNAL ;
    PORT
      LAYER Metal2 ;
        RECT 1217.625 0 1217.905 2059.200 ;
    END
  END COLUMN_OUTPUT[141]

  PIN COLUMN_OUTPUT[142]
    DIRECTION OUTPUT ;
    USE SIGNAL ;
    PORT
      LAYER Metal2 ;
        RECT 1226.205 0 1226.485 2059.200 ;
    END
  END COLUMN_OUTPUT[142]

  PIN COLUMN_OUTPUT[143]
    DIRECTION OUTPUT ;
    USE SIGNAL ;
    PORT
      LAYER Metal2 ;
        RECT 1234.785 0 1235.065 2059.200 ;
    END
  END COLUMN_OUTPUT[143]

  PIN COLUMN_OUTPUT[144]
    DIRECTION OUTPUT ;
    USE SIGNAL ;
    PORT
      LAYER Metal2 ;
        RECT 1243.365 0 1243.645 2059.200 ;
    END
  END COLUMN_OUTPUT[144]

  PIN COLUMN_OUTPUT[145]
    DIRECTION OUTPUT ;
    USE SIGNAL ;
    PORT
      LAYER Metal2 ;
        RECT 1251.945 0 1252.225 2059.200 ;
    END
  END COLUMN_OUTPUT[145]

  PIN COLUMN_OUTPUT[146]
    DIRECTION OUTPUT ;
    USE SIGNAL ;
    PORT
      LAYER Metal2 ;
        RECT 1260.525 0 1260.805 2059.200 ;
    END
  END COLUMN_OUTPUT[146]

  PIN COLUMN_OUTPUT[147]
    DIRECTION OUTPUT ;
    USE SIGNAL ;
    PORT
      LAYER Metal2 ;
        RECT 1269.105 0 1269.385 2059.200 ;
    END
  END COLUMN_OUTPUT[147]

  PIN COLUMN_OUTPUT[148]
    DIRECTION OUTPUT ;
    USE SIGNAL ;
    PORT
      LAYER Metal2 ;
        RECT 1277.685 0 1277.965 2059.200 ;
    END
  END COLUMN_OUTPUT[148]

  PIN COLUMN_OUTPUT[149]
    DIRECTION OUTPUT ;
    USE SIGNAL ;
    PORT
      LAYER Metal2 ;
        RECT 1286.265 0 1286.545 2059.200 ;
    END
  END COLUMN_OUTPUT[149]

  PIN COLUMN_OUTPUT[150]
    DIRECTION OUTPUT ;
    USE SIGNAL ;
    PORT
      LAYER Metal2 ;
        RECT 1294.845 0 1295.125 2059.200 ;
    END
  END COLUMN_OUTPUT[150]

  PIN COLUMN_OUTPUT[151]
    DIRECTION OUTPUT ;
    USE SIGNAL ;
    PORT
      LAYER Metal2 ;
        RECT 1303.425 0 1303.705 2059.200 ;
    END
  END COLUMN_OUTPUT[151]

  PIN COLUMN_OUTPUT[152]
    DIRECTION OUTPUT ;
    USE SIGNAL ;
    PORT
      LAYER Metal2 ;
        RECT 1312.005 0 1312.285 2059.200 ;
    END
  END COLUMN_OUTPUT[152]

  PIN COLUMN_OUTPUT[153]
    DIRECTION OUTPUT ;
    USE SIGNAL ;
    PORT
      LAYER Metal2 ;
        RECT 1320.585 0 1320.865 2059.200 ;
    END
  END COLUMN_OUTPUT[153]

  PIN COLUMN_OUTPUT[154]
    DIRECTION OUTPUT ;
    USE SIGNAL ;
    PORT
      LAYER Metal2 ;
        RECT 1329.165 0 1329.445 2059.200 ;
    END
  END COLUMN_OUTPUT[154]

  PIN COLUMN_OUTPUT[155]
    DIRECTION OUTPUT ;
    USE SIGNAL ;
    PORT
      LAYER Metal2 ;
        RECT 1337.745 0 1338.025 2059.200 ;
    END
  END COLUMN_OUTPUT[155]

  PIN COLUMN_OUTPUT[156]
    DIRECTION OUTPUT ;
    USE SIGNAL ;
    PORT
      LAYER Metal2 ;
        RECT 1346.325 0 1346.605 2059.200 ;
    END
  END COLUMN_OUTPUT[156]

  PIN COLUMN_OUTPUT[157]
    DIRECTION OUTPUT ;
    USE SIGNAL ;
    PORT
      LAYER Metal2 ;
        RECT 1354.905 0 1355.185 2059.200 ;
    END
  END COLUMN_OUTPUT[157]

  PIN COLUMN_OUTPUT[158]
    DIRECTION OUTPUT ;
    USE SIGNAL ;
    PORT
      LAYER Metal2 ;
        RECT 1363.485 0 1363.765 2059.200 ;
    END
  END COLUMN_OUTPUT[158]

  PIN COLUMN_OUTPUT[159]
    DIRECTION OUTPUT ;
    USE SIGNAL ;
    PORT
      LAYER Metal2 ;
        RECT 1372.065 0 1372.345 2059.200 ;
    END
  END COLUMN_OUTPUT[159]

  PIN COLUMN_OUTPUT[160]
    DIRECTION OUTPUT ;
    USE SIGNAL ;
    PORT
      LAYER Metal2 ;
        RECT 1380.645 0 1380.925 2059.200 ;
    END
  END COLUMN_OUTPUT[160]

  PIN COLUMN_OUTPUT[161]
    DIRECTION OUTPUT ;
    USE SIGNAL ;
    PORT
      LAYER Metal2 ;
        RECT 1389.225 0 1389.505 2059.200 ;
    END
  END COLUMN_OUTPUT[161]

  PIN COLUMN_OUTPUT[162]
    DIRECTION OUTPUT ;
    USE SIGNAL ;
    PORT
      LAYER Metal2 ;
        RECT 1397.805 0 1398.085 2059.200 ;
    END
  END COLUMN_OUTPUT[162]

  PIN COLUMN_OUTPUT[163]
    DIRECTION OUTPUT ;
    USE SIGNAL ;
    PORT
      LAYER Metal2 ;
        RECT 1406.385 0 1406.665 2059.200 ;
    END
  END COLUMN_OUTPUT[163]

  PIN COLUMN_OUTPUT[164]
    DIRECTION OUTPUT ;
    USE SIGNAL ;
    PORT
      LAYER Metal2 ;
        RECT 1414.965 0 1415.245 2059.200 ;
    END
  END COLUMN_OUTPUT[164]

  PIN COLUMN_OUTPUT[165]
    DIRECTION OUTPUT ;
    USE SIGNAL ;
    PORT
      LAYER Metal2 ;
        RECT 1423.545 0 1423.825 2059.200 ;
    END
  END COLUMN_OUTPUT[165]

  PIN COLUMN_OUTPUT[166]
    DIRECTION OUTPUT ;
    USE SIGNAL ;
    PORT
      LAYER Metal2 ;
        RECT 1432.125 0 1432.405 2059.200 ;
    END
  END COLUMN_OUTPUT[166]

  PIN COLUMN_OUTPUT[167]
    DIRECTION OUTPUT ;
    USE SIGNAL ;
    PORT
      LAYER Metal2 ;
        RECT 1440.705 0 1440.985 2059.200 ;
    END
  END COLUMN_OUTPUT[167]

  PIN COLUMN_OUTPUT[168]
    DIRECTION OUTPUT ;
    USE SIGNAL ;
    PORT
      LAYER Metal2 ;
        RECT 1449.285 0 1449.565 2059.200 ;
    END
  END COLUMN_OUTPUT[168]

  PIN COLUMN_OUTPUT[169]
    DIRECTION OUTPUT ;
    USE SIGNAL ;
    PORT
      LAYER Metal2 ;
        RECT 1457.865 0 1458.145 2059.200 ;
    END
  END COLUMN_OUTPUT[169]

  PIN COLUMN_OUTPUT[170]
    DIRECTION OUTPUT ;
    USE SIGNAL ;
    PORT
      LAYER Metal2 ;
        RECT 1466.445 0 1466.725 2059.200 ;
    END
  END COLUMN_OUTPUT[170]

  PIN COLUMN_OUTPUT[171]
    DIRECTION OUTPUT ;
    USE SIGNAL ;
    PORT
      LAYER Metal2 ;
        RECT 1475.025 0 1475.305 2059.200 ;
    END
  END COLUMN_OUTPUT[171]

  PIN COLUMN_OUTPUT[172]
    DIRECTION OUTPUT ;
    USE SIGNAL ;
    PORT
      LAYER Metal2 ;
        RECT 1483.605 0 1483.885 2059.200 ;
    END
  END COLUMN_OUTPUT[172]

  PIN COLUMN_OUTPUT[173]
    DIRECTION OUTPUT ;
    USE SIGNAL ;
    PORT
      LAYER Metal2 ;
        RECT 1492.185 0 1492.465 2059.200 ;
    END
  END COLUMN_OUTPUT[173]

  PIN COLUMN_OUTPUT[174]
    DIRECTION OUTPUT ;
    USE SIGNAL ;
    PORT
      LAYER Metal2 ;
        RECT 1500.765 0 1501.045 2059.200 ;
    END
  END COLUMN_OUTPUT[174]

  PIN COLUMN_OUTPUT[175]
    DIRECTION OUTPUT ;
    USE SIGNAL ;
    PORT
      LAYER Metal2 ;
        RECT 1509.345 0 1509.625 2059.200 ;
    END
  END COLUMN_OUTPUT[175]

  PIN COLUMN_OUTPUT[176]
    DIRECTION OUTPUT ;
    USE SIGNAL ;
    PORT
      LAYER Metal2 ;
        RECT 1517.925 0 1518.205 2059.200 ;
    END
  END COLUMN_OUTPUT[176]

  PIN COLUMN_OUTPUT[177]
    DIRECTION OUTPUT ;
    USE SIGNAL ;
    PORT
      LAYER Metal2 ;
        RECT 1526.505 0 1526.785 2059.200 ;
    END
  END COLUMN_OUTPUT[177]

  PIN COLUMN_OUTPUT[178]
    DIRECTION OUTPUT ;
    USE SIGNAL ;
    PORT
      LAYER Metal2 ;
        RECT 1535.085 0 1535.365 2059.200 ;
    END
  END COLUMN_OUTPUT[178]

  PIN COLUMN_OUTPUT[179]
    DIRECTION OUTPUT ;
    USE SIGNAL ;
    PORT
      LAYER Metal2 ;
        RECT 1543.665 0 1543.945 2059.200 ;
    END
  END COLUMN_OUTPUT[179]

  PIN COLUMN_OUTPUT[180]
    DIRECTION OUTPUT ;
    USE SIGNAL ;
    PORT
      LAYER Metal2 ;
        RECT 1552.245 0 1552.525 2059.200 ;
    END
  END COLUMN_OUTPUT[180]

  PIN COLUMN_OUTPUT[181]
    DIRECTION OUTPUT ;
    USE SIGNAL ;
    PORT
      LAYER Metal2 ;
        RECT 1560.825 0 1561.105 2059.200 ;
    END
  END COLUMN_OUTPUT[181]

  PIN COLUMN_OUTPUT[182]
    DIRECTION OUTPUT ;
    USE SIGNAL ;
    PORT
      LAYER Metal2 ;
        RECT 1569.405 0 1569.685 2059.200 ;
    END
  END COLUMN_OUTPUT[182]

  PIN COLUMN_OUTPUT[183]
    DIRECTION OUTPUT ;
    USE SIGNAL ;
    PORT
      LAYER Metal2 ;
        RECT 1577.985 0 1578.265 2059.200 ;
    END
  END COLUMN_OUTPUT[183]

  PIN COLUMN_OUTPUT[184]
    DIRECTION OUTPUT ;
    USE SIGNAL ;
    PORT
      LAYER Metal2 ;
        RECT 1586.565 0 1586.845 2059.200 ;
    END
  END COLUMN_OUTPUT[184]

  PIN COLUMN_OUTPUT[185]
    DIRECTION OUTPUT ;
    USE SIGNAL ;
    PORT
      LAYER Metal2 ;
        RECT 1595.145 0 1595.425 2059.200 ;
    END
  END COLUMN_OUTPUT[185]

  PIN COLUMN_OUTPUT[186]
    DIRECTION OUTPUT ;
    USE SIGNAL ;
    PORT
      LAYER Metal2 ;
        RECT 1603.725 0 1604.005 2059.200 ;
    END
  END COLUMN_OUTPUT[186]

  PIN COLUMN_OUTPUT[187]
    DIRECTION OUTPUT ;
    USE SIGNAL ;
    PORT
      LAYER Metal2 ;
        RECT 1612.305 0 1612.585 2059.200 ;
    END
  END COLUMN_OUTPUT[187]

  PIN COLUMN_OUTPUT[188]
    DIRECTION OUTPUT ;
    USE SIGNAL ;
    PORT
      LAYER Metal2 ;
        RECT 1620.885 0 1621.165 2059.200 ;
    END
  END COLUMN_OUTPUT[188]

  PIN COLUMN_OUTPUT[189]
    DIRECTION OUTPUT ;
    USE SIGNAL ;
    PORT
      LAYER Metal2 ;
        RECT 1629.465 0 1629.745 2059.200 ;
    END
  END COLUMN_OUTPUT[189]

  PIN COLUMN_OUTPUT[190]
    DIRECTION OUTPUT ;
    USE SIGNAL ;
    PORT
      LAYER Metal2 ;
        RECT 1638.045 0 1638.325 2059.200 ;
    END
  END COLUMN_OUTPUT[190]

  PIN COLUMN_OUTPUT[191]
    DIRECTION OUTPUT ;
    USE SIGNAL ;
    PORT
      LAYER Metal2 ;
        RECT 1646.625 0 1646.905 2059.200 ;
    END
  END COLUMN_OUTPUT[191]

  PIN COLUMN_OUTPUT[192]
    DIRECTION OUTPUT ;
    USE SIGNAL ;
    PORT
      LAYER Metal2 ;
        RECT 1655.205 0 1655.485 2059.200 ;
    END
  END COLUMN_OUTPUT[192]

  PIN COLUMN_OUTPUT[193]
    DIRECTION OUTPUT ;
    USE SIGNAL ;
    PORT
      LAYER Metal2 ;
        RECT 1663.785 0 1664.065 2059.200 ;
    END
  END COLUMN_OUTPUT[193]

  PIN COLUMN_OUTPUT[194]
    DIRECTION OUTPUT ;
    USE SIGNAL ;
    PORT
      LAYER Metal2 ;
        RECT 1672.365 0 1672.645 2059.200 ;
    END
  END COLUMN_OUTPUT[194]

  PIN COLUMN_OUTPUT[195]
    DIRECTION OUTPUT ;
    USE SIGNAL ;
    PORT
      LAYER Metal2 ;
        RECT 1680.945 0 1681.225 2059.200 ;
    END
  END COLUMN_OUTPUT[195]

  PIN COLUMN_OUTPUT[196]
    DIRECTION OUTPUT ;
    USE SIGNAL ;
    PORT
      LAYER Metal2 ;
        RECT 1689.525 0 1689.805 2059.200 ;
    END
  END COLUMN_OUTPUT[196]

  PIN COLUMN_OUTPUT[197]
    DIRECTION OUTPUT ;
    USE SIGNAL ;
    PORT
      LAYER Metal2 ;
        RECT 1698.105 0 1698.385 2059.200 ;
    END
  END COLUMN_OUTPUT[197]

  PIN COLUMN_OUTPUT[198]
    DIRECTION OUTPUT ;
    USE SIGNAL ;
    PORT
      LAYER Metal2 ;
        RECT 1706.685 0 1706.965 2059.200 ;
    END
  END COLUMN_OUTPUT[198]

  PIN COLUMN_OUTPUT[199]
    DIRECTION OUTPUT ;
    USE SIGNAL ;
    PORT
      LAYER Metal2 ;
        RECT 1715.265 0 1715.545 2059.200 ;
    END
  END COLUMN_OUTPUT[199]

  PIN COLUMN_OUTPUT[200]
    DIRECTION OUTPUT ;
    USE SIGNAL ;
    PORT
      LAYER Metal2 ;
        RECT 1723.845 0 1724.125 2059.200 ;
    END
  END COLUMN_OUTPUT[200]

  PIN COLUMN_OUTPUT[201]
    DIRECTION OUTPUT ;
    USE SIGNAL ;
    PORT
      LAYER Metal2 ;
        RECT 1732.425 0 1732.705 2059.200 ;
    END
  END COLUMN_OUTPUT[201]

  PIN COLUMN_OUTPUT[202]
    DIRECTION OUTPUT ;
    USE SIGNAL ;
    PORT
      LAYER Metal2 ;
        RECT 1741.005 0 1741.285 2059.200 ;
    END
  END COLUMN_OUTPUT[202]

  PIN COLUMN_OUTPUT[203]
    DIRECTION OUTPUT ;
    USE SIGNAL ;
    PORT
      LAYER Metal2 ;
        RECT 1749.585 0 1749.865 2059.200 ;
    END
  END COLUMN_OUTPUT[203]

  PIN COLUMN_OUTPUT[204]
    DIRECTION OUTPUT ;
    USE SIGNAL ;
    PORT
      LAYER Metal2 ;
        RECT 1758.165 0 1758.445 2059.200 ;
    END
  END COLUMN_OUTPUT[204]

  PIN COLUMN_OUTPUT[205]
    DIRECTION OUTPUT ;
    USE SIGNAL ;
    PORT
      LAYER Metal2 ;
        RECT 1766.745 0 1767.025 2059.200 ;
    END
  END COLUMN_OUTPUT[205]

  PIN COLUMN_OUTPUT[206]
    DIRECTION OUTPUT ;
    USE SIGNAL ;
    PORT
      LAYER Metal2 ;
        RECT 1775.325 0 1775.605 2059.200 ;
    END
  END COLUMN_OUTPUT[206]

  PIN COLUMN_OUTPUT[207]
    DIRECTION OUTPUT ;
    USE SIGNAL ;
    PORT
      LAYER Metal2 ;
        RECT 1783.905 0 1784.185 2059.200 ;
    END
  END COLUMN_OUTPUT[207]

  PIN COLUMN_OUTPUT[208]
    DIRECTION OUTPUT ;
    USE SIGNAL ;
    PORT
      LAYER Metal2 ;
        RECT 1792.485 0 1792.765 2059.200 ;
    END
  END COLUMN_OUTPUT[208]

  PIN COLUMN_OUTPUT[209]
    DIRECTION OUTPUT ;
    USE SIGNAL ;
    PORT
      LAYER Metal2 ;
        RECT 1801.065 0 1801.345 2059.200 ;
    END
  END COLUMN_OUTPUT[209]

  PIN COLUMN_OUTPUT[210]
    DIRECTION OUTPUT ;
    USE SIGNAL ;
    PORT
      LAYER Metal2 ;
        RECT 1809.645 0 1809.925 2059.200 ;
    END
  END COLUMN_OUTPUT[210]

  PIN COLUMN_OUTPUT[211]
    DIRECTION OUTPUT ;
    USE SIGNAL ;
    PORT
      LAYER Metal2 ;
        RECT 1818.225 0 1818.505 2059.200 ;
    END
  END COLUMN_OUTPUT[211]

  PIN COLUMN_OUTPUT[212]
    DIRECTION OUTPUT ;
    USE SIGNAL ;
    PORT
      LAYER Metal2 ;
        RECT 1826.805 0 1827.085 2059.200 ;
    END
  END COLUMN_OUTPUT[212]

  PIN COLUMN_OUTPUT[213]
    DIRECTION OUTPUT ;
    USE SIGNAL ;
    PORT
      LAYER Metal2 ;
        RECT 1835.385 0 1835.665 2059.200 ;
    END
  END COLUMN_OUTPUT[213]

  PIN COLUMN_OUTPUT[214]
    DIRECTION OUTPUT ;
    USE SIGNAL ;
    PORT
      LAYER Metal2 ;
        RECT 1843.965 0 1844.245 2059.200 ;
    END
  END COLUMN_OUTPUT[214]

  PIN COLUMN_OUTPUT[215]
    DIRECTION OUTPUT ;
    USE SIGNAL ;
    PORT
      LAYER Metal2 ;
        RECT 1852.545 0 1852.825 2059.200 ;
    END
  END COLUMN_OUTPUT[215]

  PIN COLUMN_OUTPUT[216]
    DIRECTION OUTPUT ;
    USE SIGNAL ;
    PORT
      LAYER Metal2 ;
        RECT 1861.125 0 1861.405 2059.200 ;
    END
  END COLUMN_OUTPUT[216]

  PIN COLUMN_OUTPUT[217]
    DIRECTION OUTPUT ;
    USE SIGNAL ;
    PORT
      LAYER Metal2 ;
        RECT 1869.705 0 1869.985 2059.200 ;
    END
  END COLUMN_OUTPUT[217]

  PIN COLUMN_OUTPUT[218]
    DIRECTION OUTPUT ;
    USE SIGNAL ;
    PORT
      LAYER Metal2 ;
        RECT 1878.285 0 1878.565 2059.200 ;
    END
  END COLUMN_OUTPUT[218]

  PIN COLUMN_OUTPUT[219]
    DIRECTION OUTPUT ;
    USE SIGNAL ;
    PORT
      LAYER Metal2 ;
        RECT 1886.865 0 1887.145 2059.200 ;
    END
  END COLUMN_OUTPUT[219]

  PIN COLUMN_OUTPUT[220]
    DIRECTION OUTPUT ;
    USE SIGNAL ;
    PORT
      LAYER Metal2 ;
        RECT 1895.445 0 1895.725 2059.200 ;
    END
  END COLUMN_OUTPUT[220]

  PIN COLUMN_OUTPUT[221]
    DIRECTION OUTPUT ;
    USE SIGNAL ;
    PORT
      LAYER Metal2 ;
        RECT 1904.025 0 1904.305 2059.200 ;
    END
  END COLUMN_OUTPUT[221]

  PIN COLUMN_OUTPUT[222]
    DIRECTION OUTPUT ;
    USE SIGNAL ;
    PORT
      LAYER Metal2 ;
        RECT 1912.605 0 1912.885 2059.200 ;
    END
  END COLUMN_OUTPUT[222]

  PIN COLUMN_OUTPUT[223]
    DIRECTION OUTPUT ;
    USE SIGNAL ;
    PORT
      LAYER Metal2 ;
        RECT 1921.185 0 1921.465 2059.200 ;
    END
  END COLUMN_OUTPUT[223]

  PIN COLUMN_OUTPUT[224]
    DIRECTION OUTPUT ;
    USE SIGNAL ;
    PORT
      LAYER Metal2 ;
        RECT 1929.765 0 1930.045 2059.200 ;
    END
  END COLUMN_OUTPUT[224]

  PIN COLUMN_OUTPUT[225]
    DIRECTION OUTPUT ;
    USE SIGNAL ;
    PORT
      LAYER Metal2 ;
        RECT 1938.345 0 1938.625 2059.200 ;
    END
  END COLUMN_OUTPUT[225]

  PIN COLUMN_OUTPUT[226]
    DIRECTION OUTPUT ;
    USE SIGNAL ;
    PORT
      LAYER Metal2 ;
        RECT 1946.925 0 1947.205 2059.200 ;
    END
  END COLUMN_OUTPUT[226]

  PIN COLUMN_OUTPUT[227]
    DIRECTION OUTPUT ;
    USE SIGNAL ;
    PORT
      LAYER Metal2 ;
        RECT 1955.505 0 1955.785 2059.200 ;
    END
  END COLUMN_OUTPUT[227]

  PIN COLUMN_OUTPUT[228]
    DIRECTION OUTPUT ;
    USE SIGNAL ;
    PORT
      LAYER Metal2 ;
        RECT 1964.085 0 1964.365 2059.200 ;
    END
  END COLUMN_OUTPUT[228]

  PIN COLUMN_OUTPUT[229]
    DIRECTION OUTPUT ;
    USE SIGNAL ;
    PORT
      LAYER Metal2 ;
        RECT 1972.665 0 1972.945 2059.200 ;
    END
  END COLUMN_OUTPUT[229]

  PIN COLUMN_OUTPUT[230]
    DIRECTION OUTPUT ;
    USE SIGNAL ;
    PORT
      LAYER Metal2 ;
        RECT 1981.245 0 1981.525 2059.200 ;
    END
  END COLUMN_OUTPUT[230]

  PIN COLUMN_OUTPUT[231]
    DIRECTION OUTPUT ;
    USE SIGNAL ;
    PORT
      LAYER Metal2 ;
        RECT 1989.825 0 1990.105 2059.200 ;
    END
  END COLUMN_OUTPUT[231]

  PIN COLUMN_OUTPUT[232]
    DIRECTION OUTPUT ;
    USE SIGNAL ;
    PORT
      LAYER Metal2 ;
        RECT 1998.405 0 1998.685 2059.200 ;
    END
  END COLUMN_OUTPUT[232]

  PIN COLUMN_OUTPUT[233]
    DIRECTION OUTPUT ;
    USE SIGNAL ;
    PORT
      LAYER Metal2 ;
        RECT 2006.985 0 2007.265 2059.200 ;
    END
  END COLUMN_OUTPUT[233]

  PIN COLUMN_OUTPUT[234]
    DIRECTION OUTPUT ;
    USE SIGNAL ;
    PORT
      LAYER Metal2 ;
        RECT 2015.565 0 2015.845 2059.200 ;
    END
  END COLUMN_OUTPUT[234]

  PIN COLUMN_OUTPUT[235]
    DIRECTION OUTPUT ;
    USE SIGNAL ;
    PORT
      LAYER Metal2 ;
        RECT 2024.145 0 2024.425 2059.200 ;
    END
  END COLUMN_OUTPUT[235]

  PIN COLUMN_OUTPUT[236]
    DIRECTION OUTPUT ;
    USE SIGNAL ;
    PORT
      LAYER Metal2 ;
        RECT 2032.725 0 2033.005 2059.200 ;
    END
  END COLUMN_OUTPUT[236]

  PIN COLUMN_OUTPUT[237]
    DIRECTION OUTPUT ;
    USE SIGNAL ;
    PORT
      LAYER Metal2 ;
        RECT 2041.305 0 2041.585 2059.200 ;
    END
  END COLUMN_OUTPUT[237]

  PIN COLUMN_OUTPUT[238]
    DIRECTION OUTPUT ;
    USE SIGNAL ;
    PORT
      LAYER Metal2 ;
        RECT 2049.885 0 2050.165 2059.200 ;
    END
  END COLUMN_OUTPUT[238]

  PIN COLUMN_OUTPUT[239]
    DIRECTION OUTPUT ;
    USE SIGNAL ;
    PORT
      LAYER Metal2 ;
        RECT 2058.465 0 2058.745 2059.200 ;
    END
  END COLUMN_OUTPUT[239]

  PIN COLUMN_OUTPUT[240]
    DIRECTION OUTPUT ;
    USE SIGNAL ;
    PORT
      LAYER Metal2 ;
        RECT 2067.045 0 2067.325 2059.200 ;
    END
  END COLUMN_OUTPUT[240]

  PIN COLUMN_OUTPUT[241]
    DIRECTION OUTPUT ;
    USE SIGNAL ;
    PORT
      LAYER Metal2 ;
        RECT 2075.625 0 2075.905 2059.200 ;
    END
  END COLUMN_OUTPUT[241]

  PIN COLUMN_OUTPUT[242]
    DIRECTION OUTPUT ;
    USE SIGNAL ;
    PORT
      LAYER Metal2 ;
        RECT 2084.205 0 2084.485 2059.200 ;
    END
  END COLUMN_OUTPUT[242]

  PIN COLUMN_OUTPUT[243]
    DIRECTION OUTPUT ;
    USE SIGNAL ;
    PORT
      LAYER Metal2 ;
        RECT 2092.785 0 2093.065 2059.200 ;
    END
  END COLUMN_OUTPUT[243]

  PIN COLUMN_OUTPUT[244]
    DIRECTION OUTPUT ;
    USE SIGNAL ;
    PORT
      LAYER Metal2 ;
        RECT 2101.365 0 2101.645 2059.200 ;
    END
  END COLUMN_OUTPUT[244]

  PIN COLUMN_OUTPUT[245]
    DIRECTION OUTPUT ;
    USE SIGNAL ;
    PORT
      LAYER Metal2 ;
        RECT 2109.945 0 2110.225 2059.200 ;
    END
  END COLUMN_OUTPUT[245]

  PIN COLUMN_OUTPUT[246]
    DIRECTION OUTPUT ;
    USE SIGNAL ;
    PORT
      LAYER Metal2 ;
        RECT 2118.525 0 2118.805 2059.200 ;
    END
  END COLUMN_OUTPUT[246]

  PIN COLUMN_OUTPUT[247]
    DIRECTION OUTPUT ;
    USE SIGNAL ;
    PORT
      LAYER Metal2 ;
        RECT 2127.105 0 2127.385 2059.200 ;
    END
  END COLUMN_OUTPUT[247]

  PIN COLUMN_OUTPUT[248]
    DIRECTION OUTPUT ;
    USE SIGNAL ;
    PORT
      LAYER Metal2 ;
        RECT 2135.685 0 2135.965 2059.200 ;
    END
  END COLUMN_OUTPUT[248]

  PIN COLUMN_OUTPUT[249]
    DIRECTION OUTPUT ;
    USE SIGNAL ;
    PORT
      LAYER Metal2 ;
        RECT 2144.265 0 2144.545 2059.200 ;
    END
  END COLUMN_OUTPUT[249]

  PIN COLUMN_OUTPUT[250]
    DIRECTION OUTPUT ;
    USE SIGNAL ;
    PORT
      LAYER Metal2 ;
        RECT 2152.845 0 2153.125 2059.200 ;
    END
  END COLUMN_OUTPUT[250]

  PIN COLUMN_OUTPUT[251]
    DIRECTION OUTPUT ;
    USE SIGNAL ;
    PORT
      LAYER Metal2 ;
        RECT 2161.425 0 2161.705 2059.200 ;
    END
  END COLUMN_OUTPUT[251]

  PIN COLUMN_OUTPUT[252]
    DIRECTION OUTPUT ;
    USE SIGNAL ;
    PORT
      LAYER Metal2 ;
        RECT 2170.005 0 2170.285 2059.200 ;
    END
  END COLUMN_OUTPUT[252]

  PIN COLUMN_OUTPUT[253]
    DIRECTION OUTPUT ;
    USE SIGNAL ;
    PORT
      LAYER Metal2 ;
        RECT 2178.585 0 2178.865 2059.200 ;
    END
  END COLUMN_OUTPUT[253]

  PIN COLUMN_OUTPUT[254]
    DIRECTION OUTPUT ;
    USE SIGNAL ;
    PORT
      LAYER Metal2 ;
        RECT 2187.165 0 2187.445 2059.200 ;
    END
  END COLUMN_OUTPUT[254]

  PIN COLUMN_OUTPUT[255]
    DIRECTION OUTPUT ;
    USE SIGNAL ;
    PORT
      LAYER Metal2 ;
        RECT 2195.745 0 2196.025 2059.200 ;
    END
  END COLUMN_OUTPUT[255]

  PIN COLUMN_OUTPUT[256]
    DIRECTION OUTPUT ;
    USE SIGNAL ;
    PORT
      LAYER Metal2 ;
        RECT 2204.325 0 2204.605 2059.200 ;
    END
  END COLUMN_OUTPUT[256]

  PIN COLUMN_OUTPUT[257]
    DIRECTION OUTPUT ;
    USE SIGNAL ;
    PORT
      LAYER Metal2 ;
        RECT 2212.905 0 2213.185 2059.200 ;
    END
  END COLUMN_OUTPUT[257]

  PIN COLUMN_OUTPUT[258]
    DIRECTION OUTPUT ;
    USE SIGNAL ;
    PORT
      LAYER Metal2 ;
        RECT 2221.485 0 2221.765 2059.200 ;
    END
  END COLUMN_OUTPUT[258]

  PIN COLUMN_OUTPUT[259]
    DIRECTION OUTPUT ;
    USE SIGNAL ;
    PORT
      LAYER Metal2 ;
        RECT 2230.065 0 2230.345 2059.200 ;
    END
  END COLUMN_OUTPUT[259]

  PIN COLUMN_OUTPUT[260]
    DIRECTION OUTPUT ;
    USE SIGNAL ;
    PORT
      LAYER Metal2 ;
        RECT 2238.645 0 2238.925 2059.200 ;
    END
  END COLUMN_OUTPUT[260]

  PIN COLUMN_OUTPUT[261]
    DIRECTION OUTPUT ;
    USE SIGNAL ;
    PORT
      LAYER Metal2 ;
        RECT 2247.225 0 2247.505 2059.200 ;
    END
  END COLUMN_OUTPUT[261]

  PIN COLUMN_OUTPUT[262]
    DIRECTION OUTPUT ;
    USE SIGNAL ;
    PORT
      LAYER Metal2 ;
        RECT 2255.805 0 2256.085 2059.200 ;
    END
  END COLUMN_OUTPUT[262]

  PIN COLUMN_OUTPUT[263]
    DIRECTION OUTPUT ;
    USE SIGNAL ;
    PORT
      LAYER Metal2 ;
        RECT 2264.385 0 2264.665 2059.200 ;
    END
  END COLUMN_OUTPUT[263]

  PIN COLUMN_OUTPUT[264]
    DIRECTION OUTPUT ;
    USE SIGNAL ;
    PORT
      LAYER Metal2 ;
        RECT 2272.965 0 2273.245 2059.200 ;
    END
  END COLUMN_OUTPUT[264]

  PIN COLUMN_OUTPUT[265]
    DIRECTION OUTPUT ;
    USE SIGNAL ;
    PORT
      LAYER Metal2 ;
        RECT 2281.545 0 2281.825 2059.200 ;
    END
  END COLUMN_OUTPUT[265]

  PIN COLUMN_OUTPUT[266]
    DIRECTION OUTPUT ;
    USE SIGNAL ;
    PORT
      LAYER Metal2 ;
        RECT 2290.125 0 2290.405 2059.200 ;
    END
  END COLUMN_OUTPUT[266]

  PIN COLUMN_OUTPUT[267]
    DIRECTION OUTPUT ;
    USE SIGNAL ;
    PORT
      LAYER Metal2 ;
        RECT 2298.705 0 2298.985 2059.200 ;
    END
  END COLUMN_OUTPUT[267]

  PIN COLUMN_OUTPUT[268]
    DIRECTION OUTPUT ;
    USE SIGNAL ;
    PORT
      LAYER Metal2 ;
        RECT 2307.285 0 2307.565 2059.200 ;
    END
  END COLUMN_OUTPUT[268]

  PIN COLUMN_OUTPUT[269]
    DIRECTION OUTPUT ;
    USE SIGNAL ;
    PORT
      LAYER Metal2 ;
        RECT 2315.865 0 2316.145 2059.200 ;
    END
  END COLUMN_OUTPUT[269]

  PIN COLUMN_OUTPUT[270]
    DIRECTION OUTPUT ;
    USE SIGNAL ;
    PORT
      LAYER Metal2 ;
        RECT 2324.445 0 2324.725 2059.200 ;
    END
  END COLUMN_OUTPUT[270]

  PIN COLUMN_OUTPUT[271]
    DIRECTION OUTPUT ;
    USE SIGNAL ;
    PORT
      LAYER Metal2 ;
        RECT 2333.025 0 2333.305 2059.200 ;
    END
  END COLUMN_OUTPUT[271]

  PIN COLUMN_OUTPUT[272]
    DIRECTION OUTPUT ;
    USE SIGNAL ;
    PORT
      LAYER Metal2 ;
        RECT 2341.605 0 2341.885 2059.200 ;
    END
  END COLUMN_OUTPUT[272]

  PIN COLUMN_OUTPUT[273]
    DIRECTION OUTPUT ;
    USE SIGNAL ;
    PORT
      LAYER Metal2 ;
        RECT 2350.185 0 2350.465 2059.200 ;
    END
  END COLUMN_OUTPUT[273]

  PIN COLUMN_OUTPUT[274]
    DIRECTION OUTPUT ;
    USE SIGNAL ;
    PORT
      LAYER Metal2 ;
        RECT 2358.765 0 2359.045 2059.200 ;
    END
  END COLUMN_OUTPUT[274]

  PIN COLUMN_OUTPUT[275]
    DIRECTION OUTPUT ;
    USE SIGNAL ;
    PORT
      LAYER Metal2 ;
        RECT 2367.345 0 2367.625 2059.200 ;
    END
  END COLUMN_OUTPUT[275]

  PIN COLUMN_OUTPUT[276]
    DIRECTION OUTPUT ;
    USE SIGNAL ;
    PORT
      LAYER Metal2 ;
        RECT 2375.925 0 2376.205 2059.200 ;
    END
  END COLUMN_OUTPUT[276]

  PIN COLUMN_OUTPUT[277]
    DIRECTION OUTPUT ;
    USE SIGNAL ;
    PORT
      LAYER Metal2 ;
        RECT 2384.505 0 2384.785 2059.200 ;
    END
  END COLUMN_OUTPUT[277]

  PIN COLUMN_OUTPUT[278]
    DIRECTION OUTPUT ;
    USE SIGNAL ;
    PORT
      LAYER Metal2 ;
        RECT 2393.085 0 2393.365 2059.200 ;
    END
  END COLUMN_OUTPUT[278]

  PIN COLUMN_OUTPUT[279]
    DIRECTION OUTPUT ;
    USE SIGNAL ;
    PORT
      LAYER Metal2 ;
        RECT 2401.665 0 2401.945 2059.200 ;
    END
  END COLUMN_OUTPUT[279]

  PIN COLUMN_OUTPUT[280]
    DIRECTION OUTPUT ;
    USE SIGNAL ;
    PORT
      LAYER Metal2 ;
        RECT 2410.245 0 2410.525 2059.200 ;
    END
  END COLUMN_OUTPUT[280]

  PIN COLUMN_OUTPUT[281]
    DIRECTION OUTPUT ;
    USE SIGNAL ;
    PORT
      LAYER Metal2 ;
        RECT 2418.825 0 2419.105 2059.200 ;
    END
  END COLUMN_OUTPUT[281]

  PIN COLUMN_OUTPUT[282]
    DIRECTION OUTPUT ;
    USE SIGNAL ;
    PORT
      LAYER Metal2 ;
        RECT 2427.405 0 2427.685 2059.200 ;
    END
  END COLUMN_OUTPUT[282]

  PIN COLUMN_OUTPUT[283]
    DIRECTION OUTPUT ;
    USE SIGNAL ;
    PORT
      LAYER Metal2 ;
        RECT 2435.985 0 2436.265 2059.200 ;
    END
  END COLUMN_OUTPUT[283]

  PIN COLUMN_OUTPUT[284]
    DIRECTION OUTPUT ;
    USE SIGNAL ;
    PORT
      LAYER Metal2 ;
        RECT 2444.565 0 2444.845 2059.200 ;
    END
  END COLUMN_OUTPUT[284]

  PIN COLUMN_OUTPUT[285]
    DIRECTION OUTPUT ;
    USE SIGNAL ;
    PORT
      LAYER Metal2 ;
        RECT 2453.145 0 2453.425 2059.200 ;
    END
  END COLUMN_OUTPUT[285]

  PIN COLUMN_OUTPUT[286]
    DIRECTION OUTPUT ;
    USE SIGNAL ;
    PORT
      LAYER Metal2 ;
        RECT 2461.725 0 2462.005 2059.200 ;
    END
  END COLUMN_OUTPUT[286]

  PIN COLUMN_OUTPUT[287]
    DIRECTION OUTPUT ;
    USE SIGNAL ;
    PORT
      LAYER Metal2 ;
        RECT 2470.305 0 2470.585 2059.200 ;
    END
  END COLUMN_OUTPUT[287]

  PIN COLUMN_OUTPUT[288]
    DIRECTION OUTPUT ;
    USE SIGNAL ;
    PORT
      LAYER Metal2 ;
        RECT 2478.885 0 2479.165 2059.200 ;
    END
  END COLUMN_OUTPUT[288]

  PIN COLUMN_OUTPUT[289]
    DIRECTION OUTPUT ;
    USE SIGNAL ;
    PORT
      LAYER Metal2 ;
        RECT 2487.465 0 2487.745 2059.200 ;
    END
  END COLUMN_OUTPUT[289]

  PIN COLUMN_OUTPUT[290]
    DIRECTION OUTPUT ;
    USE SIGNAL ;
    PORT
      LAYER Metal2 ;
        RECT 2496.045 0 2496.325 2059.200 ;
    END
  END COLUMN_OUTPUT[290]

  PIN COLUMN_OUTPUT[291]
    DIRECTION OUTPUT ;
    USE SIGNAL ;
    PORT
      LAYER Metal2 ;
        RECT 2504.625 0 2504.905 2059.200 ;
    END
  END COLUMN_OUTPUT[291]

  PIN COLUMN_OUTPUT[292]
    DIRECTION OUTPUT ;
    USE SIGNAL ;
    PORT
      LAYER Metal2 ;
        RECT 2513.205 0 2513.485 2059.200 ;
    END
  END COLUMN_OUTPUT[292]

  PIN COLUMN_OUTPUT[293]
    DIRECTION OUTPUT ;
    USE SIGNAL ;
    PORT
      LAYER Metal2 ;
        RECT 2521.785 0 2522.065 2059.200 ;
    END
  END COLUMN_OUTPUT[293]

  PIN COLUMN_OUTPUT[294]
    DIRECTION OUTPUT ;
    USE SIGNAL ;
    PORT
      LAYER Metal2 ;
        RECT 2530.365 0 2530.645 2059.200 ;
    END
  END COLUMN_OUTPUT[294]

  PIN COLUMN_OUTPUT[295]
    DIRECTION OUTPUT ;
    USE SIGNAL ;
    PORT
      LAYER Metal2 ;
        RECT 2538.945 0 2539.225 2059.200 ;
    END
  END COLUMN_OUTPUT[295]

  PIN COLUMN_OUTPUT[296]
    DIRECTION OUTPUT ;
    USE SIGNAL ;
    PORT
      LAYER Metal2 ;
        RECT 2547.525 0 2547.805 2059.200 ;
    END
  END COLUMN_OUTPUT[296]

  PIN COLUMN_OUTPUT[297]
    DIRECTION OUTPUT ;
    USE SIGNAL ;
    PORT
      LAYER Metal2 ;
        RECT 2556.105 0 2556.385 2059.200 ;
    END
  END COLUMN_OUTPUT[297]

  PIN COLUMN_OUTPUT[298]
    DIRECTION OUTPUT ;
    USE SIGNAL ;
    PORT
      LAYER Metal2 ;
        RECT 2564.685 0 2564.965 2059.200 ;
    END
  END COLUMN_OUTPUT[298]

  PIN COLUMN_OUTPUT[299]
    DIRECTION OUTPUT ;
    USE SIGNAL ;
    PORT
      LAYER Metal2 ;
        RECT 2573.265 0 2573.545 2059.200 ;
    END
  END COLUMN_OUTPUT[299]

  PIN COLUMN_OUTPUT[300]
    DIRECTION OUTPUT ;
    USE SIGNAL ;
    PORT
      LAYER Metal2 ;
        RECT 2581.845 0 2582.125 2059.200 ;
    END
  END COLUMN_OUTPUT[300]

  PIN COLUMN_OUTPUT[301]
    DIRECTION OUTPUT ;
    USE SIGNAL ;
    PORT
      LAYER Metal2 ;
        RECT 2590.425 0 2590.705 2059.200 ;
    END
  END COLUMN_OUTPUT[301]

  PIN COLUMN_OUTPUT[302]
    DIRECTION OUTPUT ;
    USE SIGNAL ;
    PORT
      LAYER Metal2 ;
        RECT 2599.005 0 2599.285 2059.200 ;
    END
  END COLUMN_OUTPUT[302]

  PIN COLUMN_OUTPUT[303]
    DIRECTION OUTPUT ;
    USE SIGNAL ;
    PORT
      LAYER Metal2 ;
        RECT 2607.585 0 2607.865 2059.200 ;
    END
  END COLUMN_OUTPUT[303]

  PIN COLUMN_OUTPUT[304]
    DIRECTION OUTPUT ;
    USE SIGNAL ;
    PORT
      LAYER Metal2 ;
        RECT 2616.165 0 2616.445 2059.200 ;
    END
  END COLUMN_OUTPUT[304]

  PIN COLUMN_OUTPUT[305]
    DIRECTION OUTPUT ;
    USE SIGNAL ;
    PORT
      LAYER Metal2 ;
        RECT 2624.745 0 2625.025 2059.200 ;
    END
  END COLUMN_OUTPUT[305]

  PIN COLUMN_OUTPUT[306]
    DIRECTION OUTPUT ;
    USE SIGNAL ;
    PORT
      LAYER Metal2 ;
        RECT 2633.325 0 2633.605 2059.200 ;
    END
  END COLUMN_OUTPUT[306]

  PIN COLUMN_OUTPUT[307]
    DIRECTION OUTPUT ;
    USE SIGNAL ;
    PORT
      LAYER Metal2 ;
        RECT 2641.905 0 2642.185 2059.200 ;
    END
  END COLUMN_OUTPUT[307]

  PIN COLUMN_OUTPUT[308]
    DIRECTION OUTPUT ;
    USE SIGNAL ;
    PORT
      LAYER Metal2 ;
        RECT 2650.485 0 2650.765 2059.200 ;
    END
  END COLUMN_OUTPUT[308]

  PIN COLUMN_OUTPUT[309]
    DIRECTION OUTPUT ;
    USE SIGNAL ;
    PORT
      LAYER Metal2 ;
        RECT 2659.065 0 2659.345 2059.200 ;
    END
  END COLUMN_OUTPUT[309]

  PIN COLUMN_OUTPUT[310]
    DIRECTION OUTPUT ;
    USE SIGNAL ;
    PORT
      LAYER Metal2 ;
        RECT 2667.645 0 2667.925 2059.200 ;
    END
  END COLUMN_OUTPUT[310]

  PIN COLUMN_OUTPUT[311]
    DIRECTION OUTPUT ;
    USE SIGNAL ;
    PORT
      LAYER Metal2 ;
        RECT 2676.225 0 2676.505 2059.200 ;
    END
  END COLUMN_OUTPUT[311]

  PIN COLUMN_OUTPUT[312]
    DIRECTION OUTPUT ;
    USE SIGNAL ;
    PORT
      LAYER Metal2 ;
        RECT 2684.805 0 2685.085 2059.200 ;
    END
  END COLUMN_OUTPUT[312]

  PIN COLUMN_OUTPUT[313]
    DIRECTION OUTPUT ;
    USE SIGNAL ;
    PORT
      LAYER Metal2 ;
        RECT 2693.385 0 2693.665 2059.200 ;
    END
  END COLUMN_OUTPUT[313]

  PIN COLUMN_OUTPUT[314]
    DIRECTION OUTPUT ;
    USE SIGNAL ;
    PORT
      LAYER Metal2 ;
        RECT 2701.965 0 2702.245 2059.200 ;
    END
  END COLUMN_OUTPUT[314]

  PIN COLUMN_OUTPUT[315]
    DIRECTION OUTPUT ;
    USE SIGNAL ;
    PORT
      LAYER Metal2 ;
        RECT 2710.545 0 2710.825 2059.200 ;
    END
  END COLUMN_OUTPUT[315]

  PIN COLUMN_OUTPUT[316]
    DIRECTION OUTPUT ;
    USE SIGNAL ;
    PORT
      LAYER Metal2 ;
        RECT 2719.125 0 2719.405 2059.200 ;
    END
  END COLUMN_OUTPUT[316]

  PIN COLUMN_OUTPUT[317]
    DIRECTION OUTPUT ;
    USE SIGNAL ;
    PORT
      LAYER Metal2 ;
        RECT 2727.705 0 2727.985 2059.200 ;
    END
  END COLUMN_OUTPUT[317]

  PIN COLUMN_OUTPUT[318]
    DIRECTION OUTPUT ;
    USE SIGNAL ;
    PORT
      LAYER Metal2 ;
        RECT 2736.285 0 2736.565 2059.200 ;
    END
  END COLUMN_OUTPUT[318]

  PIN COLUMN_OUTPUT[319]
    DIRECTION OUTPUT ;
    USE SIGNAL ;
    PORT
      LAYER Metal2 ;
        RECT 2744.865 0 2745.145 2059.200 ;
    END
  END COLUMN_OUTPUT[319]

  PIN COLUMN_OUTPUT[320]
    DIRECTION OUTPUT ;
    USE SIGNAL ;
    PORT
      LAYER Metal2 ;
        RECT 2753.445 0 2753.725 2059.200 ;
    END
  END COLUMN_OUTPUT[320]

END PIXEL_ARRAY
